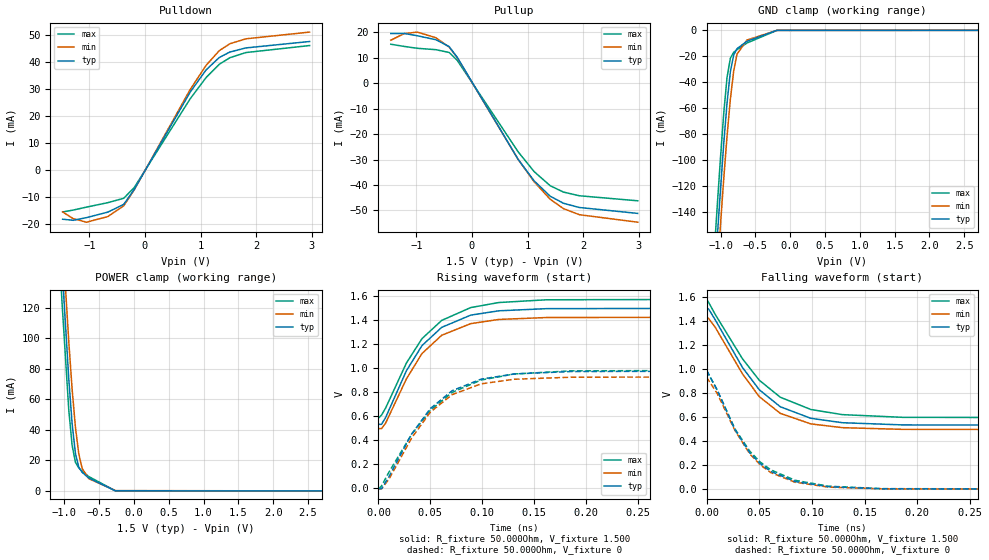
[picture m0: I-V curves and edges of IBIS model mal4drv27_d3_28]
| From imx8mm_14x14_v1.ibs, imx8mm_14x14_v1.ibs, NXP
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[Model] mal4drv27_d3_28
Model_type   I/O
Polarity   Non-Inverting
Enable   Active-High
C_comp   1.533pF   1.523pF   1.539pF
C_comp_pullup   670.608fF   654.490fF   675.558fF
C_comp_pulldown 804.263fF   796.382fF   819.192fF
Vinh = 885.000mV
Vinl = 615.000mV
Vmeas = 750.000mV
Vref = 750.000mV
Rref = 50Ohms
Cref = 0pF
[Model Spec]
Vinh   885.000mV   848.000mV   923.000mV
Vinl   615.000mV   578.000mV   653.000mV
Vmeas   750.000mV   713.000mV   788.000mV
Vref   750.000mV   713.000mV   788.000mV
D_overshoot_ampl_h 0.4 NA   NA
D_overshoot_ampl_l 0.4 NA   NA
D_overshoot_area_l 100.000m NA   NA
D_overshoot_area_h 100.000m NA   NA
|[Receiver Thresholds]
|Vth = 750.000mV
|Vth_min = 713.000mV
|Vth_max = 788.000mV
|Vinh_ac = 135.000mV
|Vinh_dc = 100.000mV
|Vinl_ac = -135.000mV
|Vinl_dc = -100.000mV
|Tslew_ac = 5.000ns
|Threshold_sensitivity = 0.5
|Reference_supply Pullup_ref
[Temperature Range]   25.000   125.000   -40.000
[Voltage Range]   1.500V   1.425V   1.575V
[GND Clamp Reference]   0.00V   0.00V   0.00V
|[C Comp Corner]
|| variable   typ   min   max
|C_comp 1.539pF   1.523pF   1.533pF
|C_comp_pullup 675.558fF   654.490fF   670.608fF
|C_comp_pulldown 804.263fF   819.192fF   796.382fF
[Pulldown Reference]   0.00V   0.00V   0.00V
[POWER Clamp Reference]   1.500V   1.425V   1.575V
[Pullup Reference]   1.500V   1.425V   1.575V
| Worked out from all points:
|   slope of the pulldown table from 0 to 0.225 V, typ, clamps not added: 27 ohm
|   slope of the pullup table from 0 to 0.225 V, typ, clamps not added: 26.4 ohm
|   GND clamp passes 1 mA (typ) near -0.34 V on its own axis
|   POWER clamp passes 1 mA (typ) near -0.38 V on its own axis
|   rising waveform, R_fixture 50.000Ohm, V_fixture 1.500: 20-80 % time 41.5ps typ, 40.5ps min, 44.6ps max; typ from 0.53 V to 1.5 V
|   rising waveform, R_fixture 50.000Ohm, V_fixture 0: 20-80 % time 49.5ps typ, 47ps min, 55.1ps max; typ from -0.006 V to 0.975 V
|   falling waveform, R_fixture 50.000Ohm, V_fixture 1.500: 20-80 % time 48.7ps typ, 45.6ps min, 52.4ps max; typ from 1.51 V to 0.531 V
|   falling waveform, R_fixture 50.000Ohm, V_fixture 0: 20-80 % time 41.1ps typ, 40.2ps min, 43.1ps max; typ from 0.987 V to 0 V
[GND Clamp]
-1.48V    -544.8mA   -568.8mA   -521.8mA
-1.098V   -202mA     -228.3mA   -177.7mA
-1.05V    -162.1mA   -188.8mA   -137.5mA
-1.002V   -123.7mA   -150.8mA   -99.19mA
-954.6mV  -87.74mA   -114.8mA   -64.27mA
-906.8mV  -56.04mA   -81.7mA    -36.4mA
-859.1mV  -31.98mA   -53.11mA   -21.49mA
-811.4mV  -19.02mA   -31.4mA    -16.97mA
-763.6mV  -14.17mA   -18.33mA   -14.9mA
-620.5mV  -8.403mA   -7.484mA   -9.776mA
-190.9mV  -18.19uA   -37.84uA   -39.11uA
2.959V    60.05nA    717.2nA    25.66nA
[Power Clamp]
-1.459V   528mA      548.1mA    506.8mA
-1.125V   225.9mA    248.6mA    203.4mA
-1.077V   185.1mA    208.4mA    162.3mA
-1.03V    145.5mA    169.5mA    122.6mA
-934.1mV  73.22mA    97.65mA    52.94mA
-886.4mV  44.08mA    66.72mA    29.89mA
-838.6mV  24.44mA    41.59mA    18.79mA
-790.9mV  15.63mA    24.32mA    15.05mA
-743.2mV  12.25mA    14.83mA    13mA
-647.7mV  8.45mA     8.03mA     9.427mA
-265.9mV  72.13uA    219.4uA    104uA
2.98V     -171.5nA   -1.946uA   -77.31nA
[Pulldown]
-1.48V    -18.3mA    -15.6mA    -15.6mA
-1.289V   -18.7mA    -18.1mA    -14.9mA
-1.05V    -17.7mA    -19.4mA    -13.8mA
-668.2mV  -15.66mA   -17.31mA   -12.15mA
-381.8mV  -12.79mA   -13.32mA   -10.52mA
-190.9mV  -7.166mA   -7.317mA   -6.472mA
811.4mV   28.86mA    29.82mA    26.39mA
1.098V    37.13mA    38.82mA    34.29mA
1.336V    41.77mA    44.32mA    39.24mA
1.527V    43.8mA     46.87mA    41.69mA
1.814V    45.32mA    48.7mA     43.6mA
2.959V    47.7mA     51.2mA     46.2mA
[Pullup]
-1.459V   19.6mA     16.94mA    15.36mA
-1.22V    19.6mA     19.53mA    14.51mA
-981.8mV  18.7mA     20.14mA    13.76mA
-647.7mV  17.13mA    17.91mA    13.22mA
-409.1mV  14.41mA    14.22mA    12.11mA
-265.9mV  10.25mA    10.11mA    9.057mA
831.8mV   -29.99mA   -30.03mA   -27.02mA
1.118V    -38.41mA   -38.76mA   -34.76mA
1.405V    -44.41mA   -45.6mA    -40.29mA
1.643V    -47.2mA    -49.3mA    -42.8mA
1.93V     -48.88mA   -51.71mA   -44.26mA
2.98V     -51.2mA    -54.66mA   -46.24mA
[Ramp]
R_load=50.000Ohm
dV/dt_r   583.230mV/46.000ps  556.979mV/44.500ps  589.380mV/51.000ps
dV/dt_f   583.230mV/46.000ps  556.979mV/44.000ps  589.380mV/49.000ps
[Rising waveform]
R_fixture=50.000Ohm
V_fixture=1.500
V_fixture_min=1.425
V_fixture_max=1.575
0s        530.4mV    494.7mV    582.1mV
3ps       530.4mV    494.7mV    607.7mV
7ps       588.4mV    542mV      667.8mV
27ps      977.4mV    909.9mV    1.042V
42ps      1.187V     1.121V     1.245V
61ps      1.339V     1.273V     1.397V
89ps      1.441V     1.37V      1.504V
116ps     1.477V     1.405V     1.546V
162ps     1.495V     1.421V     1.569V
472ps     1.5V       1.425V     1.575V
[Rising waveform]
R_fixture=50.000Ohm
V_fixture=0
0s        -6.374mV   -7.44mV    -10.22mV
3ps       -6.374mV   -7.44mV    17.2mV
10ps      92.15mV    71.39mV    129.8mV
32ps      449.3mV    415.8mV    447.3mV
50ps      661.4mV    631.8mV    647.2mV
71ps      810.4mV    777.8mV    796.3mV
99ps      907.2mV    867.9mV    899.7mV
131ps     950.5mV    906.4mV    950.3mV
186ps     970.9mV    923.4mV    976.5mV
472ps     975.3mV    926.8mV    982.7mV
[Falling waveform]
R_fixture=50.000Ohm
V_fixture=1.500
V_fixture_min=1.425
V_fixture_max=1.575
0s        1.509V     1.428V     1.581V
2ps       1.497V     1.419V     1.552V
8ps       1.411V     1.349V     1.456V
34ps      1.013V     960.1mV    1.085V
50ps      827.1mV    769.5mV    906.1mV
70ps      685.3mV    630.4mV    764.5mV
99ps      589.3mV    542.9mV    662.4mV
129ps     552.7mV    511.4mV    619.9mV
186ps     534.4mV    497.4mV    597.5mV
470ps     531.3mV    495.3mV    593.3mV
[Falling waveform]
R_fixture=50.000Ohm
V_fixture=0
0s        986.6mV    930.6mV    988.4mV
10ps      825.6mV    796.4mV    824.7mV
27ps      493.4mV    486.5mV    500mV
41ps      302.2mV    293.5mV    315.4mV
51ps      211.4mV    201.6mV    224.9mV
61ps      147.7mV    137.9mV    160.7mV
84ps      63.62mV    57.49mV    73.68mV
116ps     20.23mV    16.84mV    24.51mV
167ps     3.111mV    2.429mV    4.208mV
469ps     16.12uV    19.39uV    17.05uV
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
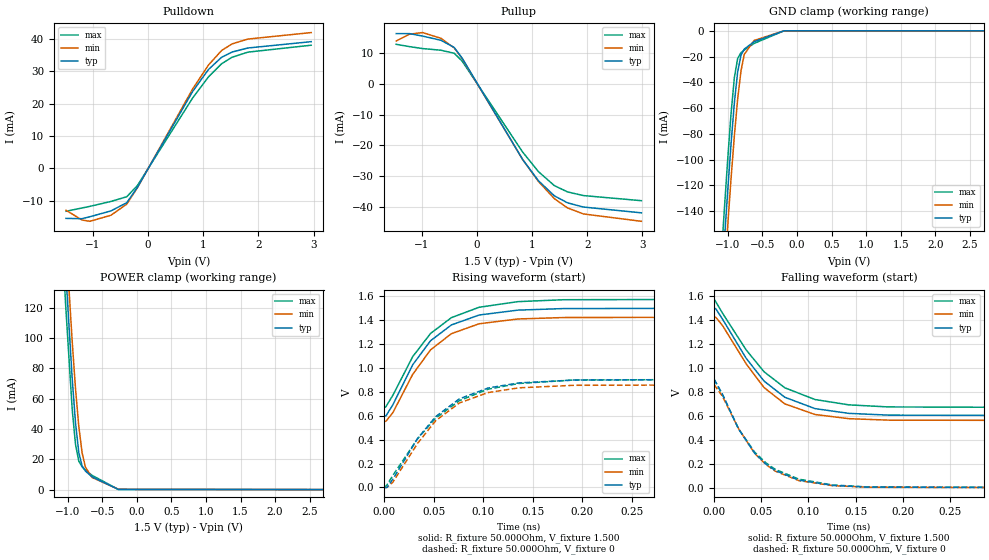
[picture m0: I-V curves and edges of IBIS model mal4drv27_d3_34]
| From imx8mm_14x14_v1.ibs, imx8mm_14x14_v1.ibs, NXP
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[Model] mal4drv27_d3_34
Model_type   I/O
Polarity   Non-Inverting
Enable   Active-High
C_comp   1.533pF   1.523pF   1.539pF
C_comp_pullup   670.608fF   654.490fF   675.558fF
C_comp_pulldown 804.263fF   796.382fF   819.192fF
Vinh = 885.000mV
Vinl = 615.000mV
Vmeas = 750.000mV
Vref = 750.000mV
Rref = 50Ohms
Cref = 0pF
[Model Spec]
Vinh   885.000mV   848.000mV   923.000mV
Vinl   615.000mV   578.000mV   653.000mV
Vmeas   750.000mV   713.000mV   788.000mV
Vref   750.000mV   713.000mV   788.000mV
D_overshoot_ampl_h 0.4 NA   NA
D_overshoot_ampl_l 0.4 NA   NA
D_overshoot_area_l 100.000m NA   NA
D_overshoot_area_h 100.000m NA   NA
|[Receiver Thresholds]
|Vth = 750.000mV
|Vth_min = 713.000mV
|Vth_max = 788.000mV
|Vinh_ac = 135.000mV
|Vinh_dc = 100.000mV
|Vinl_ac = -135.000mV
|Vinl_dc = -100.000mV
|Tslew_ac = 5.000ns
|Threshold_sensitivity = 0.5
|Reference_supply Pullup_ref
[Temperature Range]   25.000   125.000   -40.000
[Voltage Range]   1.500V   1.425V   1.575V
[GND Clamp Reference]   0.00V   0.00V   0.00V
|[C Comp Corner]
|| variable   typ   min   max
|C_comp 1.539pF   1.523pF   1.533pF
|C_comp_pullup 675.558fF   654.490fF   670.608fF
|C_comp_pulldown 804.263fF   819.192fF   796.382fF
[Pulldown Reference]   0.00V   0.00V   0.00V
[POWER Clamp Reference]   1.500V   1.425V   1.575V
[Pullup Reference]   1.500V   1.425V   1.575V
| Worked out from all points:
|   slope of the pulldown table from 0 to 0.225 V, typ, clamps not added: 32.8 ohm
|   slope of the pullup table from 0 to 0.225 V, typ, clamps not added: 32.1 ohm
|   GND clamp passes 1 mA (typ) near -0.34 V on its own axis
|   POWER clamp passes 1 mA (typ) near -0.38 V on its own axis
|   rising waveform, R_fixture 50.000Ohm, V_fixture 1.500: 20-80 % time 46.3ps typ, 45.6ps min, 49.1ps max; typ from 0.598 V to 1.5 V
|   rising waveform, R_fixture 50.000Ohm, V_fixture 0: 20-80 % time 55.5ps typ, 52.8ps min, 60.9ps max; typ from 0 V to 0.905 V
|   falling waveform, R_fixture 50.000Ohm, V_fixture 1.500: 20-80 % time 54.3ps typ, 51.1ps min, 57.7ps max; typ from 1.5 V to 0.602 V
|   falling waveform, R_fixture 50.000Ohm, V_fixture 0: 20-80 % time 45.7ps typ, 44.8ps min, 47.8ps max; typ from 0.908 V to 0 V
[GND Clamp]
-1.48V    -544.8mA   -568.8mA   -521.8mA
-1.098V   -202mA     -228.3mA   -177.7mA
-1.05V    -162.1mA   -188.8mA   -137.5mA
-1.002V   -123.7mA   -150.8mA   -99.19mA
-954.6mV  -87.74mA   -114.8mA   -64.27mA
-906.8mV  -56.04mA   -81.7mA    -36.4mA
-859.1mV  -31.98mA   -53.11mA   -21.49mA
-811.4mV  -19.02mA   -31.4mA    -16.97mA
-763.6mV  -14.17mA   -18.33mA   -14.9mA
-620.5mV  -8.403mA   -7.484mA   -9.776mA
-190.9mV  -18.19uA   -37.84uA   -39.11uA
2.959V    60.05nA    717.2nA    25.66nA
[Power Clamp]
-1.459V   528mA      548.1mA    506.8mA
-1.125V   225.9mA    248.6mA    203.4mA
-1.077V   185.1mA    208.4mA    162.3mA
-1.03V    145.5mA    169.5mA    122.6mA
-934.1mV  73.22mA    97.65mA    52.94mA
-886.4mV  44.08mA    66.72mA    29.89mA
-838.6mV  24.44mA    41.59mA    18.79mA
-790.9mV  15.63mA    24.32mA    15.05mA
-743.2mV  12.25mA    14.83mA    13mA
-647.7mV  8.45mA     8.03mA     9.427mA
-265.9mV  72.13uA    219.4uA    104uA
2.98V     -171.5nA   -1.946uA   -77.31nA
[Pulldown]
-1.48V    -15.4mA    -12.9mA    -13.2mA
-1.193V   -15.5mA    -15.9mA    -12.2mA
-1.05V    -14.9mA    -16.3mA    -11.7mA
-668.2mV  -13.1mA    -14.44mA   -10.18mA
-381.8mV  -10.57mA   -11.01mA   -8.726mA
-190.9mV  -5.895mA   -6.016mA   -5.33mA
811.4mV   23.73mA    24.5mA     21.72mA
1.098V    30.51mA    31.88mA    28.23mA
1.336V    34.29mA    36.37mA    32.29mA
1.527V    35.91mA    38.42mA    34.3mA
1.814V    37.15mA    39.9mA     35.87mA
2.959V    39.1mA     41.9mA     38mA
[Pullup]
-1.459V   16.4mA     13.99mA    12.91mA
-1.22V    16.4mA     16.21mA    12.16mA
-981.8mV  15.6mA     16.74mA    11.53mA
-647.7mV  14.22mA    14.86mA    10.98mA
-409.1mV  11.89mA    11.73mA    10mA
-265.9mV  8.431mA    8.312mA    7.457mA
831.8mV   -24.66mA   -24.66mA   -22.23mA
1.118V    -31.57mA   -31.81mA   -28.6mA
1.405V    -36.47mA   -37.39mA   -33.14mA
1.643V    -38.74mA   -40.4mA    -35.18mA
1.93V     -40.11mA   -42.36mA   -36.38mA
2.98V     -42mA      -44.76mA   -38.04mA
[Ramp]
R_load=50.000Ohm
dV/dt_r   540.840mV/52.000ps  516.868mV/50.500ps  543.990mV/55.500ps
dV/dt_f   540.840mV/50.500ps  516.899mV/49.000ps  543.990mV/54.000ps
[Rising waveform]
R_fixture=50.000Ohm
V_fixture=1.500
V_fixture_min=1.425
V_fixture_max=1.575
0s        598.3mV    553.6mV    665.3mV
2ps       598.3mV    553.6mV    675.7mV
9ps       692mV      625.8mV    771.2mV
29ps      1.026V     945.9mV    1.094V
47ps      1.227V     1.151V     1.288V
68ps      1.359V     1.286V     1.42V
96ps      1.442V     1.369V     1.507V
135ps     1.483V     1.409V     1.554V
181ps     1.496V     1.421V     1.57V
471ps     1.5V       1.425V     1.575V
[Rising waveform]
R_fixture=50.000Ohm
V_fixture=0
0s        -432.4uV   -59.57uV   -3.267mV
3ps       -432.4uV   -59.57uV   19.98mV
9ps       69.75mV    44.27mV    101.4mV
34ps      410.8mV    369.8mV    408.6mV
52ps      591.3mV    556.5mV    578.3mV
76ps      740.6mV    706.4mV    725.9mV
105ps     831.9mV    793.6mV    821.7mV
136ps     874.3mV    833.2mV    869.6mV
192ps     898.4mV    854.5mV    898.8mV
472ps     904.7mV    859.5mV    907mV
[Falling waveform]
R_fixture=50.000Ohm
V_fixture=1.500
V_fixture_min=1.425
V_fixture_max=1.575
0s        1.504V     1.43V      1.577V
2ps       1.494V     1.423V     1.552V
9ps       1.409V     1.356V     1.459V
34ps      1.083V     1.037V     1.153V
53ps      892.3mV    838mV      970.2mV
75ps      757.1mV    701.9mV    836.3mV
107ps     662.2mV    613mV      738.1mV
143ps     622.4mV    578.1mV    693.5mV
185ps     607.7mV    565.9mV    676.2mV
470ps     601.9mV    561.6mV    668.8mV
[Falling waveform]
R_fixture=50.000Ohm
V_fixture=0
0s        908.5mV    863.1mV    906.9mV
9ps       780.6mV    763.5mV    776.1mV
26ps      491.2mV    494.1mV    493.6mV
43ps      290.1mV    287.9mV    299.1mV
55ps      198.7mV    194.2mV    209.2mV
65ps      144.5mV    139.3mV    154.2mV
90ps      64.4mV     60.54mV    72.51mV
126ps     20.19mV    18.16mV    23.97mV
163ps     6.293mV    5.311mV    7.625mV
469ps     14.93uV    17.67uV    16.07uV
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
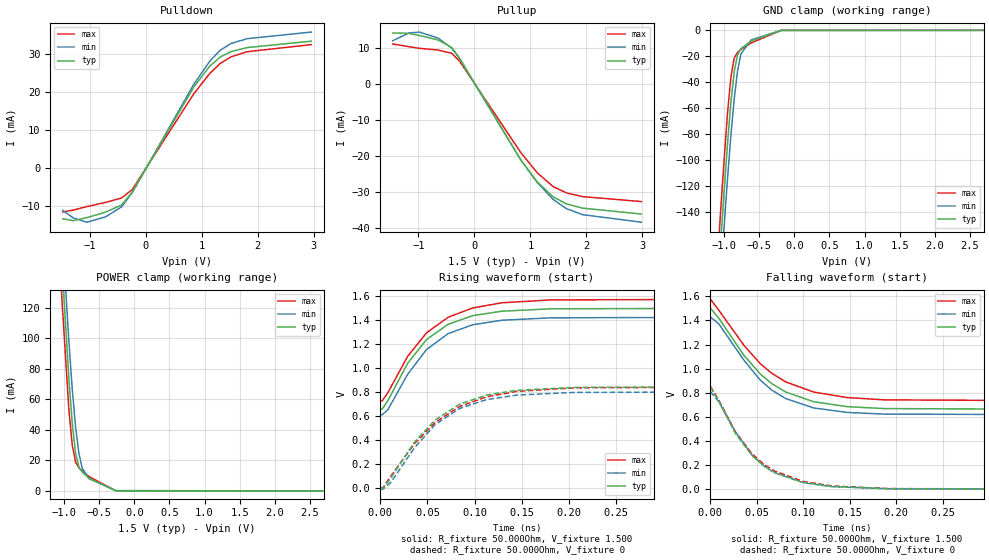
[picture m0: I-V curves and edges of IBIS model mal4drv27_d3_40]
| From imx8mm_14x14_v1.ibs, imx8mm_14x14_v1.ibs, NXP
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[Model] mal4drv27_d3_40
Model_type   I/O
Polarity   Non-Inverting
Enable   Active-High
C_comp   1.533pF   1.523pF   1.539pF
C_comp_pullup   670.608fF   654.490fF   675.558fF
C_comp_pulldown 804.263fF   796.382fF   819.192fF
Vinh = 885.000mV
Vinl = 615.000mV
Vmeas = 750.000mV
Vref = 750.000mV
Rref = 50Ohms
Cref = 0pF
[Model Spec]
Vinh   885.000mV   848.000mV   923.000mV
Vinl   615.000mV   578.000mV   653.000mV
Vmeas   750.000mV   713.000mV   788.000mV
Vref   750.000mV   713.000mV   788.000mV
D_overshoot_ampl_h 0.4 NA   NA
D_overshoot_ampl_l 0.4 NA   NA
D_overshoot_area_l 100.000m NA   NA
D_overshoot_area_h 100.000m NA   NA
|[Receiver Thresholds]
|Vth = 750.000mV
|Vth_min = 713.000mV
|Vth_max = 788.000mV
|Vinh_ac = 135.000mV
|Vinh_dc = 100.000mV
|Vinl_ac = -135.000mV
|Vinl_dc = -100.000mV
|Tslew_ac = 5.000ns
|Threshold_sensitivity = 0.5
|Reference_supply Pullup_ref
[Temperature Range]   25.000   125.000   -40.000
[Voltage Range]   1.500V   1.425V   1.575V
[GND Clamp Reference]   0.00V   0.00V   0.00V
|[C Comp Corner]
|| variable   typ   min   max
|C_comp 1.539pF   1.523pF   1.533pF
|C_comp_pullup 675.558fF   654.490fF   670.608fF
|C_comp_pulldown 804.263fF   819.192fF   796.382fF
[Pulldown Reference]   0.00V   0.00V   0.00V
[POWER Clamp Reference]   1.500V   1.425V   1.575V
[Pullup Reference]   1.500V   1.425V   1.575V
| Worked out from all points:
|   slope of the pulldown table from 0 to 0.225 V, typ, clamps not added: 38.3 ohm
|   slope of the pullup table from 0 to 0.225 V, typ, clamps not added: 37.5 ohm
|   GND clamp passes 1 mA (typ) near -0.34 V on its own axis
|   POWER clamp passes 1 mA (typ) near -0.38 V on its own axis
|   rising waveform, R_fixture 50.000Ohm, V_fixture 1.500: 20-80 % time 50.2ps typ, 49.3ps min, 52.9ps max; typ from 0.659 V to 1.5 V
|   rising waveform, R_fixture 50.000Ohm, V_fixture 0: 20-80 % time 60.3ps typ, 57.6ps min, 65.6ps max; typ from 0 V to 0.846 V
|   falling waveform, R_fixture 50.000Ohm, V_fixture 1.500: 20-80 % time 59.2ps typ, 55.5ps min, 62.4ps max; typ from 1.5 V to 0.66 V
|   falling waveform, R_fixture 50.000Ohm, V_fixture 0: 20-80 % time 49.5ps typ, 48.5ps min, 51.7ps max; typ from 0.847 V to 0 V
[GND Clamp]
-1.48V    -544.8mA   -568.8mA   -521.8mA
-1.098V   -202mA     -228.3mA   -177.7mA
-1.05V    -162.1mA   -188.8mA   -137.5mA
-1.002V   -123.7mA   -150.8mA   -99.19mA
-954.6mV  -87.74mA   -114.8mA   -64.27mA
-906.8mV  -56.04mA   -81.7mA    -36.4mA
-859.1mV  -31.98mA   -53.11mA   -21.49mA
-811.4mV  -19.02mA   -31.4mA    -16.97mA
-763.6mV  -14.17mA   -18.33mA   -14.9mA
-620.5mV  -8.403mA   -7.484mA   -9.776mA
-190.9mV  -18.19uA   -37.84uA   -39.11uA
2.959V    60.05nA    717.2nA    25.66nA
[Power Clamp]
-1.459V   528mA      548.1mA    506.8mA
-1.125V   225.9mA    248.6mA    203.4mA
-1.077V   185.1mA    208.4mA    162.3mA
-1.03V    145.5mA    169.5mA    122.6mA
-934.1mV  73.22mA    97.65mA    52.94mA
-886.4mV  44.08mA    66.72mA    29.89mA
-838.6mV  24.44mA    41.59mA    18.79mA
-790.9mV  15.63mA    24.32mA    15.05mA
-743.2mV  12.25mA    14.83mA    13mA
-647.7mV  8.45mA     8.03mA     9.427mA
-265.9mV  72.13uA    219.4uA    104uA
2.98V     -171.5nA   -1.946uA   -77.31nA
[Pulldown]
-1.48V    -13.3mA    -11.1mA    -11.5mA
-1.289V   -13.8mA    -13.1mA    -11mA
-1.05V    -13mA      -14.2mA    -10.1mA
-715.9mV  -11.56mA   -12.8mA    -8.98mA
-429.5mV  -9.667mA   -10.17mA   -7.842mA
-238.6mV  -6.277mA   -6.401mA   -5.606mA
859.1mV   21.39mA    22.11mA    19.61mA
1.145V    26.92mA    28.21mA    24.99mA
1.336V    29.36mA    31.15mA    27.67mA
1.527V    30.76mA    32.91mA    29.39mA
1.814V    31.82mA    34.17mA    30.73mA
2.959V    33.5mA     35.9mA     32.6mA
[Pullup]
-1.459V   14.2mA     12.03mA    11.16mA
-1.173V   14.1mA     14.17mA    10.4mA
-981.8mV  13.5mA     14.44mA    9.949mA
-647.7mV  12.25mA    12.77mA    9.455mA
-409.1mV  10.2mA     10.05mA    8.58mA
-265.9mV  7.219mA    7.111mA    6.387mA
831.8mV   -21.11mA   -21.08mA   -19.04mA
1.118V    -27.03mA   -27.19mA   -24.5mA
1.405V    -31.23mA   -31.95mA   -28.39mA
1.643V    -33.18mA   -34.51mA   -30.14mA
1.93V     -34.36mA   -36.17mA   -31.17mA
2.98V     -36mA      -38.26mA   -32.54mA
[Ramp]
R_load=50.000Ohm
dV/dt_r   505.770mV/56.500ps  483.718mV/54.000ps  506.700mV/60.000ps
dV/dt_f   505.770mV/55.500ps  483.719mV/52.500ps  506.700mV/57.500ps
[Rising waveform]
R_fixture=50.000Ohm
V_fixture=1.500
V_fixture_min=1.425
V_fixture_max=1.575
0s        658.8mV    612.3mV    727.8mV
2ps       658.8mV    612.3mV    727.8mV
8ps       729.2mV    653.9mV    795.7mV
29ps      1.04V      948.6mV    1.098V
49ps      1.238V     1.155V     1.294V
72ps      1.365V     1.288V     1.424V
98ps      1.437V     1.361V     1.501V
129ps     1.474V     1.399V     1.544V
181ps     1.494V     1.419V     1.568V
471ps     1.5V       1.425V     1.575V
[Rising waveform]
R_fixture=50.000Ohm
V_fixture=0
0s        -153.4uV   -6.514mV   -2.403mV
3ps       -153.4uV   -6.514mV   7.118mV
11ps      84.07mV    48.43mV    100.2mV
36ps      381.9mV    334.9mV    369.5mV
58ps      567.9mV    529.4mV    547.4mV
84ps      700.1mV    664.1mV    680.9mV
113ps     777mV      739.2mV    762.5mV
145ps     815.9mV    776.4mV    807.4mV
207ps     840.2mV    798.5mV    836.8mV
472ps     846.2mV    803.7mV    844.6mV
[Falling waveform]
R_fixture=50.000Ohm
V_fixture=1.500
V_fixture_min=1.425
V_fixture_max=1.575
0s        1.503V     1.428V     1.577V
9ps       1.42V      1.373V     1.486V
36ps      1.112V     1.072V     1.195V
54ps      953.4mV    902.7mV    1.039V
66ps      876.1mV    822.6mV    962.1mV
81ps      806.3mV    751.8mV    890.2mV
111ps     725.4mV    674mV      805.9mV
147ps     684.7mV    636.5mV    760mV
187ps     668.4mV    622.8mV    740.9mV
470ps     660.3mV    616.3mV    730.7mV
[Falling waveform]
R_fixture=50.000Ohm
V_fixture=0
0s        846.9mV    810.5mV    853.9mV
9ps       732.2mV    726.8mV    741.1mV
27ps      462.3mV    475.2mV    476.1mV
45ps      277mV      281.5mV    292.5mV
58ps      190.1mV    190.8mV    204.4mV
69ps      138mV      136.6mV    150.9mV
100ps     55.26mV    53.45mV    63.65mV
131ps     22.12mV    20.65mV    26.33mV
191ps     3.849mV    3.316mV    4.76mV
469ps     15.91uV    19.07uV    17.08uV
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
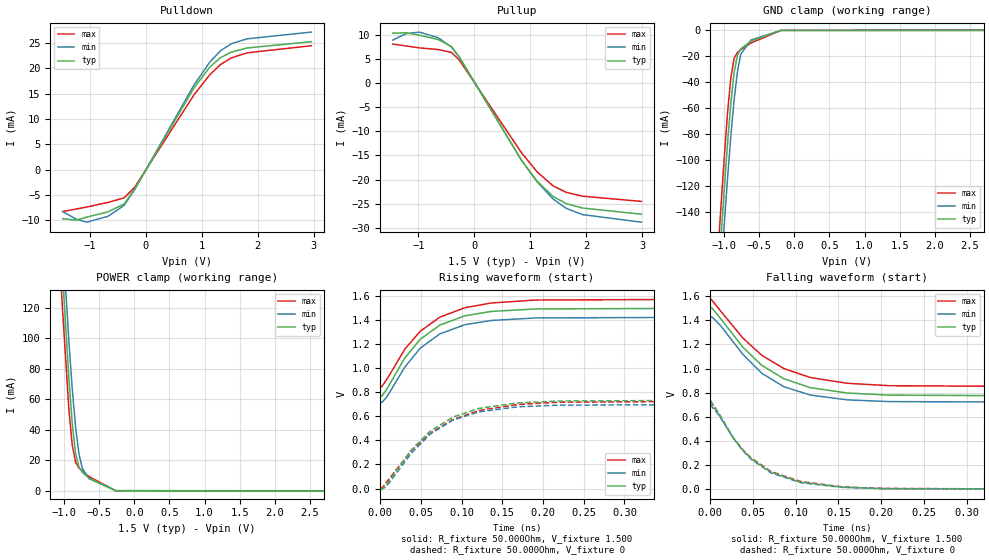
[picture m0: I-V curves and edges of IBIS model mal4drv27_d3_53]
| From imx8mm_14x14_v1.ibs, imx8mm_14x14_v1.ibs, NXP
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[Model] mal4drv27_d3_53
Model_type   I/O
Polarity   Non-Inverting
Enable   Active-High
C_comp   1.533pF   1.523pF   1.539pF
C_comp_pullup   670.608fF   654.490fF   675.558fF
C_comp_pulldown 804.263fF   796.382fF   819.192fF
Vinh = 885.000mV
Vinl = 615.000mV
Vmeas = 750.000mV
Vref = 750.000mV
Rref = 50Ohms
Cref = 0pF
[Model Spec]
Vinh   885.000mV   848.000mV   923.000mV
Vinl   615.000mV   578.000mV   653.000mV
Vmeas   750.000mV   713.000mV   788.000mV
Vref   750.000mV   713.000mV   788.000mV
D_overshoot_ampl_h 0.4 NA   NA
D_overshoot_ampl_l 0.4 NA   NA
D_overshoot_area_l 100.000m NA   NA
D_overshoot_area_h 100.000m NA   NA
|[Receiver Thresholds]
|Vth = 750.000mV
|Vth_min = 713.000mV
|Vth_max = 788.000mV
|Vinh_ac = 135.000mV
|Vinh_dc = 100.000mV
|Vinl_ac = -135.000mV
|Vinl_dc = -100.000mV
|Tslew_ac = 5.000ns
|Threshold_sensitivity = 0.5
|Reference_supply Pullup_ref
[Temperature Range]   25.000   125.000   -40.000
[Voltage Range]   1.500V   1.425V   1.575V
[GND Clamp Reference]   0.00V   0.00V   0.00V
|[C Comp Corner]
|| variable   typ   min   max
|C_comp 1.539pF   1.523pF   1.533pF
|C_comp_pullup 675.558fF   654.490fF   670.608fF
|C_comp_pulldown 804.263fF   819.192fF   796.382fF
[Pulldown Reference]   0.00V   0.00V   0.00V
[POWER Clamp Reference]   1.500V   1.425V   1.575V
[Pullup Reference]   1.500V   1.425V   1.575V
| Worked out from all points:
|   slope of the pulldown table from 0 to 0.225 V, typ, clamps not added: 51 ohm
|   slope of the pullup table from 0 to 0.225 V, typ, clamps not added: 49.9 ohm
|   GND clamp passes 1 mA (typ) near -0.34 V on its own axis
|   POWER clamp passes 1 mA (typ) near -0.38 V on its own axis
|   rising waveform, R_fixture 50.000Ohm, V_fixture 1.500: 20-80 % time 56.7ps typ, 55.9ps min, 59.6ps max; typ from 0.768 V to 1.5 V
|   rising waveform, R_fixture 50.000Ohm, V_fixture 0: 20-80 % time 68.1ps typ, 64.8ps min, 74ps max; typ from -0.003 V to 0.735 V
|   falling waveform, R_fixture 50.000Ohm, V_fixture 1.500: 20-80 % time 67.2ps typ, 62.7ps min, 70.6ps max; typ from 1.5 V to 0.771 V
|   falling waveform, R_fixture 50.000Ohm, V_fixture 0: 20-80 % time 56.1ps typ, 54.9ps min, 58.5ps max; typ from 0.737 V to 0 V
[GND Clamp]
-1.48V    -544.8mA   -568.8mA   -521.8mA
-1.098V   -202mA     -228.3mA   -177.7mA
-1.05V    -162.1mA   -188.8mA   -137.5mA
-1.002V   -123.7mA   -150.8mA   -99.19mA
-954.6mV  -87.74mA   -114.8mA   -64.27mA
-906.8mV  -56.04mA   -81.7mA    -36.4mA
-859.1mV  -31.98mA   -53.11mA   -21.49mA
-811.4mV  -19.02mA   -31.4mA    -16.97mA
-763.6mV  -14.17mA   -18.33mA   -14.9mA
-620.5mV  -8.403mA   -7.484mA   -9.776mA
-190.9mV  -18.19uA   -37.84uA   -39.11uA
2.959V    60.05nA    717.2nA    25.66nA
[Power Clamp]
-1.459V   528mA      548.1mA    506.8mA
-1.125V   225.9mA    248.6mA    203.4mA
-1.077V   185.1mA    208.4mA    162.3mA
-1.03V    145.5mA    169.5mA    122.6mA
-934.1mV  73.22mA    97.65mA    52.94mA
-886.4mV  44.08mA    66.72mA    29.89mA
-838.6mV  24.44mA    41.59mA    18.79mA
-790.9mV  15.63mA    24.32mA    15.05mA
-743.2mV  12.25mA    14.83mA    13mA
-647.7mV  8.45mA     8.03mA     9.427mA
-265.9mV  72.13uA    219.4uA    104uA
2.98V     -171.5nA   -1.946uA   -77.31nA
[Pulldown]
-1.48V    -9.7mA     -8.3mA     -8.3mA
-1.241V   -10mA      -9.8mA     -7.8mA
-1.05V    -9.4mA     -10.4mA    -7.4mA
-668.2mV  -8.35mA    -9.224mA   -6.48mA
-381.8mV  -6.776mA   -7.061mA   -5.581mA
-190.9mV  -3.789mA   -3.872mA   -3.424mA
859.1mV   16.07mA    16.64mA    14.71mA
1.145V    20.26mA    21.25mA    18.75mA
1.336V    22.14mA    23.5mA     20.77mA
1.527V    23.23mA    24.88mA    22.08mA
1.814V    24.06mA    25.87mA    23.1mA
2.959V    25.3mA     27.2mA     24.5mA
[Pullup]
-1.459V   10.4mA     8.971mA    8.157mA
-1.22V    10.5mA     10.31mA    7.757mA
-981.8mV  10mA       10.64mA    7.353mA
-647.7mV  9.1mA      9.478mA    7.018mA
-409.1mV  7.625mA    7.514mA    6.41mA
-265.9mV  5.416mA    5.336mA    4.788mA
831.8mV   -15.85mA   -15.84mA   -14.29mA
1.118V    -20.32mA   -20.45mA   -18.39mA
1.405V    -23.52mA   -24.05mA   -21.32mA
1.643V    -25.02mA   -26.01mA   -22.67mA
1.93V     -25.92mA   -27.28mA   -23.46mA
2.98V     -27.2mA    -28.86mA   -24.54mA
[Ramp]
R_load=50.000Ohm
dV/dt_r   439.110mV/63.500ps  421.318mV/61.500ps  436.140mV/67.500ps
dV/dt_f   439.140mV/62.500ps  421.318mV/60.000ps  436.170mV/65.500ps
[Rising waveform]
R_fixture=50.000Ohm
V_fixture=1.500
V_fixture_min=1.425
V_fixture_max=1.575
0s        768.2mV    715.8mV    841.3mV
2ps       768.2mV    715.8mV    848.5mV
8ps       825.2mV    760.3mV    906.7mV
30ps      1.084V     1.008V     1.157V
49ps      1.24V      1.166V     1.307V
73ps      1.358V     1.285V     1.424V
104ps     1.436V     1.362V     1.503V
136ps     1.472V     1.397V     1.542V
191ps     1.493V     1.418V     1.567V
471ps     1.5V       1.425V     1.575V
[Rising waveform]
R_fixture=50.000Ohm
V_fixture=0
0s        -3.219mV   -2.512mV   -5.418mV
3ps       -3.219mV   -2.512mV   10.6mV
8ps       35.87mV    21.7mV     56.3mV
38ps      319.2mV    292mV      312.9mV
61ps      474.7mV    450.8mV    458mV
89ps      592.9mV    568.1mV    573.4mV
121ps     665.6mV    636.9mV    648mV
168ps     711.1mV    678.7mV    698.1mV
218ps     727.4mV    693mV      717.4mV
472ps     734.9mV    699.1mV    726.9mV
[Falling waveform]
R_fixture=50.000Ohm
V_fixture=1.500
V_fixture_min=1.425
V_fixture_max=1.575
0s        1.502V     1.427V     1.576V
2ps       1.502V     1.427V     1.567V
12ps      1.415V     1.356V     1.478V
38ps      1.178V     1.119V     1.254V
60ps      1.028V     962.4mV    1.111V
86ps      915.5mV    849.3mV    1V
117ps     841.8mV    780.2mV    925.5mV
160ps     797.2mV    740.6mV    878mV
210ps     779.3mV    725.8mV    857.7mV
471ps     771.3mV    719.7mV    848.1mV
[Falling waveform]
R_fixture=50.000Ohm
V_fixture=0
0s        737mV      700.3mV    730mV
10ps      629.1mV    615.3mV    619.4mV
27ps      425.9mV    422.1mV    424.1mV
38ps      324.8mV    319.5mV    326.7mV
48ps      252.4mV    247mV      257.1mV
71ps      141mV      135mV      147mV
106ps     57.49mV    53.72mV    62.71mV
155ps     16.43mV    14.76mV    18.67mV
203ps     4.635mV    4.158mV    5.638mV
469ps     19.52uV    26.25uV    24.82uV
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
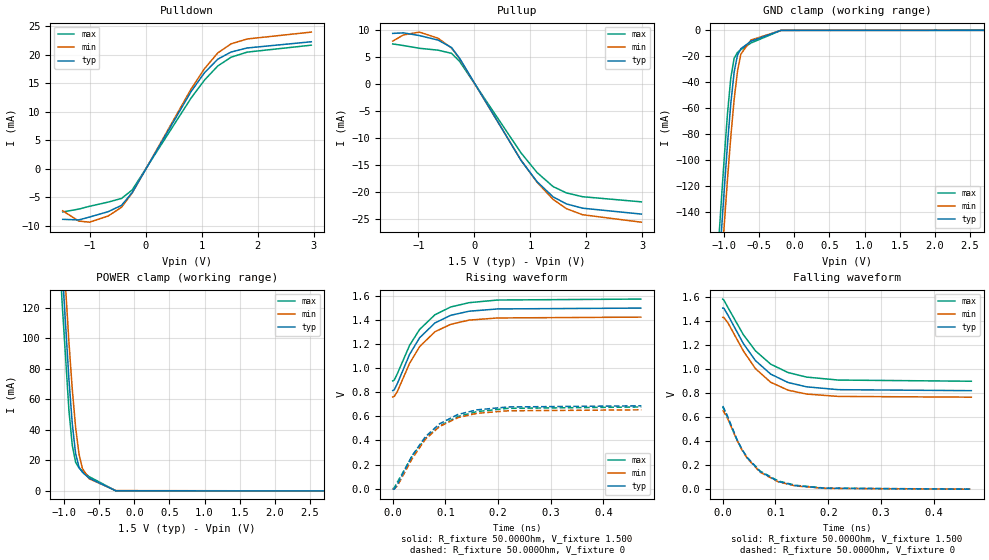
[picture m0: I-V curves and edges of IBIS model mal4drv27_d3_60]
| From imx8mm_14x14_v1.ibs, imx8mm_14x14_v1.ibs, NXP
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[Model] mal4drv27_d3_60
Model_type   I/O
Polarity   Non-Inverting
Enable   Active-High
C_comp   1.533pF   1.523pF   1.539pF
C_comp_pullup   670.608fF   654.490fF   675.558fF
C_comp_pulldown 804.263fF   796.382fF   819.192fF
Vinh = 885.000mV
Vinl = 615.000mV
Vmeas = 750.000mV
Vref = 750.000mV
Rref = 50Ohms
Cref = 0pF
[Model Spec]
Vinh   885.000mV   848.000mV   923.000mV
Vinl   615.000mV   578.000mV   653.000mV
Vmeas   750.000mV   713.000mV   788.000mV
Vref   750.000mV   713.000mV   788.000mV
D_overshoot_ampl_h 0.4 NA   NA
D_overshoot_ampl_l 0.4 NA   NA
D_overshoot_area_l 100.000m NA   NA
D_overshoot_area_h 100.000m NA   NA
|[Receiver Thresholds]
|Vth = 750.000mV
|Vth_min = 713.000mV
|Vth_max = 788.000mV
|Vinh_ac = 135.000mV
|Vinh_dc = 100.000mV
|Vinl_ac = -135.000mV
|Vinl_dc = -100.000mV
|Tslew_ac = 5.000ns
|Threshold_sensitivity = 0.5
|Reference_supply Pullup_ref
[Temperature Range]   25.000   125.000   -40.000
[Voltage Range]   1.500V   1.425V   1.575V
[GND Clamp Reference]   0.00V   0.00V   0.00V
|[C Comp Corner]
|| variable   typ   min   max
|C_comp 1.539pF   1.523pF   1.533pF
|C_comp_pullup 675.558fF   654.490fF   670.608fF
|C_comp_pulldown 804.263fF   819.192fF   796.382fF
[Pulldown Reference]   0.00V   0.00V   0.00V
[POWER Clamp Reference]   1.500V   1.425V   1.575V
[Pullup Reference]   1.500V   1.425V   1.575V
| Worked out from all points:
|   slope of the pulldown table from 0 to 0.225 V, typ, clamps not added: 57.5 ohm
|   slope of the pullup table from 0 to 0.225 V, typ, clamps not added: 56.2 ohm
|   GND clamp passes 1 mA (typ) near -0.34 V on its own axis
|   POWER clamp passes 1 mA (typ) near -0.38 V on its own axis
|   rising waveform, R_fixture 50.000Ohm, V_fixture 1.500: 20-80 % time 60.1ps typ, 59.4ps min, 62.6ps max; typ from 0.814 V to 1.5 V
|   rising waveform, R_fixture 50.000Ohm, V_fixture 0: 20-80 % time 72.4ps typ, 68.9ps min, 77.7ps max; typ from -0.005 V to 0.688 V
|   falling waveform, R_fixture 50.000Ohm, V_fixture 1.500: 20-80 % time 71.6ps typ, 66.9ps min, 74.1ps max; typ from 1.5 V to 0.818 V
|   falling waveform, R_fixture 50.000Ohm, V_fixture 0: 20-80 % time 59.5ps typ, 58.3ps min, 61.6ps max; typ from 0.692 V to 0 V
[GND Clamp]
-1.48V    -544.8mA   -568.8mA   -521.8mA
-1.098V   -202mA     -228.3mA   -177.7mA
-1.05V    -162.1mA   -188.8mA   -137.5mA
-1.002V   -123.7mA   -150.8mA   -99.19mA
-954.6mV  -87.74mA   -114.8mA   -64.27mA
-906.8mV  -56.04mA   -81.7mA    -36.4mA
-859.1mV  -31.98mA   -53.11mA   -21.49mA
-811.4mV  -19.02mA   -31.4mA    -16.97mA
-763.6mV  -14.17mA   -18.33mA   -14.9mA
-620.5mV  -8.403mA   -7.484mA   -9.776mA
-190.9mV  -18.19uA   -37.84uA   -39.11uA
2.959V    60.05nA    717.2nA    25.66nA
[Power Clamp]
-1.459V   528mA      548.1mA    506.8mA
-1.125V   225.9mA    248.6mA    203.4mA
-1.077V   185.1mA    208.4mA    162.3mA
-1.03V    145.5mA    169.5mA    122.6mA
-934.1mV  73.22mA    97.65mA    52.94mA
-886.4mV  44.08mA    66.72mA    29.89mA
-838.6mV  24.44mA    41.59mA    18.79mA
-790.9mV  15.63mA    24.32mA    15.05mA
-743.2mV  12.25mA    14.83mA    13mA
-647.7mV  8.45mA     8.03mA     9.427mA
-265.9mV  72.13uA    219.4uA    104uA
2.98V     -171.5nA   -1.946uA   -77.31nA
[Pulldown]
-1.48V    -8.9mA     -7.4mA     -7.6mA
-1.193V   -9mA       -9.2mA     -7.1mA
-1.002V   -8.5mA     -9.4mA     -6.61mA
-668.2mV  -7.55mA    -8.314mA   -5.87mA
-429.5mV  -6.44mA    -6.777mA   -5.225mA
-238.6mV  -4.181mA   -4.264mA   -3.734mA
811.4mV   13.54mA    13.98mA    12.4mA
1.05V     16.84mA    17.55mA    15.55mA
1.289V    19.24mA    20.34mA    18.05mA
1.527V    20.5mA     21.94mA    19.59mA
1.814V    21.21mA    22.79mA    20.48mA
2.959V    22.3mA     24mA       21.7mA
[Pullup]
-1.459V   9.4mA      7.971mA    7.457mA
-1.268V   9.5mA      9.114mA    7.157mA
-981.8mV  9mA        9.643mA    6.649mA
-647.7mV  8.16mA     8.5mA      6.298mA
-409.1mV  6.791mA    6.695mA    5.716mA
-265.9mV  4.808mA    4.736mA    4.255mA
831.8mV   -14.07mA   -14.04mA   -12.68mA
1.118V    -18.01mA   -18.11mA   -16.32mA
1.405V    -20.82mA   -21.29mA   -18.92mA
1.643V    -22.12mA   -23mA      -20.09mA
1.93V     -22.91mA   -24.12mA   -20.79mA
2.98V     -24mA      -25.5mA    -21.74mA
[Ramp]
R_load=50.000Ohm
dV/dt_r   411.000mV/67.000ps  394.648mV/65.000ps  407.130mV/71.000ps
dV/dt_f   411.000mV/67.000ps  394.648mV/63.500ps  407.130mV/69.500ps
[Rising waveform]
R_fixture=50.000Ohm
V_fixture=1.500
V_fixture_min=1.425
V_fixture_max=1.575
0s        814.5mV    760.9mV    894.9mV
3ps       821.3mV    766.3mV    901.8mV
9ps       874.6mV    808.3mV    957.1mV
32ps      1.115V     1.041V     1.19V
51ps      1.253V     1.179V     1.322V
80ps      1.376V     1.303V     1.444V
110ps     1.44V      1.365V     1.509V
145ps     1.474V     1.4V       1.545V
199ps     1.493V     1.418V     1.567V
471ps     1.5V       1.425V     1.575V
[Rising waveform]
R_fixture=50.000Ohm
V_fixture=0
0s        -4.531mV   -2.395mV   -790.9uV
3ps       -4.531mV   -2.395mV   6.267mV
9ps       36.76mV    23.17mV    54.88mV
37ps      274.7mV    249.3mV    271.1mV
62ps      431.1mV    409.2mV    416.5mV
89ps      539mV      516.3mV    520.9mV
124ps     616.4mV    590.1mV    599.2mV
160ps     654.5mV    625.6mV    640mV
219ps     678.7mV    646.8mV    667mV
472ps     688.1mV    654.6mV    678.4mV
[Falling waveform]
R_fixture=50.000Ohm
V_fixture=1.500
V_fixture_min=1.425
V_fixture_max=1.575
0s        1.504V     1.427V     1.579V
2ps       1.504V     1.427V     1.572V
10ps      1.445V     1.381V     1.508V
39ps      1.21V      1.149V     1.284V
62ps      1.068V     1.001V     1.149V
91ps      955.4mV    887.6mV    1.038V
124ps     885.5mV    822.1mV    968.4mV
159ps     850mV      789.9mV    930.8mV
219ps     826.4mV    770.4mV    906.3mV
471ps     818.1mV    764.1mV    896.4mV
[Falling waveform]
R_fixture=50.000Ohm
V_fixture=0
0s        691.5mV    655.6mV    683.4mV
8ps       618.3mV    599.9mV    606.8mV
27ps      412.6mV    407.2mV    408mV
37ps      327.1mV    321.4mV    326.1mV
47ps      258.1mV    252.6mV    260mV
71ps      145.9mV    140.2mV    150.1mV
105ps     64.28mV    60.78mV    68.51mV
138ps     29mV       26.76mV    32.37mV
194ps     7.483mV    6.689mV    8.535mV
469ps     22.1uV     25.3uV     26.51uV
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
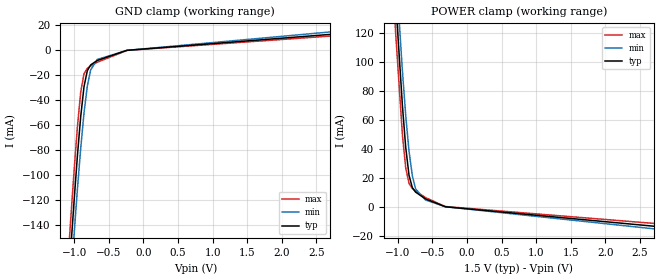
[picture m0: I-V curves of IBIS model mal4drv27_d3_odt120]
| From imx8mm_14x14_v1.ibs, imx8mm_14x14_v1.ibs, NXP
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[Model] mal4drv27_d3_odt120
Model_type   Input
Polarity   Non-Inverting
Enable   Active-High
C_comp   1.581pF   1.529pF   1.589pF
C_comp_power_clamp   705.233fF   662.420fF   705.801fF
C_comp_gnd_clamp 802.248fF   801.905fF   805.605fF
Vinh = 885.000mV
Vinl = 615.000mV
[Model Spec]
D_overshoot_ampl_h 0.4 NA   NA
D_overshoot_ampl_l 0.4 NA   NA
D_overshoot_area_l 100.000m NA   NA
D_overshoot_area_h 100.000m NA   NA
|[Receiver Thresholds]
|Vth = 750.000mV
|Vth_min = 713.000mV
|Vth_max = 788.000mV
|Vinh_ac = 135.000mV
|Vinh_dc = 100.000mV
|Vinl_ac = -135.000mV
|Vinl_dc = -100.000mV
|Tslew_ac = 5.000ns
|Threshold_sensitivity = 0.5
|Reference_supply Power_clamp_ref
[Temperature Range]   25.000   125.000   -40.000
[Voltage Range]   1.500V   1.425V   1.575V
[GND Clamp Reference]   0.00V   0.00V   0.00V
|[C Comp Corner]
|| variable   typ   min   max
|C_comp 1.581pF   1.529pF   1.589pF
|C_comp_pullup 705.801fF   662.420fF   705.233fF
|C_comp_pulldown 802.248fF   805.605fF   801.905fF
[POWER Clamp Reference]   1.500V   1.425V   1.575V
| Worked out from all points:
|   GND clamp passes 1 mA (typ) near -0.38 V on its own axis
|   POWER clamp passes 1 mA (typ) near -0.41 V on its own axis
[GND Clamp]
-1.48V    -538.2mA   -561mA     -515.9mA
-1.098V   -197.6mA   -223.5mA   -173.7mA
-1.05V    -158mA     -184.3mA   -133.7mA
-1.002V   -119.8mA   -146.7mA   -95.68mA
-954.6mV  -84.17mA   -110.9mA   -60.96mA
-906.8mV  -52.73mA   -78.17mA   -33.32mA
-859.1mV  -28.94mA   -49.88mA   -18.64mA
-811.4mV  -16.24mA   -28.48mA   -14.35mA
-763.6mV  -11.65mA   -15.7mA    -12.51mA
-668.2mV  -8.084mA   -7.258mA   -9.507mA
-238.6mV  33.73uA    26.23uA    -32.99uA
2.959V    13.89mA    16.01mA    12.44mA
[Power Clamp]
-1.459V   521.9mA    540.6mA    501.2mA
-1.125V   221.7mA    243.7mA    199.4mA
-1.077V   181.2mA    203.9mA    158.5mA
-1.03V    141.9mA    165.3mA    119mA
-934.1mV  70.07mA    93.99mA    49.83mA
-886.4mV  41.18mA    63.37mA    27.03mA
-838.6mV  21.8mA     38.52mA    16.17mA
-790.9mV  13.25mA    21.53mA    12.66mA
-743.2mV  10.13mA    12.33mA    10.85mA
-600mV    5.433mA    4.679mA    6.334mA
-313.6mV  -1.164uA   20.25uA    156.1uA
2.98V     -14.71mA   -16.68mA   -12.6mA
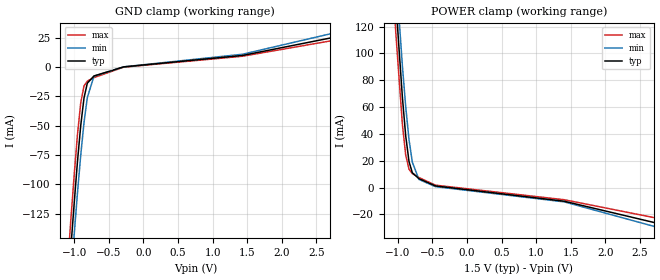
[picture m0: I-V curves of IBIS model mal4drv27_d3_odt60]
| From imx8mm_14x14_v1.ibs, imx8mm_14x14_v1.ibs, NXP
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[Model] mal4drv27_d3_odt60
Model_type   Input
Polarity   Non-Inverting
Enable   Active-High
C_comp   1.621pF   1.545pF   1.634pF
C_comp_power_clamp   734.334fF   679.882fF   737.030fF
C_comp_gnd_clamp 799.912fF   796.446fF   805.781fF
Vinh = 885.000mV
Vinl = 615.000mV
[Model Spec]
D_overshoot_ampl_h 0.4 NA   NA
D_overshoot_ampl_l 0.4 NA   NA
D_overshoot_area_l 100.000m NA   NA
D_overshoot_area_h 100.000m NA   NA
|[Receiver Thresholds]
|Vth = 750.000mV
|Vth_min = 713.000mV
|Vth_max = 788.000mV
|Vinh_ac = 135.000mV
|Vinh_dc = 100.000mV
|Vinl_ac = -135.000mV
|Vinl_dc = -100.000mV
|Tslew_ac = 5.000ns
|Threshold_sensitivity = 0.5
|Reference_supply Power_clamp_ref
[Temperature Range]   25.000   125.000   -40.000
[Voltage Range]   1.500V   1.425V   1.575V
[GND Clamp Reference]   0.00V   0.00V   0.00V
|[C Comp Corner]
|| variable   typ   min   max
|C_comp 1.621pF   1.545pF   1.634pF
|C_comp_pullup 737.030fF   679.882fF   734.334fF
|C_comp_pulldown 799.912fF   796.446fF   805.781fF
[POWER Clamp Reference]   1.500V   1.425V   1.575V
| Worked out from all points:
|   GND clamp passes 1 mA (typ) near -0.41 V on its own axis
|   POWER clamp passes 1 mA (typ) near -0.44 V on its own axis
[GND Clamp]
-1.48V    -532mA     -553.5mA   -510.5mA
-1.098V   -193.8mA   -219.2mA   -170.1mA
-1.05V    -154.3mA   -180.5mA   -130.3mA
-1.002V   -116.5mA   -143.1mA   -92.49mA
-954.6mV  -80.96mA   -107.6mA   -57.97mA
-906.8mV  -49.81mA   -75.15mA   -30.54mA
-859.1mV  -26.26mA   -47.14mA   -16.08mA
-811.4mV  -13.8mA    -26mA      -11.99mA
-715.9mV  -7.644mA   -7.886mA   -9.051mA
-286.4mV  94.85uA    138.5uA    -146.7uA
1.432V    9.834mA    10.85mA    9.154mA
2.959V    27.66mA    31.74mA    24.82mA
[Power Clamp]
-1.459V   516.2mA    533.3mA    495.8mA
-1.125V   217.9mA    239.1mA    195.6mA
-1.077V   177.6mA    199.6mA    154.9mA
-1.03V    138.6mA    161.3mA    115.7mA
-934.1mV  67.24mA    90.63mA    46.94mA
-886.4mV  38.59mA    60.31mA    24.36mA
-838.6mV  19.45mA    35.73mA    13.73mA
-790.9mV  11.13mA    19mA       10.45mA
-695.5mV  6.686mA    6.107mA    7.526mA
-456.8mV  1.257mA    732.6uA    1.832mA
1.405V    -10.14mA   -10.61mA   -9.017mA
2.98V     -29.34mA   -32.76mA   -25.18mA
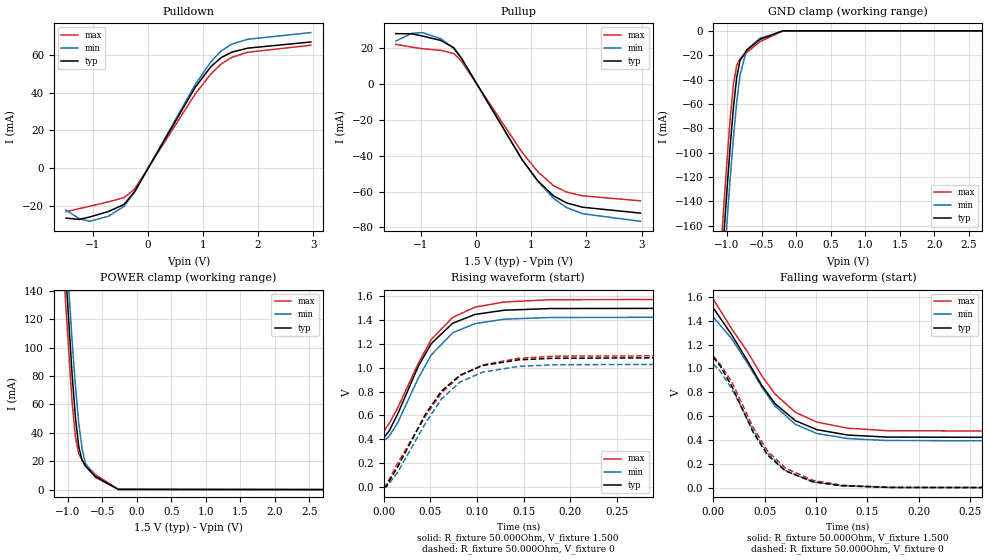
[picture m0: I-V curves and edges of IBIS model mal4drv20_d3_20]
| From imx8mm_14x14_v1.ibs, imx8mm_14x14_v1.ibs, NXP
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[Model] mal4drv20_d3_20
Model_type   I/O
Polarity   Non-Inverting
Enable   Active-High
C_comp   1.686pF   1.679pF   1.694pF
C_comp_pullup   730.495fF   715.918fF   736.638fF
C_comp_pulldown 900.497fF   888.941fF   918.894fF
Vinh = 885.000mV
Vinl = 615.000mV
Vmeas = 750.000mV
Vref = 750.000mV
Rref = 50Ohms
Cref = 0pF
[Model Spec]
Vinh   885.000mV   848.000mV   923.000mV
Vinl   615.000mV   578.000mV   653.000mV
Vmeas   750.000mV   713.000mV   788.000mV
Vref   750.000mV   713.000mV   788.000mV
D_overshoot_ampl_h 0.4 NA   NA
D_overshoot_ampl_l 0.4 NA   NA
D_overshoot_area_l 100.000m NA   NA
D_overshoot_area_h 100.000m NA   NA
|[Receiver Thresholds]
|Vth = 750.000mV
|Vth_min = 713.000mV
|Vth_max = 788.000mV
|Vinh_ac = 135.000mV
|Vinh_dc = 100.000mV
|Vinl_ac = -135.000mV
|Vinl_dc = -100.000mV
|Tslew_ac = 5.000ns
|Threshold_sensitivity = 0.5
|Reference_supply Pullup_ref
[Temperature Range]   25.000   125.000   -40.000
[Voltage Range]   1.500V   1.425V   1.575V
[GND Clamp Reference]   0.00V   0.00V   0.00V
|[C Comp Corner]
|| variable   typ   min   max
|C_comp 1.694pF   1.679pF   1.686pF
|C_comp_pullup 736.638fF   715.918fF   730.495fF
|C_comp_pulldown 900.497fF   918.894fF   888.941fF
[Pulldown Reference]   0.00V   0.00V   0.00V
[POWER Clamp Reference]   1.500V   1.425V   1.575V
[Pullup Reference]   1.500V   1.425V   1.575V
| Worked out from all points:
|   slope of the pulldown table from 0 to 0.225 V, typ, clamps not added: 19.2 ohm
|   slope of the pullup table from 0 to 0.225 V, typ, clamps not added: 18.8 ohm
|   GND clamp passes 1 mA (typ) near -0.33 V on its own axis
|   POWER clamp passes 1 mA (typ) near -0.36 V on its own axis
|   rising waveform, R_fixture 50.000Ohm, V_fixture 1.500: 20-80 % time 43.4ps typ, 43.8ps min, 46.4ps max; typ from 0.412 V to 1.5 V
|   rising waveform, R_fixture 50.000Ohm, V_fixture 0: 20-80 % time 51.8ps typ, 51.2ps min, 57.6ps max; typ from -0.001 V to 1.09 V
|   falling waveform, R_fixture 50.000Ohm, V_fixture 1.500: 20-80 % time 50.6ps typ, 49.8ps min, 54.8ps max; typ from 1.51 V to 0.419 V
|   falling waveform, R_fixture 50.000Ohm, V_fixture 0: 20-80 % time 42.5ps typ, 43.4ps min, 43.9ps max; typ from 1.1 V to 0 V
[GND Clamp]
-1.48V    -561.3mA   -586.2mA   -537.6mA
-1.098V   -211.4mA   -237.2mA   -187.8mA
-1.05V    -170.8mA   -196.9mA   -146.9mA
-1.002V   -131.7mA   -158.1mA   -107.9mA
-954.6mV  -95.09mA   -121.4mA   -72.32mA
-906.8mV  -62.71mA   -87.6mA    -43.76mA
-859.1mV  -37.98mA   -58.38mA   -28.18mA
-811.4mV  -24.36mA   -36.06mA   -22.99mA
-715.9mV  -15.92mA   -15.72mA   -17.85mA
-525mV    -7.111mA   -6.161mA   -8.957mA
-190.9mV  -23.1uA    -47.97uA   -50.29uA
2.959V    76.83nA    922.1nA    33.12nA
[Power Clamp]
-1.459V   545.2mA    565.9mA    523.8mA
-1.125V   236.4mA    258.6mA    214.5mA
-1.077V   194.7mA    217.5mA    172.5mA
-1.03V    154.4mA    177.7mA    132.1mA
-934.1mV  80.47mA    104.2mA    60.83mA
-886.4mV  50.58mA    72.56mA    37.01mA
-838.6mV  30.2mA     46.74mA    25.17mA
-790.9mV  20.67mA    28.82mA    20.7mA
-743.2mV  16.6mA     18.72mA    17.93mA
-600mV    9.237mA    8.612mA    10.65mA
-265.9mV  94.44uA    288.7uA    139uA
2.98V     -218.2nA   -2.479uA   -99.34nA
[Pulldown]
-1.48V    -26.5mA    -22.3mA    -23.1mA
-1.241V   -27.2mA    -26.8mA    -21.5mA
-1.05V    -25.9mA    -28.2mA    -20.2mA
-715.9mV  -23.06mA   -25.56mA   -17.93mA
-429.5mV  -19.3mA    -20.31mA   -15.66mA
-238.6mV  -12.53mA   -12.78mA   -11.19mA
859.1mV   42.71mA    44.16mA    39.16mA
1.145V    53.78mA    56.35mA    49.92mA
1.336V    58.69mA    62.24mA    55.29mA
1.527V    61.5mA     65.79mA    58.76mA
1.814V    63.63mA    68.34mA    61.46mA
2.959V    66.9mA     71.9mA     65.2mA
[Pullup]
-1.459V   28.2mA     24.01mA    22.27mA
-1.173V   28.1mA     28.33mA    20.67mA
-981.8mV  26.9mA     28.79mA    19.82mA
-647.7mV  24.46mA    25.48mA    18.88mA
-409.1mV  20.36mA    20.07mA    17.13mA
-265.9mV  14.42mA    14.2mA     12.75mA
831.8mV   -42.16mA   -42.09mA   -38.03mA
1.118V    -54mA      -54.3mA    -48.94mA
1.405V    -62.42mA   -63.83mA   -56.74mA
1.643V    -66.34mA   -68.98mA   -60.26mA
1.93V     -68.71mA   -72.33mA   -62.34mA
2.98V     -72mA      -76.56mA   -65.14mA
[Ramp]
R_load=50.000Ohm
dV/dt_r   650.550mV/48.500ps  620.069mV/48.500ps  663.000mV/52.500ps
dV/dt_f   650.550mV/48.000ps  620.069mV/47.000ps  663.000mV/50.000ps
[Rising waveform]
R_fixture=50.000Ohm
V_fixture=1.500
V_fixture_min=1.425
V_fixture_max=1.575
0s        412.3mV    383mV      465.4mV
6ps       470.4mV    426.5mV    531.8mV
15ps      609.6mV    537.3mV    661.1mV
37ps      1.009V     909.3mV    1.034V
51ps      1.202V     1.107V     1.236V
74ps      1.373V     1.293V     1.422V
98ps      1.447V     1.37V      1.508V
129ps     1.482V     1.407V     1.551V
178ps     1.496V     1.421V     1.57V
470ps     1.5V       1.425V     1.575V
[Rising waveform]
R_fixture=50.000Ohm
V_fixture=0
0s        -1.448mV   -6.379mV   -5.284mV
3ps       8.762mV    288.1uV    19.16mV
15ps      167.3mV    122.1mV    198.7mV
45ps      613.3mV    538.1mV    596.3mV
62ps      804.7mV    738.2mV    789.4mV
82ps      938.5mV    881mV      933.3mV
106ps     1.019V     963mV      1.023V
144ps     1.066V     1.011V     1.079V
183ps     1.08V      1.025V     1.097V
471ps     1.087V     1.032V     1.105V
[Falling waveform]
R_fixture=50.000Ohm
V_fixture=1.500
V_fixture_min=1.425
V_fixture_max=1.575
0s        1.508V     1.431V     1.581V
18ps      1.282V     1.249V     1.332V
33ps      1.069V     1.049V     1.145V
47ps      861.9mV    848.8mV    942.7mV
60ps      706.6mV    687mV      787mV
80ps      562.5mV    532mV      633mV
101ps     487.2mV    455.3mV    550.5mV
131ps     442.3mV    413mV      499.6mV
169ps     425.4mV    396.5mV    478.8mV
469ps     418.8mV    390.3mV    470.5mV
[Falling waveform]
R_fixture=50.000Ohm
V_fixture=0
0s        1.096V     1.038V     1.106V
7ps       1.018V     975.2mV    1.032V
18ps      852.3mV    831.2mV    888.7mV
39ps      463.2mV    482.1mV    503.6mV
53ps      274.5mV    288.2mV    307.7mV
70ps      143.1mV    146.9mV    166.4mV
97ps      50.67mV    50.65mV    62.97mV
125ps     17.94mV    17.68mV    22.57mV
172ps     3.286mV    3.328mV    4.357mV
469ps     11.59uV    15.19uV    12.88uV
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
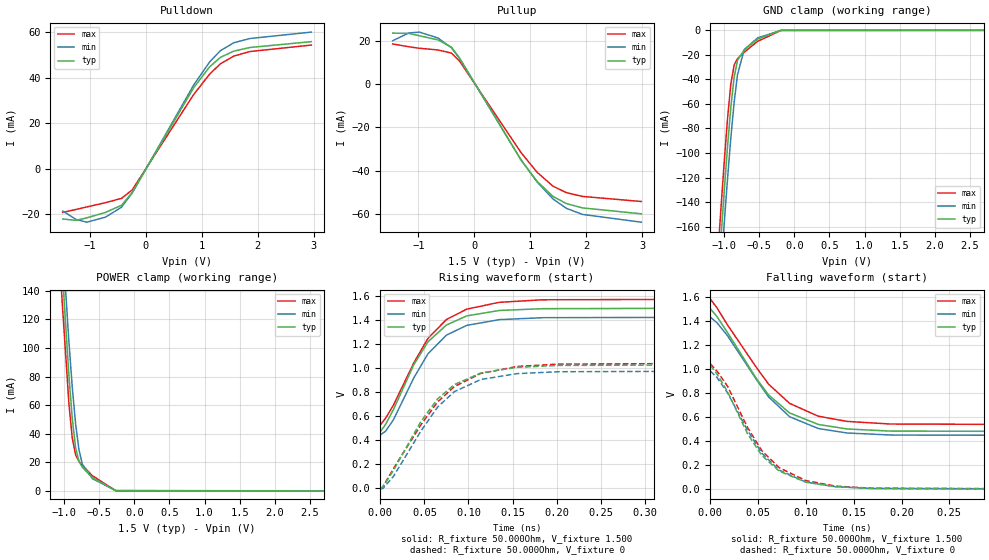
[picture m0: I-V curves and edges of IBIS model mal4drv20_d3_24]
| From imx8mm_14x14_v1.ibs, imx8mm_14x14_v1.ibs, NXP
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[Model] mal4drv20_d3_24
Model_type   I/O
Polarity   Non-Inverting
Enable   Active-High
C_comp   1.686pF   1.679pF   1.694pF
C_comp_pullup   730.495fF   715.918fF   736.638fF
C_comp_pulldown 900.497fF   888.941fF   918.894fF
Vinh = 885.000mV
Vinl = 615.000mV
Vmeas = 750.000mV
Vref = 750.000mV
Rref = 50Ohms
Cref = 0pF
[Model Spec]
Vinh   885.000mV   848.000mV   923.000mV
Vinl   615.000mV   578.000mV   653.000mV
Vmeas   750.000mV   713.000mV   788.000mV
Vref   750.000mV   713.000mV   788.000mV
D_overshoot_ampl_h 0.4 NA   NA
D_overshoot_ampl_l 0.4 NA   NA
D_overshoot_area_l 100.000m NA   NA
D_overshoot_area_h 100.000m NA   NA
|[Receiver Thresholds]
|Vth = 750.000mV
|Vth_min = 713.000mV
|Vth_max = 788.000mV
|Vinh_ac = 135.000mV
|Vinh_dc = 100.000mV
|Vinl_ac = -135.000mV
|Vinl_dc = -100.000mV
|Tslew_ac = 5.000ns
|Threshold_sensitivity = 0.5
|Reference_supply Pullup_ref
[Temperature Range]   25.000   125.000   -40.000
[Voltage Range]   1.500V   1.425V   1.575V
[GND Clamp Reference]   0.00V   0.00V   0.00V
|[C Comp Corner]
|| variable   typ   min   max
|C_comp 1.694pF   1.679pF   1.686pF
|C_comp_pullup 736.638fF   715.918fF   730.495fF
|C_comp_pulldown 900.497fF   918.894fF   888.941fF
[Pulldown Reference]   0.00V   0.00V   0.00V
[POWER Clamp Reference]   1.500V   1.425V   1.575V
[Pullup Reference]   1.500V   1.425V   1.575V
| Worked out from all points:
|   slope of the pulldown table from 0 to 0.225 V, typ, clamps not added: 23 ohm
|   slope of the pullup table from 0 to 0.225 V, typ, clamps not added: 22.5 ohm
|   GND clamp passes 1 mA (typ) near -0.33 V on its own axis
|   POWER clamp passes 1 mA (typ) near -0.36 V on its own axis
|   rising waveform, R_fixture 50.000Ohm, V_fixture 1.500: 20-80 % time 47.1ps typ, 47.2ps min, 49.9ps max; typ from 0.471 V to 1.5 V
|   rising waveform, R_fixture 50.000Ohm, V_fixture 0: 20-80 % time 57.4ps typ, 56.4ps min, 63.4ps max; typ from -0.003 V to 1.03 V
|   falling waveform, R_fixture 50.000Ohm, V_fixture 1.500: 20-80 % time 55.7ps typ, 54.6ps min, 60.2ps max; typ from 1.5 V to 0.477 V
|   falling waveform, R_fixture 50.000Ohm, V_fixture 0: 20-80 % time 45.8ps typ, 46.8ps min, 47.6ps max; typ from 1.03 V to 0 V
[GND Clamp]
-1.48V    -561.3mA   -586.2mA   -537.6mA
-1.098V   -211.4mA   -237.2mA   -187.8mA
-1.05V    -170.8mA   -196.9mA   -146.9mA
-1.002V   -131.7mA   -158.1mA   -107.9mA
-954.6mV  -95.09mA   -121.4mA   -72.32mA
-906.8mV  -62.71mA   -87.6mA    -43.76mA
-859.1mV  -37.98mA   -58.38mA   -28.18mA
-811.4mV  -24.36mA   -36.06mA   -22.99mA
-715.9mV  -15.92mA   -15.72mA   -17.85mA
-525mV    -7.111mA   -6.161mA   -8.957mA
-190.9mV  -23.1uA    -47.97uA   -50.29uA
2.959V    76.83nA    922.1nA    33.12nA
[Power Clamp]
-1.459V   545.2mA    565.9mA    523.8mA
-1.125V   236.4mA    258.6mA    214.5mA
-1.077V   194.7mA    217.5mA    172.5mA
-1.03V    154.4mA    177.7mA    132.1mA
-934.1mV  80.47mA    104.2mA    60.83mA
-886.4mV  50.58mA    72.56mA    37.01mA
-838.6mV  30.2mA     46.74mA    25.17mA
-790.9mV  20.67mA    28.82mA    20.7mA
-743.2mV  16.6mA     18.72mA    17.93mA
-600mV    9.237mA    8.612mA    10.65mA
-265.9mV  94.44uA    288.7uA    139uA
2.98V     -218.2nA   -2.479uA   -99.34nA
[Pulldown]
-1.48V    -22.1mA    -18.6mA    -19.2mA
-1.241V   -22.7mA    -22.3mA    -17.9mA
-1.05V    -21.6mA    -23.5mA    -16.8mA
-715.9mV  -19.2mA    -21.28mA   -14.93mA
-429.5mV  -16.07mA   -16.91mA   -13.04mA
-238.6mV  -10.44mA   -10.64mA   -9.32mA
859.1mV   35.57mA    36.77mA    32.61mA
1.145V    44.8mA     46.93mA    41.58mA
1.336V    48.89mA    51.85mA    46.06mA
1.575V    51.64mA    55.31mA    49.46mA
1.861V    53.22mA    57.17mA    51.45mA
2.959V    55.8mA     60mA       54.3mA
[Pullup]
-1.459V   23.5mA     20mA       18.51mA
-1.173V   23.4mA     23.57mA    17.21mA
-981.8mV  22.3mA     23.99mA    16.52mA
-647.7mV  20.36mA    21.22mA    15.72mA
-409.1mV  16.95mA    16.71mA    14.27mA
-265.9mV  12mA       11.82mA    10.62mA
831.8mV   -35.11mA   -35.06mA   -31.68mA
1.118V    -44.98mA   -45.23mA   -40.76mA
1.405V    -52mA      -53.18mA   -47.26mA
1.643V    -55.27mA   -57.47mA   -50.22mA
1.93V     -57.25mA   -60.27mA   -51.95mA
2.98V     -60mA      -63.86mA   -54.3mA
[Ramp]
R_load=50.000Ohm
dV/dt_r   615.510mV/53.000ps  587.068mV/53.000ps  624.720mV/57.500ps
dV/dt_f   615.510mV/51.500ps  587.069mV/51.500ps  624.720mV/55.000ps
[Rising waveform]
R_fixture=50.000Ohm
V_fixture=1.500
V_fixture_min=1.425
V_fixture_max=1.575
0s        471mV      444.5mV    528mV
6ps       532mV      475.2mV    583.1mV
15ps      656.7mV    572.1mV    693.7mV
38ps      1.029V     919.1mV    1.044V
54ps      1.219V     1.119V     1.248V
75ps      1.359V     1.275V     1.405V
98ps      1.435V     1.356V     1.491V
135ps     1.48V      1.404V     1.548V
184ps     1.495V     1.42V      1.569V
469ps     1.5V       1.425V     1.575V
[Rising waveform]
R_fixture=50.000Ohm
V_fixture=0
0s        -3.337mV   -1.644mV   -6.71mV
3ps       13.81mV    -1.644mV   13.32mV
15ps      151.3mV    100.3mV    165.3mV
46ps      556mV      476mV      528.2mV
65ps      744.6mV    676.5mV    719.1mV
84ps      863.2mV    804.6mV    847.3mV
114ps     960mV      906mV      956.5mV
155ps     1.007V     954.6mV    1.014V
202ps     1.023V     970.3mV    1.034V
470ps     1.029V     976.8mV    1.042V
[Falling waveform]
R_fixture=50.000Ohm
V_fixture=1.500
V_fixture_min=1.425
V_fixture_max=1.575
0s        1.501V     1.431V     1.581V
7ps       1.435V     1.384V     1.508V
18ps      1.303V     1.277V     1.366V
48ps      922.2mV    914.5mV    1.015V
61ps      783.3mV    766.7mV    873.1mV
83ps      633.2mV    602.4mV    713.2mV
113ps     538.2mV    504.3mV    606.8mV
143ps     500.7mV    467.2mV    563.6mV
188ps     483.1mV    450.5mV    541.9mV
469ps     477.3mV    445mV      534.2mV
[Falling waveform]
R_fixture=50.000Ohm
V_fixture=0
0s        1.03V      982.3mV    1.043V
7ps       958.2mV    928.6mV    981.9mV
18ps      810.6mV    802.3mV    857.3mV
39ps      460.7mV    489.4mV    512.3mV
54ps      279.4mV    298.9mV    319.2mV
72ps      150.9mV    158.5mV    178.6mV
100ps     57.52mV    59.24mV    70.97mV
131ps     20.33mV    20.25mV    25.86mV
169ps     5.705mV    5.721mV    7.608mV
469ps     12.55uV    16.54uV    13.53uV
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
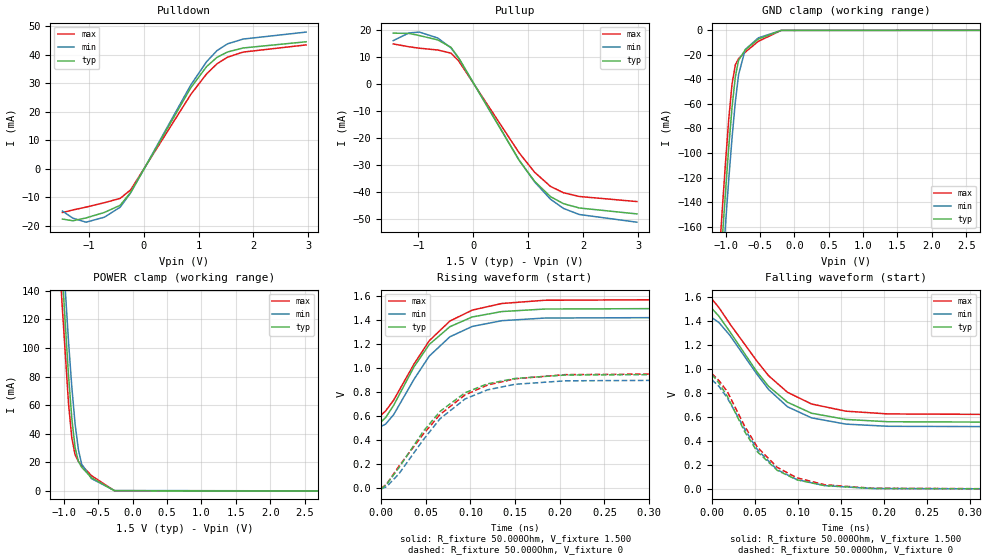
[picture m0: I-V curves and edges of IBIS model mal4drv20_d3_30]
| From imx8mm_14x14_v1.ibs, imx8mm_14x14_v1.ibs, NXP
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[Model] mal4drv20_d3_30
Model_type   I/O
Polarity   Non-Inverting
Enable   Active-High
C_comp   1.686pF   1.679pF   1.694pF
C_comp_pullup   730.495fF   715.918fF   736.638fF
C_comp_pulldown 900.497fF   888.941fF   918.894fF
Vinh = 885.000mV
Vinl = 615.000mV
Vmeas = 750.000mV
Vref = 750.000mV
Rref = 50Ohms
Cref = 0pF
[Model Spec]
Vinh   885.000mV   848.000mV   923.000mV
Vinl   615.000mV   578.000mV   653.000mV
Vmeas   750.000mV   713.000mV   788.000mV
Vref   750.000mV   713.000mV   788.000mV
D_overshoot_ampl_h 0.4 NA   NA
D_overshoot_ampl_l 0.4 NA   NA
D_overshoot_area_l 100.000m NA   NA
D_overshoot_area_h 100.000m NA   NA
|[Receiver Thresholds]
|Vth = 750.000mV
|Vth_min = 713.000mV
|Vth_max = 788.000mV
|Vinh_ac = 135.000mV
|Vinh_dc = 100.000mV
|Vinl_ac = -135.000mV
|Vinl_dc = -100.000mV
|Tslew_ac = 5.000ns
|Threshold_sensitivity = 0.5
|Reference_supply Pullup_ref
[Temperature Range]   25.000   125.000   -40.000
[Voltage Range]   1.500V   1.425V   1.575V
[GND Clamp Reference]   0.00V   0.00V   0.00V
|[C Comp Corner]
|| variable   typ   min   max
|C_comp 1.694pF   1.679pF   1.686pF
|C_comp_pullup 736.638fF   715.918fF   730.495fF
|C_comp_pulldown 900.497fF   918.894fF   888.941fF
[Pulldown Reference]   0.00V   0.00V   0.00V
[POWER Clamp Reference]   1.500V   1.425V   1.575V
[Pullup Reference]   1.500V   1.425V   1.575V
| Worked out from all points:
|   slope of the pulldown table from 0 to 0.225 V, typ, clamps not added: 28.8 ohm
|   slope of the pullup table from 0 to 0.225 V, typ, clamps not added: 28.1 ohm
|   GND clamp passes 1 mA (typ) near -0.33 V on its own axis
|   POWER clamp passes 1 mA (typ) near -0.36 V on its own axis
|   rising waveform, R_fixture 50.000Ohm, V_fixture 1.500: 20-80 % time 52.2ps typ, 52.6ps min, 55.1ps max; typ from 0.554 V to 1.5 V
|   rising waveform, R_fixture 50.000Ohm, V_fixture 0: 20-80 % time 65ps typ, 63.5ps min, 70.9ps max; typ from -0.007 V to 0.952 V
|   falling waveform, R_fixture 50.000Ohm, V_fixture 1.500: 20-80 % time 63ps typ, 60.8ps min, 67.6ps max; typ from 1.5 V to 0.554 V
|   falling waveform, R_fixture 50.000Ohm, V_fixture 0: 20-80 % time 50.7ps typ, 51.7ps min, 52.5ps max; typ from 0.954 V to 0 V
[GND Clamp]
-1.48V    -561.3mA   -586.2mA   -537.6mA
-1.098V   -211.4mA   -237.2mA   -187.8mA
-1.05V    -170.8mA   -196.9mA   -146.9mA
-1.002V   -131.7mA   -158.1mA   -107.9mA
-954.6mV  -95.09mA   -121.4mA   -72.32mA
-906.8mV  -62.71mA   -87.6mA    -43.76mA
-859.1mV  -37.98mA   -58.38mA   -28.18mA
-811.4mV  -24.36mA   -36.06mA   -22.99mA
-715.9mV  -15.92mA   -15.72mA   -17.85mA
-525mV    -7.111mA   -6.161mA   -8.957mA
-190.9mV  -23.1uA    -47.97uA   -50.29uA
2.959V    76.83nA    922.1nA    33.12nA
[Power Clamp]
-1.459V   545.2mA    565.9mA    523.8mA
-1.125V   236.4mA    258.6mA    214.5mA
-1.077V   194.7mA    217.5mA    172.5mA
-1.03V    154.4mA    177.7mA    132.1mA
-934.1mV  80.47mA    104.2mA    60.83mA
-886.4mV  50.58mA    72.56mA    37.01mA
-838.6mV  30.2mA     46.74mA    25.17mA
-790.9mV  20.67mA    28.82mA    20.7mA
-743.2mV  16.6mA     18.72mA    17.93mA
-600mV    9.237mA    8.612mA    10.65mA
-265.9mV  94.44uA    288.7uA    139uA
2.98V     -218.2nA   -2.479uA   -99.34nA
[Pulldown]
-1.48V    -17.7mA    -14.9mA    -15.4mA
-1.289V   -18.3mA    -17.4mA    -14.5mA
-1.05V    -17.3mA    -18.8mA    -13.5mA
-715.9mV  -15.37mA   -17.04mA   -11.95mA
-429.5mV  -12.87mA   -13.54mA   -10.44mA
-238.6mV  -8.358mA   -8.522mA   -7.464mA
859.1mV   28.48mA    29.45mA    26.12mA
1.145V    35.87mA    37.58mA    33.29mA
1.336V    39.13mA    41.51mA    36.87mA
1.527V    41.01mA    43.87mA    39.18mA
1.814V    42.42mA    45.56mA    40.98mA
2.959V    44.6mA     48mA       43.5mA
[Pullup]
-1.459V   18.8mA     16.04mA    14.81mA
-1.173V   18.7mA     18.87mA    13.76mA
-981.8mV  17.9mA     19.19mA    13.23mA
-647.7mV  16.3mA     16.99mA    12.57mA
-409.1mV  13.57mA    13.38mA    11.42mA
-265.9mV  9.612mA    9.465mA    8.505mA
831.8mV   -28.12mA   -28.07mA   -25.37mA
1.118V    -36.01mA   -36.22mA   -32.64mA
1.405V    -41.62mA   -42.57mA   -37.83mA
1.643V    -44.23mA   -45.99mA   -40.18mA
1.93V     -45.81mA   -48.22mA   -41.56mA
2.98V     -48mA      -51.06mA   -43.44mA
[Ramp]
R_load=50.000Ohm
dV/dt_r   569.550mV/60.000ps  543.748mV/58.500ps  574.950mV/64.000ps
dV/dt_f   569.550mV/58.000ps  543.749mV/57.000ps  574.950mV/60.500ps
[Rising waveform]
R_fixture=50.000Ohm
V_fixture=1.500
V_fixture_min=1.425
V_fixture_max=1.575
0s        553.8mV    516.1mV    609.3mV
5ps       587.8mV    534mV      643.5mV
14ps      690mV      612.3mV    733.2mV
37ps      1.013V     909.2mV    1.036V
54ps      1.198V     1.101V     1.229V
77ps      1.345V     1.261V     1.392V
102ps     1.426V     1.347V     1.483V
135ps     1.471V     1.395V     1.538V
183ps     1.492V     1.417V     1.565V
470ps     1.5V       1.425V     1.575V
[Rising waveform]
R_fixture=50.000Ohm
V_fixture=0
0s        -6.804mV   -3.804mV   -1.164mV
6ps       31.04mV    12.45mV    33.26mV
20ps      172.3mV    121mV      185.2mV
47ps      471.8mV    401.8mV    448.6mV
66ps      640.2mV    579.3mV    614.9mV
94ps      795.5mV    743.8mV    777.6mV
119ps     869.5mV    819.4mV    859.2mV
150ps     914.6mV    865.9mV    911.6mV
206ps     942.8mV    894.7mV    946.2mV
470ps     952.5mV    904.2mV    958.5mV
[Falling waveform]
R_fixture=50.000Ohm
V_fixture=1.500
V_fixture_min=1.425
V_fixture_max=1.575
0s        1.502V     1.426V     1.581V
8ps       1.44V      1.387V     1.512V
21ps      1.309V     1.279V     1.374V
52ps      979.5mV    960.7mV    1.069V
66ps      855.1mV    828.7mV    943.5mV
88ps      722.9mV    685.3mV    805.8mV
116ps     631.5mV    593.1mV    708.3mV
156ps     579.9mV    541mV      648.6mV
205ps     560.8mV    522.9mV    625.7mV
469ps     554mV      516.8mV    617.1mV
[Falling waveform]
R_fixture=50.000Ohm
V_fixture=0
0s        953.7mV    909.4mV    961.1mV
8ps       885.4mV    856.9mV    904.7mV
18ps      771.1mV    758.7mV    810.6mV
38ps      480.5mV    501.3mV    525.3mV
53ps      310.7mV    327.9mV    348.7mV
76ps      156.7mV    161.9mV    181.7mV
99ps      77.73mV    79.32mV    94.28mV
131ps     29.67mV    29.89mV    37.08mV
187ps     5.498mV    5.314mV    7.386mV
469ps     14.06uV    18.53uV    14.84uV
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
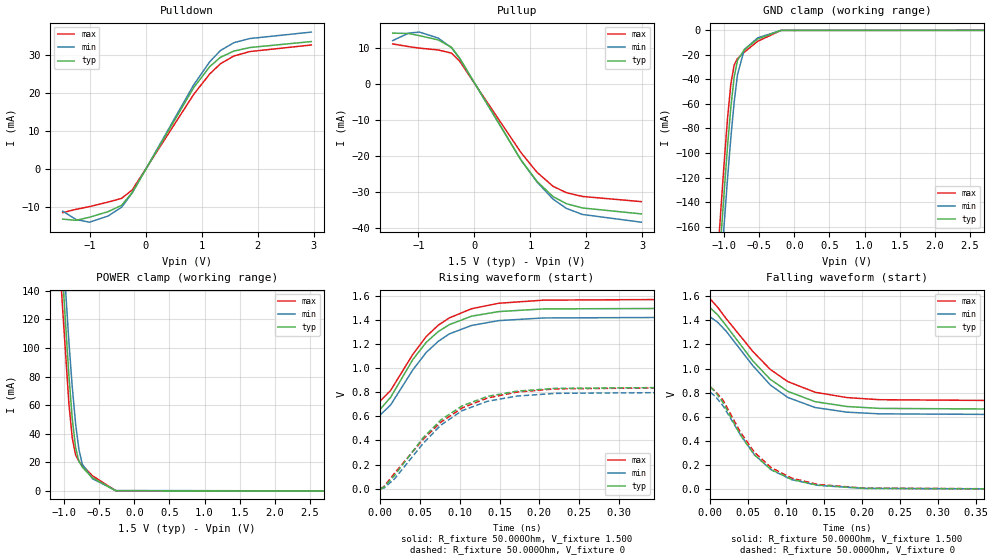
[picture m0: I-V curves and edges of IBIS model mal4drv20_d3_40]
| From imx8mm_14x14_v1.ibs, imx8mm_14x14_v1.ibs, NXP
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[Model] mal4drv20_d3_40
Model_type   I/O
Polarity   Non-Inverting
Enable   Active-High
C_comp   1.686pF   1.679pF   1.694pF
C_comp_pullup   730.495fF   715.918fF   736.638fF
C_comp_pulldown 900.497fF   888.941fF   918.894fF
Vinh = 885.000mV
Vinl = 615.000mV
Vmeas = 750.000mV
Vref = 750.000mV
Rref = 50Ohms
Cref = 0pF
[Model Spec]
Vinh   885.000mV   848.000mV   923.000mV
Vinl   615.000mV   578.000mV   653.000mV
Vmeas   750.000mV   713.000mV   788.000mV
Vref   750.000mV   713.000mV   788.000mV
D_overshoot_ampl_h 0.4 NA   NA
D_overshoot_ampl_l 0.4 NA   NA
D_overshoot_area_l 100.000m NA   NA
D_overshoot_area_h 100.000m NA   NA
|[Receiver Thresholds]
|Vth = 750.000mV
|Vth_min = 713.000mV
|Vth_max = 788.000mV
|Vinh_ac = 135.000mV
|Vinh_dc = 100.000mV
|Vinl_ac = -135.000mV
|Vinl_dc = -100.000mV
|Tslew_ac = 5.000ns
|Threshold_sensitivity = 0.5
|Reference_supply Pullup_ref
[Temperature Range]   25.000   125.000   -40.000
[Voltage Range]   1.500V   1.425V   1.575V
[GND Clamp Reference]   0.00V   0.00V   0.00V
|[C Comp Corner]
|| variable   typ   min   max
|C_comp 1.694pF   1.679pF   1.686pF
|C_comp_pullup 736.638fF   715.918fF   730.495fF
|C_comp_pulldown 900.497fF   918.894fF   888.941fF
[Pulldown Reference]   0.00V   0.00V   0.00V
[POWER Clamp Reference]   1.500V   1.425V   1.575V
[Pullup Reference]   1.500V   1.425V   1.575V
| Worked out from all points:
|   slope of the pulldown table from 0 to 0.225 V, typ, clamps not added: 38.3 ohm
|   slope of the pullup table from 0 to 0.225 V, typ, clamps not added: 37.5 ohm
|   GND clamp passes 1 mA (typ) near -0.33 V on its own axis
|   POWER clamp passes 1 mA (typ) near -0.36 V on its own axis
|   rising waveform, R_fixture 50.000Ohm, V_fixture 1.500: 20-80 % time 59.6ps typ, 60.1ps min, 62.2ps max; typ from 0.66 V to 1.5 V
|   rising waveform, R_fixture 50.000Ohm, V_fixture 0: 20-80 % time 75.1ps typ, 73.1ps min, 81.9ps max; typ from -0.003 V to 0.846 V
|   falling waveform, R_fixture 50.000Ohm, V_fixture 1.500: 20-80 % time 73.3ps typ, 70.4ps min, 77.9ps max; typ from 1.5 V to 0.661 V
|   falling waveform, R_fixture 50.000Ohm, V_fixture 0: 20-80 % time 58.1ps typ, 58.2ps min, 60ps max; typ from 0.848 V to 0 V
[GND Clamp]
-1.48V    -561.3mA   -586.2mA   -537.6mA
-1.098V   -211.4mA   -237.2mA   -187.8mA
-1.05V    -170.8mA   -196.9mA   -146.9mA
-1.002V   -131.7mA   -158.1mA   -107.9mA
-954.6mV  -95.09mA   -121.4mA   -72.32mA
-906.8mV  -62.71mA   -87.6mA    -43.76mA
-859.1mV  -37.98mA   -58.38mA   -28.18mA
-811.4mV  -24.36mA   -36.06mA   -22.99mA
-715.9mV  -15.92mA   -15.72mA   -17.85mA
-525mV    -7.111mA   -6.161mA   -8.957mA
-190.9mV  -23.1uA    -47.97uA   -50.29uA
2.959V    76.83nA    922.1nA    33.12nA
[Power Clamp]
-1.459V   545.2mA    565.9mA    523.8mA
-1.125V   236.4mA    258.6mA    214.5mA
-1.077V   194.7mA    217.5mA    172.5mA
-1.03V    154.4mA    177.7mA    132.1mA
-934.1mV  80.47mA    104.2mA    60.83mA
-886.4mV  50.58mA    72.56mA    37.01mA
-838.6mV  30.2mA     46.74mA    25.17mA
-790.9mV  20.67mA    28.82mA    20.7mA
-743.2mV  16.6mA     18.72mA    17.93mA
-600mV    9.237mA    8.612mA    10.65mA
-265.9mV  94.44uA    288.7uA    139uA
2.98V     -218.2nA   -2.479uA   -99.34nA
[Pulldown]
-1.48V    -13.3mA    -11.2mA    -11.6mA
-1.241V   -13.6mA    -13.4mA    -10.7mA
-1.002V   -12.8mA    -14.1mA    -10mA
-668.2mV  -11.31mA   -12.46mA   -8.8mA
-429.5mV  -9.656mA   -10.16mA   -7.829mA
-238.6mV  -6.269mA   -6.392mA   -5.598mA
859.1mV   21.36mA    22.09mA    19.59mA
1.145V    26.9mA     28.18mA    24.97mA
1.336V    29.35mA    31.13mA    27.65mA
1.575V    30.99mA    33.2mA     29.69mA
1.861V    31.93mA    34.3mA     30.87mA
2.959V    33.5mA     36mA       32.6mA
[Pullup]
-1.459V   14.1mA     12.03mA    11.11mA
-1.173V   14mA       14.11mA    10.36mA
-981.8mV  13.4mA     14.39mA    9.94mA
-647.7mV  12.23mA    12.74mA    9.439mA
-409.1mV  10.18mA    10.04mA    8.568mA
-265.9mV  7.21mA     7.102mA    6.38mA
831.8mV   -21.09mA   -21.06mA   -19.02mA
1.118V    -27.01mA   -27.16mA   -24.48mA
1.405V    -31.22mA   -31.93mA   -28.37mA
1.643V    -33.18mA   -34.49mA   -30.13mA
1.93V     -34.36mA   -36.16mA   -31.17mA
2.98V     -36mA      -38.3mA    -32.6mA
[Ramp]
R_load=50.000Ohm
dV/dt_r   505.500mV/68.500ps  483.478mV/67.500ps  506.460mV/73.000ps
dV/dt_f   505.500mV/66.500ps  483.478mV/66.000ps  506.460mV/70.000ps
[Rising waveform]
R_fixture=50.000Ohm
V_fixture=1.500
V_fixture_min=1.425
V_fixture_max=1.575
0s        660.3mV    612.7mV    728.4mV
13ps      758.4mV    694.7mV    815.6mV
41ps      1.073V     987.1mV    1.116V
58ps      1.217V     1.133V     1.265V
73ps      1.305V     1.224V     1.358V
87ps      1.363V     1.286V     1.419V
115ps     1.433V     1.356V     1.495V
149ps     1.471V     1.396V     1.54V
205ps     1.493V     1.418V     1.566V
470ps     1.5V       1.425V     1.575V
[Rising waveform]
R_fixture=50.000Ohm
V_fixture=0
0s        -3.258mV   -2.239mV   -4.684mV
5ps       12.85mV    6.551mV    20.28mV
18ps      110.1mV    81.31mV    128.2mV
54ps      423.5mV    376.2mV    409.9mV
76ps      569.5mV    526.7mV    551.1mV
103ps     687.7mV    648mV      670.4mV
135ps     766.5mV    725.9mV    753.3mV
172ps     810mV      769mV      802.2mV
220ps     832.9mV    791.3mV    828.9mV
471ps     845.7mV    803.2mV    844.2mV
[Falling waveform]
R_fixture=50.000Ohm
V_fixture=1.500
V_fixture_min=1.425
V_fixture_max=1.575
0s        1.503V     1.427V     1.576V
10ps      1.443V     1.382V     1.506V
21ps      1.355V     1.309V     1.413V
56ps      1.063V     1.024V     1.142V
79ps      910.5mV    863.9mV    992.6mV
102ps     810.9mV    760.5mV    891.8mV
138ps     725.3mV    676.9mV    803.4mV
180ps     685.2mV    638.3mV    759.2mV
223ps     669.6mV    624.4mV    741.6mV
469ps     660.8mV    616.7mV    731.2mV
[Falling waveform]
R_fixture=50.000Ohm
V_fixture=0
0s        847.7mV    803.6mV    848.5mV
7ps       803mV      767.2mV    808.6mV
17ps      715.3mV    689mV      735.9mV
39ps      455mV      458.1mV    479.6mV
58ps      284.3mV    286.4mV    306.3mV
80ps      163mV      161mV      179.6mV
107ps     80.57mV    79.74mV    92.05mV
141ps     33.54mV    32.19mV    39.46mV
202ps     6.828mV    6.383mV    8.599mV
469ps     17.26uV    22.86uV    21.9uV
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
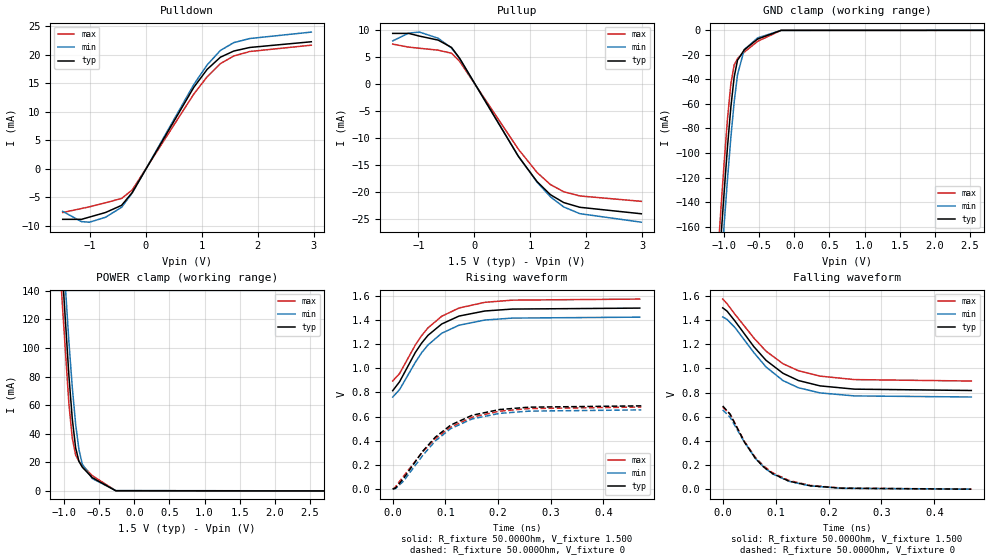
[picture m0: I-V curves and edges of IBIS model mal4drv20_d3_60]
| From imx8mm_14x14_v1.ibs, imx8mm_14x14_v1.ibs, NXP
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[Model] mal4drv20_d3_60
Model_type   I/O
Polarity   Non-Inverting
Enable   Active-High
C_comp   1.686pF   1.679pF   1.694pF
C_comp_pullup   730.495fF   715.918fF   736.638fF
C_comp_pulldown 900.497fF   888.941fF   918.894fF
Vinh = 885.000mV
Vinl = 615.000mV
Vmeas = 750.000mV
Vref = 750.000mV
Rref = 50Ohms
Cref = 0pF
[Model Spec]
Vinh   885.000mV   848.000mV   923.000mV
Vinl   615.000mV   578.000mV   653.000mV
Vmeas   750.000mV   713.000mV   788.000mV
Vref   750.000mV   713.000mV   788.000mV
D_overshoot_ampl_h 0.4 NA   NA
D_overshoot_ampl_l 0.4 NA   NA
D_overshoot_area_l 100.000m NA   NA
D_overshoot_area_h 100.000m NA   NA
|[Receiver Thresholds]
|Vth = 750.000mV
|Vth_min = 713.000mV
|Vth_max = 788.000mV
|Vinh_ac = 135.000mV
|Vinh_dc = 100.000mV
|Vinl_ac = -135.000mV
|Vinl_dc = -100.000mV
|Tslew_ac = 5.000ns
|Threshold_sensitivity = 0.5
|Reference_supply Pullup_ref
[Temperature Range]   25.000   125.000   -40.000
[Voltage Range]   1.500V   1.425V   1.575V
[GND Clamp Reference]   0.00V   0.00V   0.00V
|[C Comp Corner]
|| variable   typ   min   max
|C_comp 1.694pF   1.679pF   1.686pF
|C_comp_pullup 736.638fF   715.918fF   730.495fF
|C_comp_pulldown 900.497fF   918.894fF   888.941fF
[Pulldown Reference]   0.00V   0.00V   0.00V
[POWER Clamp Reference]   1.500V   1.425V   1.575V
[Pullup Reference]   1.500V   1.425V   1.575V
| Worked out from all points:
|   slope of the pulldown table from 0 to 0.225 V, typ, clamps not added: 57.4 ohm
|   slope of the pullup table from 0 to 0.225 V, typ, clamps not added: 56.1 ohm
|   GND clamp passes 1 mA (typ) near -0.33 V on its own axis
|   POWER clamp passes 1 mA (typ) near -0.36 V on its own axis
|   rising waveform, R_fixture 50.000Ohm, V_fixture 1.500: 20-80 % time 70.4ps typ, 70.8ps min, 72.8ps max; typ from 0.814 V to 1.5 V
|   rising waveform, R_fixture 50.000Ohm, V_fixture 0: 20-80 % time 90ps typ, 87.3ps min, 97.1ps max; typ from -0.002 V to 0.689 V
|   falling waveform, R_fixture 50.000Ohm, V_fixture 1.500: 20-80 % time 88.2ps typ, 84ps min, 92ps max; typ from 1.5 V to 0.818 V
|   falling waveform, R_fixture 50.000Ohm, V_fixture 0: 20-80 % time 68.7ps typ, 68.7ps min, 70.5ps max; typ from 0.689 V to 0 V
[GND Clamp]
-1.48V    -561.3mA   -586.2mA   -537.6mA
-1.098V   -211.4mA   -237.2mA   -187.8mA
-1.05V    -170.8mA   -196.9mA   -146.9mA
-1.002V   -131.7mA   -158.1mA   -107.9mA
-954.6mV  -95.09mA   -121.4mA   -72.32mA
-906.8mV  -62.71mA   -87.6mA    -43.76mA
-859.1mV  -37.98mA   -58.38mA   -28.18mA
-811.4mV  -24.36mA   -36.06mA   -22.99mA
-715.9mV  -15.92mA   -15.72mA   -17.85mA
-525mV    -7.111mA   -6.161mA   -8.957mA
-190.9mV  -23.1uA    -47.97uA   -50.29uA
2.959V    76.83nA    922.1nA    33.12nA
[Power Clamp]
-1.459V   545.2mA    565.9mA    523.8mA
-1.125V   236.4mA    258.6mA    214.5mA
-1.077V   194.7mA    217.5mA    172.5mA
-1.03V    154.4mA    177.7mA    132.1mA
-934.1mV  80.47mA    104.2mA    60.83mA
-886.4mV  50.58mA    72.56mA    37.01mA
-838.6mV  30.2mA     46.74mA    25.17mA
-790.9mV  20.67mA    28.82mA    20.7mA
-743.2mV  16.6mA     18.72mA    17.93mA
-600mV    9.237mA    8.612mA    10.65mA
-265.9mV  94.44uA    288.7uA    139uA
2.98V     -218.2nA   -2.479uA   -99.34nA
[Pulldown]
-1.48V    -8.9mA     -7.5mA     -7.7mA
-1.145V   -8.9mA     -9.3mA     -7mA
-1.002V   -8.5mA     -9.4mA     -6.7mA
-715.9mV  -7.7mA     -8.54mA    -5.99mA
-429.5mV  -6.446mA   -6.785mA   -5.229mA
-238.6mV  -4.189mA   -4.272mA   -3.74mA
859.1mV   14.27mA    14.76mA    13.09mA
1.098V    17.44mA    18.22mA    16.14mA
1.336V    19.59mA    20.78mA    18.46mA
1.575V    20.67mA    22.15mA    19.8mA
1.861V    21.3mA     22.87mA    20.59mA
2.959V    22.3mA     24mA       21.7mA
[Pullup]
-1.459V   9.4mA      8.014mA    7.414mA
-1.173V   9.4mA      9.457mA    6.857mA
-981.8mV  8.9mA      9.643mA    6.649mA
-647.7mV  8.16mA     8.508mA    6.297mA
-409.1mV  6.8mA      6.702mA    5.721mA
-265.9mV  4.819mA    4.745mA    4.262mA
784.1mV   -13.36mA   -13.33mA   -12.04mA
1.118V    -18.04mA   -18.14mA   -16.35mA
1.357V    -20.47mA   -20.86mA   -18.59mA
1.595V    -21.93mA   -22.74mA   -19.92mA
1.882V    -22.8mA    -23.98mA   -20.7mA
2.98V     -24mA      -25.56mA   -21.7mA
[Ramp]
R_load=50.000Ohm
dV/dt_r   411.420mV/81.000ps  395.067mV/79.500ps  407.520mV/86.000ps
dV/dt_f   411.420mV/79.500ps  395.068mV/77.000ps  407.520mV/82.500ps
[Rising waveform]
R_fixture=50.000Ohm
V_fixture=1.500
V_fixture_min=1.425
V_fixture_max=1.575
0s        814.3mV    761.5mV    895.3mV
13ps      888.6mV    823.4mV    956.8mV
43ps      1.132V     1.05V      1.194V
55ps      1.21V      1.13V      1.272V
67ps      1.274V     1.194V     1.336V
93ps      1.368V     1.291V     1.432V
126ps     1.434V     1.358V     1.501V
175ps     1.476V     1.401V     1.548V
227ps     1.492V     1.417V     1.566V
469ps     1.5V       1.425V     1.575V
[Rising waveform]
R_fixture=50.000Ohm
V_fixture=0
0s        -1.925mV   -1.463mV   -2.93mV
5ps       5.011mV    1.347mV    14.5mV
20ps      82.67mV    61.47mV    102.1mV
57ps      312.4mV    277.4mV    307.6mV
81ps      429.1mV    398mV      417.1mV
110ps     528.8mV    499.2mV    512.5mV
151ps     610.7mV    580.5mV    594.1mV
203ps     658.1mV    626.3mV    644.6mV
259ps     677.7mV    644.8mV    666.1mV
472ps     688.6mV    655.1mV    678.8mV
[Falling waveform]
R_fixture=50.000Ohm
V_fixture=1.500
V_fixture_min=1.425
V_fixture_max=1.575
0s        1.502V     1.427V     1.575V
8ps       1.476V     1.407V     1.538V
23ps      1.394V     1.34V      1.45V
59ps      1.18V      1.131V     1.252V
82ps      1.067V     1.012V     1.143V
114ps     959.9mV    899.6mV    1.039V
143ps     900.3mV    840.4mV    981.7mV
184ps     855.7mV    797.6mV    936.7mV
249ps     828.7mV    772.7mV    907.8mV
470ps     817.5mV    763.5mV    895.9mV
[Falling waveform]
R_fixture=50.000Ohm
V_fixture=0
0s        689.3mV    657.1mV    679.9mV
14ps      620.6mV    594.7mV    621.9mV
41ps      390.4mV    390mV      396.7mV
62ps      254mV      253.4mV    261.9mV
78ps      181.5mV    180.6mV    189.9mV
94ps      130.2mV    127.2mV    136.6mV
125ps     66.71mV    65.57mV    72.41mV
165ps     28.31mV    27.08mV    31.57mV
226ps     7.731mV    7.152mV    8.817mV
470ps     44.7uV     51.26uV    59.37uV
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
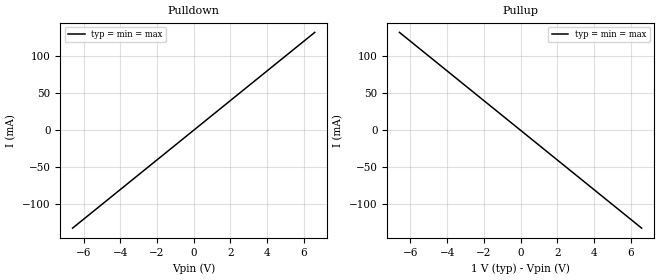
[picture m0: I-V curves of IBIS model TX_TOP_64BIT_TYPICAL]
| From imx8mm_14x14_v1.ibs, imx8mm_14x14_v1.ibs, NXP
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[Model] TX_TOP_64BIT_TYPICAL
Model_type Output
C_comp 0p 0p 0p
Cref = 0
Vref = 0.5
Rref = 50
Vmeas = 0.5
[Temperature_Range] 25 125 0
[Voltage Range] 1.0 1.0 1.0
[Algorithmic Model]
Executable Windows_cl16.00.40219.01_64 TX_TOP_64BIT_TYPICAL_x64.dll TX_TOP_64BIT_TYPICAL.ami
Executable Windows_cl16.00.40219.01_32 TX_TOP_64BIT_TYPICAL.dll TX_TOP_64BIT_TYPICAL.ami
[End Algorithmic Model]
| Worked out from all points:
|   slope of the pulldown table from 0 to 0.15 V, typ, clamps not added: 50 ohm
|   slope of the pullup table from 0 to 0.15 V, typ, clamps not added: 50 ohm
[Pulldown]
-6.6V     -132mA     -132mA     -132mA
0V        0A         0A         0A
6.6V      132mA      132mA      132mA
[Pullup]
-6.6V     132mA      132mA      132mA
0V        0A         0A         0A
6.6V      -132mA     -132mA     -132mA
[GND Clamp]
-6.6V     0A         0A         0A
0V        0A         0A         0A
6.6V      0A         0A         0A
[Power Clamp]
-6.6V     0A         0A         0A
0V        0A         0A         0A
6.6V      0A         0A         0A
[Ramp]
dV/dt_r 0.3/1.5p 0.3/1.5p 0.3/1.5p
dV/dt_f 0.3/1.5p 0.3/1.5p 0.3/1.5p
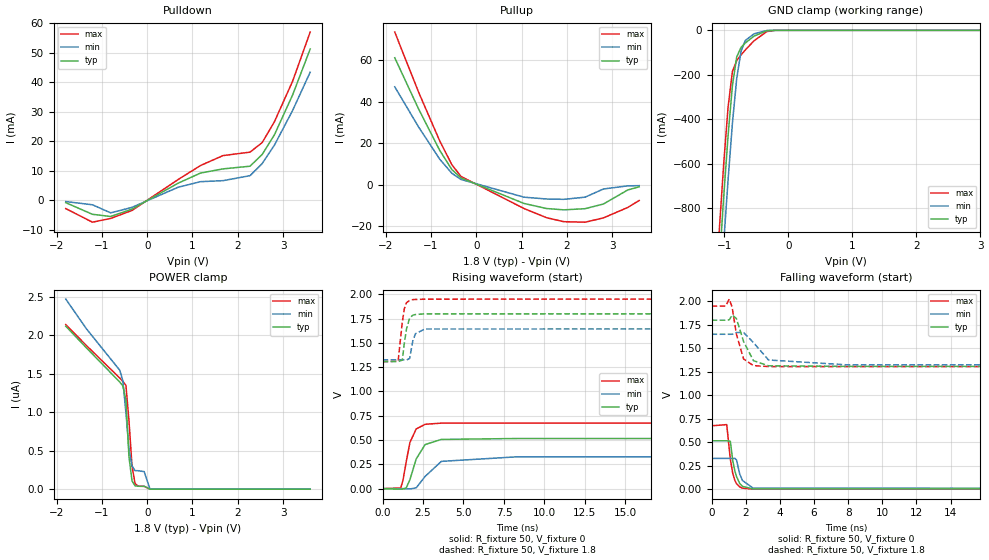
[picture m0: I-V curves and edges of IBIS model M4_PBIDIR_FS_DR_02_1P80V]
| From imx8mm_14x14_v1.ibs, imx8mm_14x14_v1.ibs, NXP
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[Model] M4_PBIDIR_FS_DR_02_1P80V
Model_type I/O
Vinl  =  0.54
Vinh  =  1.26
Vmeas =  0.9
| Capacitance   typ   min   max
C_comp   4.70306747824e-12   4.592798992e-12   4.8293865999e-12
| Variables   typ   min   max
[GND Clamp Reference]   0   0   0
[POWER Clamp Reference]   1.8   1.65   1.95
[Pulldown Reference]   0   0   0
[Pullup Reference]   1.8   1.65   1.95
[Temperature Range]   25   125   -40
[Voltage Range]   1.8   1.65   1.95
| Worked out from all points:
|   slope of the pulldown table from 0 to 0.27 V, typ, clamps not added: 114 ohm
|   slope of the pullup table from 0 to 0.27 V, typ, clamps not added: 108 ohm
|   GND clamp passes 1 mA (typ) near -0.31 V on its own axis
|   falling waveform, R_fixture 50, V_fixture 0: 20-80 % time 358ps typ, 391ps min, 325ps max; typ from 0.516 V to 0 V
|   falling waveform, R_fixture 50, V_fixture 1.8: 20-80 % time 602ps typ, 822ps min, 438ps max; typ from 1.8 V to 1.31 V
|   rising waveform, R_fixture 50, V_fixture 0: 20-80 % time 681ps typ, 1.01ns min, 495ps max; typ from 0 V to 0.516 V
|   rising waveform, R_fixture 50, V_fixture 1.8: 20-80 % time 267ps typ, 269ps min, 273ps max; typ from 1.31 V to 1.8 V
[GND Clamp]
| Voltage   I(typ)   I(min)   I(max)
-1.8V     -4.612A    -4.803A    -4.458A
-1.076V   -1.039A    -1.25A     -883.5mA
-1.009V   -742.9mA   -951.7mA   -595.3mA
-941.4mV  -471.2mA   -670.1mA   -343.8mA
-874.1mV  -248.1mA   -417.3mA   -184.9mA
-806.9mV  -119.4mA   -215.9mA   -135.7mA
-739.7mV  -76.88mA   -94.46mA   -110.7mA
-672.4mV  -56.93mA   -45.5mA    -88.16mA
-537.9mV  -26.26mA   -15.72mA   -47.3mA
-336.2mV  -1.51mA    -830.1uA   -5.564mA
-201.7mV  -19.77uA   -26.41uA   -67.32uA
3.6V      0A         0A         0A
[POWER Clamp]
| Voltage   I(typ)   I(min)   I(max)
-1.8V     2.118uA    2.47uA     2.138uA
-1.345V   1.837uA    2.085uA    1.867uA
-605.2mV  1.391uA    1.544uA    1.443uA
-537.9mV  1.341uA    1.406uA    1.4uA
-470.7mV  1.162uA    995nA      1.35uA
-403.4mV  420.6nA    524.2nA    889.2nA
-336.2mV  108.1nA    302.3nA    302.3nA
-269mV    43.69nA    240.7nA    73.26nA
-201.7mV  37.94nA    239.7nA    38.35nA
-67.24mV  37.94nA    228nA      35.87nA
62.07mV   0A         0A         0A
3.6V      0A         0A         0A
[Pulldown]
| Voltage   I(typ)   I(min)   I(max)
-1.8V     -788.6uA   -417.3uA   -2.803mA
-1.21V    -4.739mA   -1.506mA   -7.414mA
-806.9mV  -5.474mA   -4.252mA   -6.137mA
-336.2mV  -2.968mA   -2.376mA   -3.427mA
682.8mV   5.815mA    4.433mA    7.057mA
1.179V    9.262mA    6.329mA    11.82mA
1.676V    10.67mA    6.675mA    15.18mA
2.271V    11.57mA    8.363mA    16.34mA
2.54V     15.56mA    12.48mA    19.59mA
2.809V    22.19mA    18.69mA    26.62mA
3.212V    35.73mA    30.48mA    40.4mA
3.6V      51.3mA     43.45mA    57.06mA
[Pullup]
| Voltage   I(typ)   I(min)   I(max)
-1.8V     61.03mA    47.08mA    73.37mA
-1.278V   36.63mA    27.94mA    44.73mA
-806.9mV  16.55mA    12.33mA    21.11mA
-537.9mV  7.322mA    5.527mA    9.629mA
-336.2mV  3.299mA    2.579mA    4.021mA
1.055V    -8.936mA   -5.931mA   -11.37mA
1.552V    -11.37mA   -6.797mA   -15.78mA
1.934V    -12.01mA   -6.964mA   -17.7mA
2.405V    -11.45mA   -5.924mA   -17.94mA
2.809V    -9.212mA   -1.998mA   -15.89mA
3.347V    -2.466mA   -486.9uA   -10.87mA
3.6V      -953.7uA   -386.7uA   -7.509mA
[Ramp]
dV/dt_r   0.309326/0.68132n  0.196491/1.01041n  0.404914/0.49542n
dV/dt_f   0.295503/0.60235n  0.195154/0.822279n  0.38654/0.438082n
R_load = 50
[Falling Waveform]
R_fixture = 50
V_fixture = 0
V_fixture_min = 0
V_fixture_max = 0
| Time   V(typ)   V(min)   V(max)
0s        515.5mV    327.5mV    674.9mV
888ps     515.6mV    327.5mV    687.8mV
1.099ns   510.1mV    327.5mV    319.8mV
1.239ns   305.2mV    327.5mV    171.5mV
1.368ns   191.3mV    327.9mV    91.82mV
1.461ns   135.6mV    310.8mV    58.55mV
1.647ns   61.02mV    163.1mV    23.68mV
1.81ns    29.9mV     92.52mV    10.71mV
2.44ns    1.951mV    9.963mV    499uV
333.3ns   180.9nV    287.8nV    236.7nV
[Falling Waveform]
R_fixture = 50
V_fixture = 1.8
V_fixture_min = 1.65
V_fixture_max = 1.95
| Time   V(typ)   V(min)   V(max)
0s        1.8V       1.65V      1.95V
818.5ps   1.8V       1.65V      1.95V
1.039ns   1.804V     1.65V      2.025V
1.209ns   1.855V     1.65V      1.935V
1.456ns   1.817V     1.669V     1.65V
1.876ns   1.573V     1.669V     1.387V
2.451ns   1.369V     1.562V     1.316V
3.337ns   1.314V     1.376V     1.306V
7.877ns   1.308V     1.325V     1.306V
333.3ns   1.307V     1.325V     1.306V
[Rising Waveform]
R_fixture = 50
V_fixture = 0
V_fixture_min = 0
V_fixture_max = 0
| Time   V(typ)   V(min)   V(max)
0s        174.7nV    491.6nV    228.1nV
1.122ns   -5.475mV   -10.02uV   6.897mV
1.262ns   -3.218mV   -140.1uV   84.82mV
1.461ns   6.855mV    -1.51mV    275.7mV
1.693ns   92.76mV    -2.994mV   475.7mV
2.078ns   305.4mV    7.902mV    614mV
2.63ns    453.4mV    125.8mV    661.7mV
3.633ns   506.4mV    280.4mV    674mV
8.305ns   515.5mV    327.3mV    674.8mV
333.3ns   515.5mV    327.5mV    674.9mV
[Rising Waveform]
R_fixture = 50
V_fixture = 1.8
V_fixture_min = 1.65
V_fixture_max = 1.95
| Time   V(typ)   V(min)   V(max)
0s        1.307V     1.325V     1.306V
962.5ps   1.307V     1.325V     1.311V
1.219ns   1.322V     1.325V     1.711V
1.344ns   1.494V     1.324V     1.85V
1.479ns   1.642V     1.322V     1.913V
1.675ns   1.755V     1.34V      1.937V
1.868ns   1.784V     1.518V     1.944V
2.031ns   1.791V     1.593V     1.946V
2.609ns   1.798V     1.642V     1.949V
333.3ns   1.8V       1.65V      1.95V
[Add Submodel]
| Submodel Name Mode
M4_PBIDIR_FS_DR_02_1P80V_T All
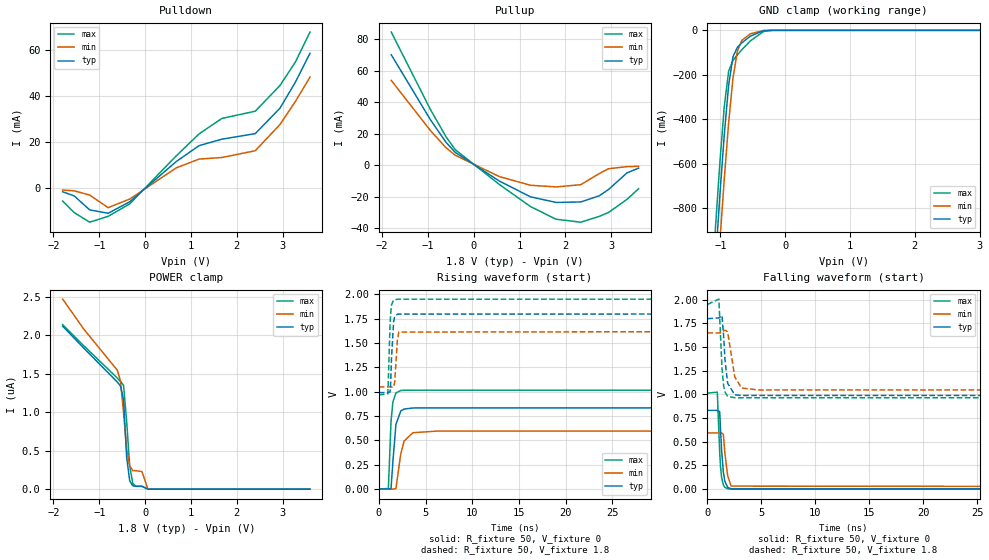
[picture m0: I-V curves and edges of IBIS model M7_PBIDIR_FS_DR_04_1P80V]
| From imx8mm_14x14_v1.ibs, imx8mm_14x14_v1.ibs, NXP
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[Model] M7_PBIDIR_FS_DR_04_1P80V
Model_type I/O
Vinl  =  0.54
Vinh  =  1.26
Vmeas =  0.9
| Capacitance   typ   min   max
C_comp   4.70306747824e-12   4.592798992e-12   4.8293865999e-12
| Variables   typ   min   max
[GND Clamp Reference]   0   0   0
[POWER Clamp Reference]   1.8   1.65   1.95
[Pulldown Reference]   0   0   0
[Pullup Reference]   1.8   1.65   1.95
[Temperature Range]   25   125   -40
[Voltage Range]   1.8   1.65   1.95
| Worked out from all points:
|   slope of the pulldown table from 0 to 0.27 V, typ, clamps not added: 57.2 ohm
|   slope of the pullup table from 0 to 0.27 V, typ, clamps not added: 54.1 ohm
|   GND clamp passes 1 mA (typ) near -0.31 V on its own axis
|   falling waveform, R_fixture 50, V_fixture 0: 20-80 % time 288ps typ, 356ps min, 246ps max; typ from 0.832 V to 0 V
|   falling waveform, R_fixture 50, V_fixture 1.8: 20-80 % time 330ps typ, 516ps min, 250ps max; typ from 1.8 V to 0.989 V
|   rising waveform, R_fixture 50, V_fixture 0: 20-80 % time 396ps typ, 621ps min, 281ps max; typ from 0 V to 0.832 V
|   rising waveform, R_fixture 50, V_fixture 1.8: 20-80 % time 221ps typ, 244ps min, 202ps max; typ from 0.989 V to 1.8 V
[GND Clamp]
| Voltage   I(typ)   I(min)   I(max)
-1.8V     -4.612A    -4.803A    -4.458A
-1.076V   -1.039A    -1.25A     -883.5mA
-1.009V   -742.9mA   -951.7mA   -595.3mA
-941.4mV  -471.2mA   -670.1mA   -343.8mA
-874.1mV  -248.1mA   -417.3mA   -184.9mA
-806.9mV  -119.4mA   -215.9mA   -135.7mA
-739.7mV  -76.88mA   -94.46mA   -110.7mA
-672.4mV  -56.93mA   -45.5mA    -88.16mA
-537.9mV  -26.26mA   -15.72mA   -47.3mA
-336.2mV  -1.51mA    -830.1uA   -5.564mA
-201.7mV  -19.77uA   -26.41uA   -67.32uA
3.6V      0A         0A         0A
[POWER Clamp]
| Voltage   I(typ)   I(min)   I(max)
-1.8V     2.118uA    2.47uA     2.138uA
-1.345V   1.837uA    2.085uA    1.867uA
-605.2mV  1.391uA    1.544uA    1.443uA
-537.9mV  1.341uA    1.406uA    1.4uA
-470.7mV  1.162uA    995nA      1.35uA
-403.4mV  420.6nA    524.2nA    889.2nA
-336.2mV  108.1nA    302.3nA    302.3nA
-269mV    43.69nA    240.7nA    73.26nA
-201.7mV  37.94nA    239.7nA    38.35nA
-67.24mV  37.94nA    228nA      35.87nA
62.07mV   0A         0A         0A
3.6V      0A         0A         0A
[Pulldown]
| Voltage   I(typ)   I(min)   I(max)
-1.8V     -1.575mA   -833.7uA   -5.6mA
-1.547V   -3.386mA   -1.171mA   -10.66mA
-1.21V    -9.476mA   -3.011mA   -14.83mA
-806.9mV  -10.95mA   -8.504mA   -12.27mA
-336.2mV  -5.936mA   -4.752mA   -6.854mA
682.8mV   11.63mA    8.866mA    14.11mA
1.179V    18.52mA    12.66mA    23.65mA
1.676V    21.34mA    13.35mA    30.36mA
2.405V    23.74mA    16.3mA     33.52mA
2.943V    34.79mA    27.67mA    44.66mA
3.279V    46.07mA    37.7mA     54.86mA
3.6V      58.77mA    48.37mA    67.98mA
[Pullup]
| Voltage   I(typ)   I(min)   I(max)
-1.8V     70.12mA    53.82mA    84.52mA
-941.4mV  28.68mA    21.82mA    35.12mA
-605.2mV  14.52mA    11.06mA    18.06mA
-403.4mV  8.068mA    6.262mA    9.807mA
558.6mV   -10.1mA    -7.291mA   -12.27mA
1.241V    -20.17mA   -12.81mA   -26.36mA
1.8V      -23.72mA   -13.86mA   -34.41mA
2.338V    -23.4mA    -12.43mA   -36.27mA
2.741V    -19.49mA   -5.38mA    -32.58mA
2.943V    -15.51mA   -2.29mA    -30.11mA
3.347V    -4.931mA   -973.6uA   -21.73mA
3.6V      -1.906mA   -772.5uA   -15.01mA
[Ramp]
dV/dt_r   0.499337/0.396215n  0.356235/0.621124n  0.608609/0.280689n
dV/dt_f   0.486425/0.330134n  0.362083/0.515686n  0.590892/0.250162n
R_load = 50
[Falling Waveform]
R_fixture = 50
V_fixture = 0
V_fixture_min = 0
V_fixture_max = 0
| Time   V(typ)   V(min)   V(max)
0s        832.2mV    593.7mV    1.014V
910.7ps   832.3mV    593.7mV    1.024V
1.129ns   818.4mV    593.7mV    398.6mV
1.206ns   633mV      593.7mV    237.2mV
1.306ns   418.5mV    593.6mV    125.7mV
1.472ns   178.5mV    577.2mV    44.8mV
1.6ns     86.23mV    395.5mV    20.02mV
1.866ns   20.38mV    143.9mV    3.757mV
2.192ns   3.504mV    32.04mV    419.2uV
333.3ns   143.8nV    254.7nV    168.3nV
[Falling Waveform]
R_fixture = 50
V_fixture = 1.8
V_fixture_min = 1.65
V_fixture_max = 1.95
| Time   V(typ)   V(min)   V(max)
0s        1.8V       1.65V      1.95V
1.054ns   1.808V     1.65V      2.007V
1.344ns   1.833V     1.65V      1.277V
1.499ns   1.614V     1.672V     1.09V
1.622ns   1.366V     1.679V     1.026V
1.867ns   1.119V     1.662V     980.2mV
2.529ns   995.8mV    1.185V     965.6mV
3.154ns   989.8mV    1.068V     965.3mV
4.78ns    989.3mV    1.047V     965.2mV
333.3ns   989.3mV    1.047V     965.2mV
[Rising Waveform]
R_fixture = 50
V_fixture = 0
V_fixture_min = 0
V_fixture_max = 0
| Time   V(typ)   V(min)   V(max)
0s        122.9nV    367nV      152.9nV
1.018ns   -536.8uV   -10.77uV   3.479mV
1.3ns     696.3uV    -263.7uV   690.5mV
1.499ns   279mV      -2.692mV   892.9mV
1.825ns   661.5mV    4.081mV    985.9mV
2.343ns   799.7mV    358.7mV    1.011V
2.701ns   820.3mV    491.8mV    1.013V
3.644ns   831.2mV    577.2mV    1.014V
6.18ns    832.2mV    593.5mV    1.014V
333.3ns   832.2mV    593.7mV    1.014V
[Rising Waveform]
R_fixture = 50
V_fixture = 1.8
V_fixture_min = 1.65
V_fixture_max = 1.95
| Time   V(typ)   V(min)   V(max)
0s        989.3mV    1.047V     965.2mV
968.8ps   989mV      1.047V     977.5mV
1.193ns   995.2mV    1.047V     1.682V
1.255ns   1.06V      1.046V     1.779V
1.349ns   1.335V     1.046V     1.89V
1.578ns   1.717V     1.046V     1.941V
1.697ns   1.772V     1.1V       1.944V
1.971ns   1.793V     1.516V     1.948V
2.132ns   1.796V     1.611V     1.949V
333.3ns   1.8V       1.65V      1.95V
[Add Submodel]
| Submodel Name Mode
M7_PBIDIR_FS_DR_04_1P80V_T All
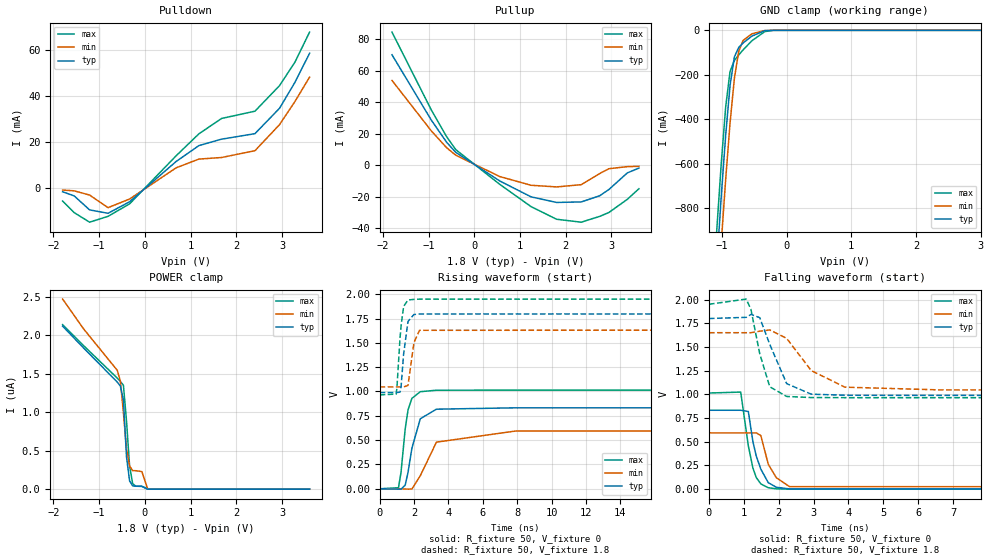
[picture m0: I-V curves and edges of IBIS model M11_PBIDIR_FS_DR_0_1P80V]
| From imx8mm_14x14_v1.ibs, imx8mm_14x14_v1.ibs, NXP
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[Model] M11_PBIDIR_FS_DR_0_1P80V
Model_type I/O
Vinl  =  0.54
Vinh  =  1.26
Vmeas =  0.9
| Capacitance   typ   min   max
C_comp   4.70306747824e-12   4.592798992e-12   4.8293865999e-12
| Variables   typ   min   max
[GND Clamp Reference]   0   0   0
[POWER Clamp Reference]   1.8   1.65   1.95
[Pulldown Reference]   0   0   0
[Pullup Reference]   1.8   1.65   1.95
[Temperature Range]   25   125   -40
[Voltage Range]   1.8   1.65   1.95
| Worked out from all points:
|   slope of the pulldown table from 0 to 0.27 V, typ, clamps not added: 57.2 ohm
|   slope of the pullup table from 0 to 0.27 V, typ, clamps not added: 54.1 ohm
|   GND clamp passes 1 mA (typ) near -0.31 V on its own axis
|   falling waveform, R_fixture 50, V_fixture 0: 20-80 % time 339ps typ, 383ps min, 290ps max; typ from 0.832 V to 0 V
|   falling waveform, R_fixture 50, V_fixture 1.8: 20-80 % time 498ps typ, 834ps min, 355ps max; typ from 1.8 V to 0.989 V
|   rising waveform, R_fixture 50, V_fixture 0: 20-80 % time 565ps typ, 946ps min, 388ps max; typ from 0 V to 0.832 V
|   rising waveform, R_fixture 50, V_fixture 1.8: 20-80 % time 282ps typ, 290ps min, 257ps max; typ from 0.989 V to 1.8 V
[GND Clamp]
| Voltage   I(typ)   I(min)   I(max)
-1.8V     -4.612A    -4.803A    -4.458A
-1.076V   -1.039A    -1.25A     -883.5mA
-1.009V   -742.9mA   -951.7mA   -595.3mA
-941.4mV  -471.2mA   -670.1mA   -343.8mA
-874.1mV  -248.1mA   -417.3mA   -184.9mA
-806.9mV  -119.4mA   -215.9mA   -135.7mA
-739.7mV  -76.88mA   -94.46mA   -110.7mA
-672.4mV  -56.93mA   -45.5mA    -88.16mA
-537.9mV  -26.26mA   -15.72mA   -47.3mA
-336.2mV  -1.51mA    -830.1uA   -5.564mA
-201.7mV  -19.77uA   -26.41uA   -67.32uA
3.6V      0A         0A         0A
[POWER Clamp]
| Voltage   I(typ)   I(min)   I(max)
-1.8V     2.118uA    2.47uA     2.138uA
-1.345V   1.837uA    2.085uA    1.867uA
-605.2mV  1.391uA    1.544uA    1.443uA
-537.9mV  1.341uA    1.406uA    1.4uA
-470.7mV  1.162uA    995nA      1.35uA
-403.4mV  420.6nA    524.2nA    889.2nA
-336.2mV  108.1nA    302.3nA    302.3nA
-269mV    43.69nA    240.7nA    73.26nA
-201.7mV  37.94nA    239.7nA    38.35nA
-67.24mV  37.94nA    228nA      35.87nA
62.07mV   0A         0A         0A
3.6V      0A         0A         0A
[Pulldown]
| Voltage   I(typ)   I(min)   I(max)
-1.8V     -1.575mA   -833.7uA   -5.6mA
-1.547V   -3.386mA   -1.171mA   -10.66mA
-1.21V    -9.476mA   -3.011mA   -14.83mA
-806.9mV  -10.95mA   -8.504mA   -12.27mA
-336.2mV  -5.936mA   -4.752mA   -6.854mA
682.8mV   11.63mA    8.866mA    14.11mA
1.179V    18.52mA    12.66mA    23.65mA
1.676V    21.34mA    13.35mA    30.36mA
2.405V    23.74mA    16.3mA     33.52mA
2.943V    34.79mA    27.67mA    44.66mA
3.279V    46.07mA    37.7mA     54.86mA
3.6V      58.77mA    48.37mA    67.98mA
[Pullup]
| Voltage   I(typ)   I(min)   I(max)
-1.8V     70.12mA    53.82mA    84.52mA
-941.4mV  28.68mA    21.82mA    35.12mA
-605.2mV  14.52mA    11.06mA    18.06mA
-403.4mV  8.068mA    6.262mA    9.807mA
558.6mV   -10.1mA    -7.291mA   -12.27mA
1.241V    -20.17mA   -12.81mA   -26.36mA
1.8V      -23.72mA   -13.86mA   -34.41mA
2.338V    -23.4mA    -12.43mA   -36.27mA
2.741V    -19.49mA   -5.38mA    -32.58mA
2.943V    -15.51mA   -2.29mA    -30.11mA
3.347V    -4.931mA   -973.6uA   -21.73mA
3.6V      -1.906mA   -772.5uA   -15.01mA
[Ramp]
dV/dt_r   0.499336/0.564659n  0.356235/0.945506n  0.608609/0.388415n
dV/dt_f   0.486425/0.498287n  0.362083/0.834239n  0.590892/0.354791n
R_load = 50
[Falling Waveform]
R_fixture = 50
V_fixture = 0
V_fixture_min = 0
V_fixture_max = 0
| Time   V(typ)   V(min)   V(max)
0s        832.2mV    593.7mV    1.014V
910.3ps   832.3mV    593.7mV    1.024V
1.129ns   819.1mV    593.7mV    457mV
1.26ns    500.3mV    593.7mV    222mV
1.357ns   348mV      593.8mV    122.2mV
1.487ns   210.9mV    565.1mV    55.33mV
1.701ns   68.21mV    261.9mV    14.85mV
1.931ns   20.24mV    120.8mV    3.715mV
2.309ns   2.865mV    26.58mV    410.8uV
333.3ns   143.8nV    254.8nV    168.3nV
[Falling Waveform]
R_fixture = 50
V_fixture = 1.8
V_fixture_min = 1.65
V_fixture_max = 1.95
| Time   V(typ)   V(min)   V(max)
0s        1.8V       1.65V      1.95V
1.068ns   1.812V     1.65V      2.005V
1.205ns   1.843V     1.65V      1.894V
1.456ns   1.809V     1.666V     1.428V
1.743ns   1.527V     1.679V     1.08V
2.228ns   1.113V     1.59V      977.7mV
2.932ns   1.002V     1.251V     966.2mV
3.894ns   990.6mV    1.076V     965.2mV
6.604ns   989.3mV    1.047V     965.2mV
333.3ns   989.3mV    1.047V     965.2mV
[Rising Waveform]
R_fixture = 50
V_fixture = 0
V_fixture_min = 0
V_fixture_max = 0
| Time   V(typ)   V(min)   V(max)
0s        122.9nV    367nV      152.9nV
1.097ns   -3.252mV   -8.598uV   10.94mV
1.244ns   -3.999mV   -96.31uV   169.3mV
1.487ns   36.98mV    -2.223mV   615.6mV
1.654ns   171.7mV    -3.846mV   812.8mV
1.878ns   418.4mV    -2.082mV   929.5mV
2.365ns   719.7mV    134.2mV    997.9mV
3.303ns   818.1mV    479.2mV    1.013V
7.897ns   832.2mV    593.5mV    1.014V
333.3ns   832.2mV    593.7mV    1.014V
[Rising Waveform]
R_fixture = 50
V_fixture = 1.8
V_fixture_min = 1.65
V_fixture_max = 1.95
| Time   V(typ)   V(min)   V(max)
0s        989.3mV    1.047V     965.2mV
959.2ps   989.1mV    1.047V     973.1mV
1.003ns   988.8mV    1.047V     1.029V
1.189ns   994.2mV    1.047V     1.555V
1.248ns   1.05V      1.047V     1.673V
1.394ns   1.383V     1.046V     1.874V
1.65ns    1.72V      1.063V     1.94V
1.994ns   1.791V     1.501V     1.947V
2.318ns   1.797V     1.629V     1.949V
333.3ns   1.8V       1.65V      1.95V
[Add Submodel]
| Submodel Name Mode
M11_PBIDIR_FS_DR_0_1P80V_T All
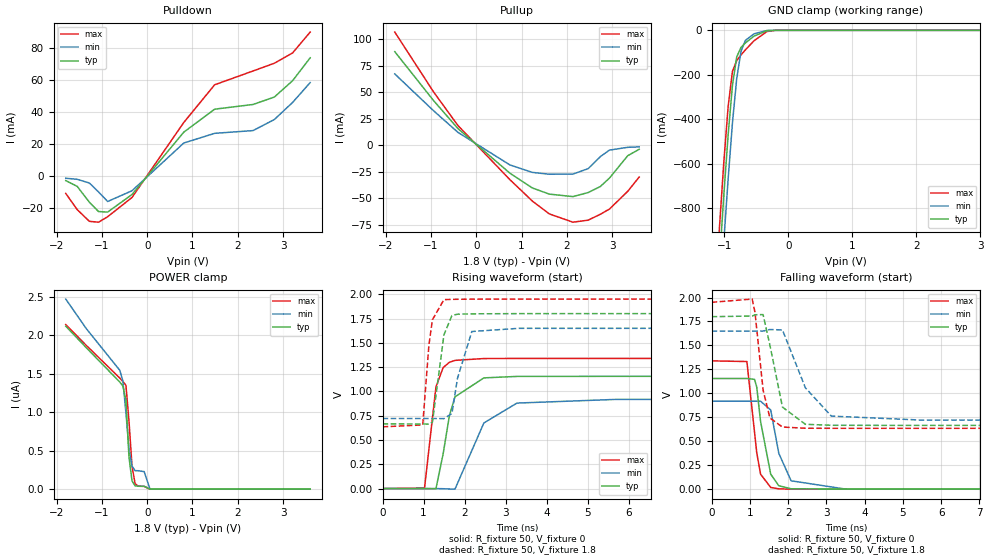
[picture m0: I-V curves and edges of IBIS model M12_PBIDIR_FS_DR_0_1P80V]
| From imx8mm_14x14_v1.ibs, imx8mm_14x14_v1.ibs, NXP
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[Model] M12_PBIDIR_FS_DR_0_1P80V
Model_type I/O
Vinl  =  0.54
Vinh  =  1.26
Vmeas =  0.9
| Capacitance   typ   min   max
C_comp   4.70306747824e-12   4.592798992e-12   4.8293865999e-12
| Variables   typ   min   max
[GND Clamp Reference]   0   0   0
[POWER Clamp Reference]   1.8   1.65   1.95
[Pulldown Reference]   0   0   0
[Pullup Reference]   1.8   1.65   1.95
[Temperature Range]   25   125   -40
[Voltage Range]   1.8   1.65   1.95
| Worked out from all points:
|   slope of the pulldown table from 0 to 0.27 V, typ, clamps not added: 28.6 ohm
|   slope of the pullup table from 0 to 0.27 V, typ, clamps not added: 27.1 ohm
|   GND clamp passes 1 mA (typ) near -0.31 V on its own axis
|   falling waveform, R_fixture 50, V_fixture 0: 20-80 % time 273ps typ, 348ps min, 217ps max; typ from 1.16 V to 0 V
|   falling waveform, R_fixture 50, V_fixture 1.8: 20-80 % time 322ps typ, 550ps min, 229ps max; typ from 1.8 V to 0.665 V
|   rising waveform, R_fixture 50, V_fixture 0: 20-80 % time 314ps typ, 558ps min, 209ps max; typ from 0 V to 1.16 V
|   rising waveform, R_fixture 50, V_fixture 1.8: 20-80 % time 196ps typ, 251ps min, 154ps max; typ from 0.665 V to 1.8 V
[GND Clamp]
| Voltage   I(typ)   I(min)   I(max)
-1.8V     -4.612A    -4.803A    -4.458A
-1.076V   -1.039A    -1.25A     -883.5mA
-1.009V   -742.9mA   -951.7mA   -595.3mA
-941.4mV  -471.2mA   -670.1mA   -343.8mA
-874.1mV  -248.1mA   -417.3mA   -184.9mA
-806.9mV  -119.4mA   -215.9mA   -135.7mA
-739.7mV  -76.88mA   -94.46mA   -110.7mA
-672.4mV  -56.93mA   -45.5mA    -88.16mA
-537.9mV  -26.26mA   -15.72mA   -47.3mA
-336.2mV  -1.51mA    -830.1uA   -5.564mA
-201.7mV  -19.77uA   -26.41uA   -67.32uA
3.6V      0A         0A         0A
[POWER Clamp]
| Voltage   I(typ)   I(min)   I(max)
-1.8V     2.118uA    2.47uA     2.138uA
-1.345V   1.837uA    2.085uA    1.867uA
-605.2mV  1.391uA    1.544uA    1.443uA
-537.9mV  1.341uA    1.406uA    1.4uA
-470.7mV  1.162uA    995nA      1.35uA
-403.4mV  420.6nA    524.2nA    889.2nA
-336.2mV  108.1nA    302.3nA    302.3nA
-269mV    43.69nA    240.7nA    73.26nA
-201.7mV  37.94nA    239.7nA    38.35nA
-67.24mV  37.94nA    228nA      35.87nA
62.07mV   0A         0A         0A
3.6V      0A         0A         0A
[Pulldown]
| Voltage   I(typ)   I(min)   I(max)
-1.8V     -3.15mA    -1.667mA   -11.19mA
-1.547V   -6.77mA    -2.342mA   -21.31mA
-1.278V   -16.69mA   -4.661mA   -28.65mA
-1.076V   -22.53mA   -10.23mA   -29.19mA
-874.1mV  -22.85mA   -16.23mA   -25.77mA
-336.2mV  -11.87mA   -9.504mA   -13.71mA
806.9mV   27.15mA    20.36mA    33.2mA
1.49V     41.56mA    26.44mA    56.83mA
2.338V    44.49mA    28.15mA    65.47mA
2.809V    49.16mA    35.09mA    70.32mA
3.212V    59.38mA    45.77mA    76.77mA
3.6V      73.7mA     58.2mA     89.81mA
[Pullup]
| Voltage   I(typ)   I(min)   I(max)
-1.8V     88.31mA    67.29mA    106.8mA
-941.4mV  42.1mA     32.51mA    50.24mA
-403.4mV  15.68mA    12.13mA    18.58mA
744.8mV   -26.42mA   -18.6mA    -32.54mA
1.241V    -40.33mA   -25.63mA   -52.73mA
1.614V    -46.11mA   -27.35mA   -64.79mA
2.136V    -48.48mA   -27.22mA   -72.62mA
2.472V    -44.63mA   -22.09mA   -70.71mA
2.741V    -38.97mA   -10.76mA   -65.16mA
2.943V    -31.02mA   -4.579mA   -60.22mA
3.347V    -9.859mA   -1.947mA   -43.46mA
3.6V      -3.81mA    -1.544mA   -30.02mA
[Ramp]
dV/dt_r   0.693264/0.31348n  0.550649/0.557594n  0.803541/0.208875n
dV/dt_f   0.680858/0.321929n  0.557334/0.550474n  0.788905/0.229358n
R_load = 50
[Falling Waveform]
R_fixture = 50
V_fixture = 0
V_fixture_min = 0
V_fixture_max = 0
| Time   V(typ)   V(min)   V(max)
0s        1.155V     917.7mV    1.339V
923.4ps   1.155V     917.7mV    1.332V
1.122ns   1.146V     917.7mV    598.2mV
1.181ns   1.066V     917.7mV    379.4mV
1.281ns   706.5mV    917.7mV    156.6mV
1.546ns   156.6mV    826.5mV    17.68mV
1.758ns   35.18mV    373.2mV    3.379mV
2.079ns   4.229mV    87.35mV    310uV
3.514ns   89.63uV    185.8uV    17.48uV
333.3ns   104.4nV    218.5nV    100.8nV
[Falling Waveform]
R_fixture = 50
V_fixture = 1.8
V_fixture_min = 1.65
V_fixture_max = 1.95
| Time   V(typ)   V(min)   V(max)
0s        1.8V       1.65V      1.95V
1.062ns   1.807V     1.65V      1.984V
1.135ns   1.82V      1.65V      1.845V
1.347ns   1.822V     1.65V      1.034V
1.525ns   1.503V     1.666V     743.1mV
1.853ns   856.7mV    1.662V     648.3mV
2.452ns   676.9mV    1.058V     636mV
3.131ns   666.8mV    762.6mV    635.3mV
5.439ns   665.3mV    721.7mV    635.2mV
333.3ns   665.2mV    721.1mV    635.2mV
[Rising Waveform]
R_fixture = 50
V_fixture = 0
V_fixture_min = 0
V_fixture_max = 0
| Time   V(typ)   V(min)   V(max)
0s        68.86nV    226.7nV    78.92nV
1.023ns   -425.3uV   -5.373uV   6.148mV
1.301ns   -1.154mV   -201.4uV   1.046V
1.476ns   356.7mV    -1.514mV   1.245V
1.628ns   749.3mV    -4.306mV   1.299V
1.764ns   943.4mV    -6.141mV   1.319V
2.468ns   1.139V     675mV      1.338V
3.275ns   1.154V     879.7mV    1.339V
5.665ns   1.155V     917.2mV    1.339V
333.3ns   1.155V     917.7mV    1.339V
[Rising Waveform]
R_fixture = 50
V_fixture = 1.8
V_fixture_min = 1.65
V_fixture_max = 1.95
| Time   V(typ)   V(min)   V(max)
0s        665.2mV    721.1mV    635.2mV
978.7ps   665mV      721.1mV    655mV
1.129ns   662.5mV    721.1mV    1.475V
1.215ns   682.7mV    721.1mV    1.737V
1.496ns   1.583V     719.4mV    1.944V
1.691ns   1.781V     773.2mV    1.947V
1.825ns   1.794V     1.134V     1.948V
2.175ns   1.798V     1.616V     1.949V
3.322ns   1.8V       1.649V     1.95V
333.3ns   1.8V       1.65V      1.95V
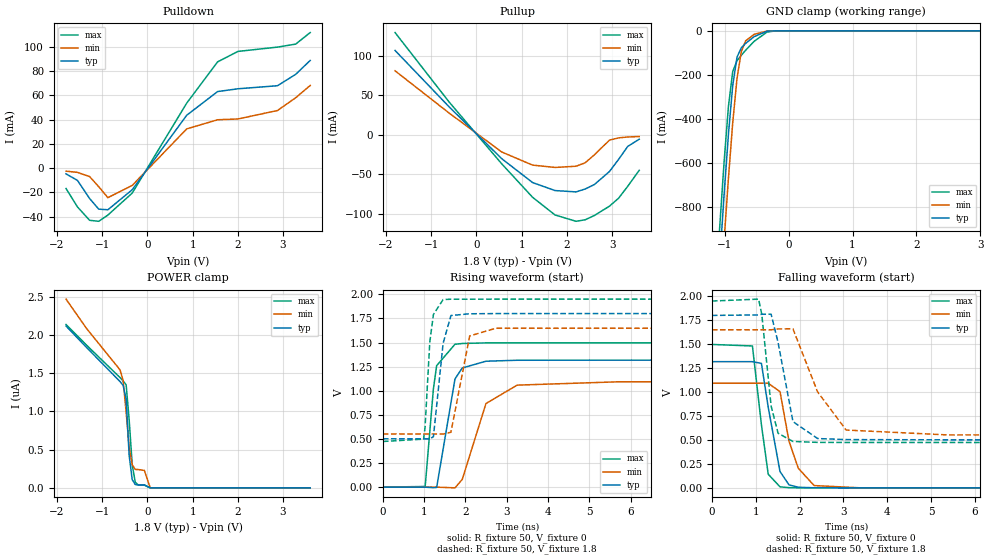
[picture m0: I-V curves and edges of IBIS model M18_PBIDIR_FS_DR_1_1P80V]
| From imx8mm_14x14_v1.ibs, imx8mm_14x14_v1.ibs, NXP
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[Model] M18_PBIDIR_FS_DR_1_1P80V
Model_type I/O
Vinl  =  0.54
Vinh  =  1.26
Vmeas =  0.9
| Capacitance   typ   min   max
C_comp   4.70306747824e-12   4.592798992e-12   4.8293865999e-12
| Variables   typ   min   max
[GND Clamp Reference]   0   0   0
[POWER Clamp Reference]   1.8   1.65   1.95
[Pulldown Reference]   0   0   0
[Pullup Reference]   1.8   1.65   1.95
[Temperature Range]   25   125   -40
[Voltage Range]   1.8   1.65   1.95
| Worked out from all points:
|   slope of the pulldown table from 0 to 0.27 V, typ, clamps not added: 19.1 ohm
|   slope of the pullup table from 0 to 0.27 V, typ, clamps not added: 18 ohm
|   GND clamp passes 1 mA (typ) near -0.31 V on its own axis
|   falling waveform, R_fixture 50, V_fixture 0: 20-80 % time 266ps typ, 343ps min, 206ps max; typ from 1.32 V to 0 V
|   falling waveform, R_fixture 50, V_fixture 1.8: 20-80 % time 298ps typ, 520ps min, 208ps max; typ from 1.8 V to 0.501 V
|   rising waveform, R_fixture 50, V_fixture 0: 20-80 % time 266ps typ, 488ps min, 173ps max; typ from 0 V to 1.32 V
|   rising waveform, R_fixture 50, V_fixture 1.8: 20-80 % time 177ps typ, 242ps min, 130ps max; typ from 0.501 V to 1.8 V
[GND Clamp]
| Voltage   I(typ)   I(min)   I(max)
-1.8V     -4.612A    -4.803A    -4.458A
-1.076V   -1.039A    -1.25A     -883.5mA
-1.009V   -742.9mA   -951.7mA   -595.3mA
-941.4mV  -471.2mA   -670.1mA   -343.8mA
-874.1mV  -248.1mA   -417.3mA   -184.9mA
-806.9mV  -119.4mA   -215.9mA   -135.7mA
-739.7mV  -76.88mA   -94.46mA   -110.7mA
-672.4mV  -56.93mA   -45.5mA    -88.16mA
-537.9mV  -26.26mA   -15.72mA   -47.3mA
-336.2mV  -1.51mA    -830.1uA   -5.564mA
-201.7mV  -19.77uA   -26.41uA   -67.32uA
3.6V      0A         0A         0A
[POWER Clamp]
| Voltage   I(typ)   I(min)   I(max)
-1.8V     2.118uA    2.47uA     2.138uA
-1.345V   1.837uA    2.085uA    1.867uA
-605.2mV  1.391uA    1.544uA    1.443uA
-537.9mV  1.341uA    1.406uA    1.4uA
-470.7mV  1.162uA    995nA      1.35uA
-403.4mV  420.6nA    524.2nA    889.2nA
-336.2mV  108.1nA    302.3nA    302.3nA
-269mV    43.69nA    240.7nA    73.26nA
-201.7mV  37.94nA    239.7nA    38.35nA
-67.24mV  37.94nA    228nA      35.87nA
62.07mV   0A         0A         0A
3.6V      0A         0A         0A
[Pulldown]
| Voltage   I(typ)   I(min)   I(max)
-1.8V     -4.723mA   -2.5mA     -16.79mA
-1.547V   -10.15mA   -3.513mA   -31.96mA
-1.278V   -25.04mA   -6.991mA   -42.98mA
-1.076V   -33.79mA   -15.34mA   -43.79mA
-874.1mV  -34.28mA   -24.35mA   -38.65mA
-336.2mV  -17.81mA   -14.26mA   -20.56mA
869mV     43.52mA    32.29mA    53.49mA
1.552V    63.03mA    39.81mA    87.46mA
2.002V    65.31mA    40.45mA    96.08mA
2.876V    67.83mA    47.41mA    99.62mA
3.279V    77.2mA     57.92mA    102.1mA
3.6V      88.63mA    68.04mA    111.6mA
[Pullup]
| Voltage   I(typ)   I(min)   I(max)
-1.8V     106.5mA    80.76mA    129.1mA
-605.2mV  35.27mA    27.4mA     41.39mA
558.6mV   -30.29mA   -21.87mA   -36.8mA
1.241V    -60.5mA    -38.44mA   -79.09mA
1.738V    -70.63mA   -41.42mA   -101.5mA
2.203V    -72.34mA   -39.89mA   -109.5mA
2.405V    -68.67mA   -35.54mA   -107.6mA
2.607V    -63.07mA   -25.54mA   -102.2mA
2.943V    -46.52mA   -6.869mA   -90.32mA
3.145V    -31.14mA   -4.009mA   -80.26mA
3.347V    -14.79mA   -2.92mA    -65.18mA
3.6V      -5.714mA   -2.316mA   -45.03mA
[Ramp]
dV/dt_r   0.790354/0.26562n  0.655412/0.487633n  0.898027/0.173148n
dV/dt_f   0.779145/0.298308n  0.659063/0.520234n  0.885904/0.207498n
R_load = 50
[Falling Waveform]
R_fixture = 50
V_fixture = 0
V_fixture_min = 0
V_fixture_max = 0
| Time   V(typ)   V(min)   V(max)
0s        1.317V     1.092V     1.497V
925.6ps   1.317V     1.092V     1.481V
1.131ns   1.299V     1.092V     658mV
1.286ns   840.8mV    1.092V     142mV
1.555ns   170.6mV    1.004V     10.86mV
1.76ns    30.91mV    486.7mV    1.93mV
1.972ns   6.403mV    204.6mV    420.7uV
2.333ns   758.2uV    23.96mV    176.1uV
3.39ns    173.7uV    310.3uV    175.5uV
333.3ns   84.11nV    198.6nV    67.41nV
[Falling Waveform]
R_fixture = 50
V_fixture = 1.8
V_fixture_min = 1.65
V_fixture_max = 1.95
| Time   V(typ)   V(min)   V(max)
0s        1.8V       1.65V      1.95V
1.066ns   1.805V     1.65V      1.97V
1.139ns   1.812V     1.65V      1.811V
1.352ns   1.813V     1.65V      853.6mV
1.511ns   1.517V     1.659V     570.2mV
1.85ns    691.4mV    1.66V      484.4mV
2.413ns   514.8mV    1.001V     474.7mV
3.064ns   503.8mV    603.5mV    473.7mV
5.379ns   501.4mV    552.6mV    473.5mV
333.3ns   501.4mV    551.6mV    473.5mV
[Rising Waveform]
R_fixture = 50
V_fixture = 0
V_fixture_min = 0
V_fixture_max = 0
| Time   V(typ)   V(min)   V(max)
0s        41nV       149.8nV    42.36nV
1.025ns   -323.8uV   -4.374uV   6.901mV
1.224ns   -5.701mV   -64.66uV   1.018V
1.303ns   -3.195mV   -160.2uV   1.26V
1.747ns   1.122V     -7.483mV   1.482V
1.923ns   1.236V     79.95mV    1.49V
2.497ns   1.306V     867mV      1.496V
3.252ns   1.316V     1.058V     1.497V
5.664ns   1.317V     1.092V     1.497V
333.3ns   1.317V     1.092V     1.497V
[Rising Waveform]
R_fixture = 50
V_fixture = 1.8
V_fixture_min = 1.65
V_fixture_max = 1.95
| Time   V(typ)   V(min)   V(max)
0s        501.4mV    551.6mV    473.5mV
986.7ps   501.2mV    551.6mV    498mV
1.022ns   501.1mV    551.6mV    617.3mV
1.137ns   499.6mV    551.6mV    1.506V
1.225ns   523.9mV    551.5mV    1.791V
1.46ns    1.493V     550.5mV    1.946V
1.649ns   1.78V      569.5mV    1.949V
2.103ns   1.798V     1.568V     1.949V
2.737ns   1.8V       1.648V     1.95V
333.3ns   1.8V       1.65V      1.95V
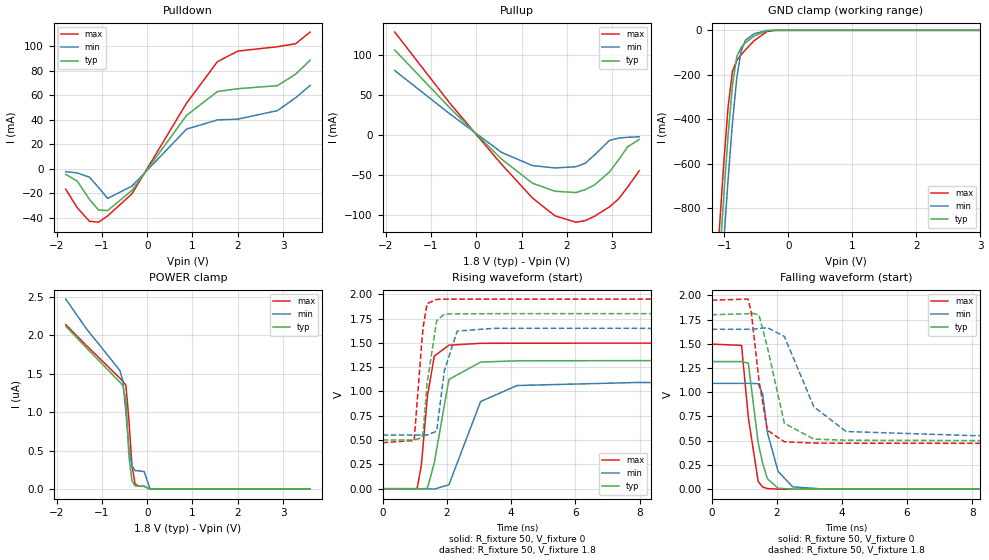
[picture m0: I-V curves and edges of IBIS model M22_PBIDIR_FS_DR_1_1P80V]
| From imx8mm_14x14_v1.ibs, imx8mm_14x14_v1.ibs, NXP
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[Model] M22_PBIDIR_FS_DR_1_1P80V
Model_type I/O
Vinl  =  0.54
Vinh  =  1.26
Vmeas =  0.9
| Capacitance   typ   min   max
C_comp   4.70306747824e-12   4.592798992e-12   4.8293865999e-12
| Variables   typ   min   max
[GND Clamp Reference]   0   0   0
[POWER Clamp Reference]   1.8   1.65   1.95
[Pulldown Reference]   0   0   0
[Pullup Reference]   1.8   1.65   1.95
[Temperature Range]   25   125   -40
[Voltage Range]   1.8   1.65   1.95
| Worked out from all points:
|   slope of the pulldown table from 0 to 0.27 V, typ, clamps not added: 19.1 ohm
|   slope of the pullup table from 0 to 0.27 V, typ, clamps not added: 18 ohm
|   GND clamp passes 1 mA (typ) near -0.31 V on its own axis
|   falling waveform, R_fixture 50, V_fixture 0: 20-80 % time 335ps typ, 375ps min, 278ps max; typ from 1.32 V to 0 V
|   falling waveform, R_fixture 50, V_fixture 1.8: 20-80 % time 471ps typ, 856ps min, 318ps max; typ from 1.8 V to 0.501 V
|   rising waveform, R_fixture 50, V_fixture 0: 20-80 % time 383ps typ, 699ps min, 257ps max; typ from 0 V to 1.32 V
|   rising waveform, R_fixture 50, V_fixture 1.8: 20-80 % time 277ps typ, 330ps min, 212ps max; typ from 0.501 V to 1.8 V
[GND Clamp]
| Voltage   I(typ)   I(min)   I(max)
-1.8V     -4.612A    -4.803A    -4.458A
-1.076V   -1.039A    -1.25A     -883.5mA
-1.009V   -742.9mA   -951.7mA   -595.3mA
-941.4mV  -471.2mA   -670.1mA   -343.8mA
-874.1mV  -248.1mA   -417.3mA   -184.9mA
-806.9mV  -119.4mA   -215.9mA   -135.7mA
-739.7mV  -76.88mA   -94.46mA   -110.7mA
-672.4mV  -56.93mA   -45.5mA    -88.16mA
-537.9mV  -26.26mA   -15.72mA   -47.3mA
-336.2mV  -1.51mA    -830.1uA   -5.564mA
-201.7mV  -19.77uA   -26.41uA   -67.32uA
3.6V      0A         0A         0A
[POWER Clamp]
| Voltage   I(typ)   I(min)   I(max)
-1.8V     2.118uA    2.47uA     2.138uA
-1.345V   1.837uA    2.085uA    1.867uA
-605.2mV  1.391uA    1.544uA    1.443uA
-537.9mV  1.341uA    1.406uA    1.4uA
-470.7mV  1.162uA    995nA      1.35uA
-403.4mV  420.6nA    524.2nA    889.2nA
-336.2mV  108.1nA    302.3nA    302.3nA
-269mV    43.69nA    240.7nA    73.26nA
-201.7mV  37.94nA    239.7nA    38.35nA
-67.24mV  37.94nA    228nA      35.87nA
62.07mV   0A         0A         0A
3.6V      0A         0A         0A
[Pulldown]
| Voltage   I(typ)   I(min)   I(max)
-1.8V     -4.723mA   -2.5mA     -16.79mA
-1.547V   -10.15mA   -3.513mA   -31.96mA
-1.278V   -25.04mA   -6.991mA   -42.98mA
-1.076V   -33.79mA   -15.34mA   -43.79mA
-874.1mV  -34.28mA   -24.35mA   -38.65mA
-336.2mV  -17.81mA   -14.26mA   -20.56mA
869mV     43.52mA    32.29mA    53.49mA
1.552V    63.03mA    39.81mA    87.46mA
2.002V    65.31mA    40.45mA    96.08mA
2.876V    67.83mA    47.41mA    99.62mA
3.279V    77.2mA     57.92mA    102.1mA
3.6V      88.63mA    68.04mA    111.6mA
[Pullup]
| Voltage   I(typ)   I(min)   I(max)
-1.8V     106.5mA    80.76mA    129.1mA
-605.2mV  35.27mA    27.4mA     41.39mA
558.6mV   -30.29mA   -21.87mA   -36.8mA
1.241V    -60.5mA    -38.44mA   -79.09mA
1.738V    -70.63mA   -41.42mA   -101.5mA
2.203V    -72.34mA   -39.89mA   -109.5mA
2.405V    -68.67mA   -35.54mA   -107.6mA
2.607V    -63.07mA   -25.54mA   -102.2mA
2.943V    -46.52mA   -6.869mA   -90.32mA
3.145V    -31.14mA   -4.009mA   -80.26mA
3.347V    -14.79mA   -2.92mA    -65.18mA
3.6V      -5.714mA   -2.316mA   -45.03mA
[Ramp]
dV/dt_r   0.790354/0.382574n  0.655412/0.69878n  0.898027/0.256674n
dV/dt_f   0.779145/0.471471n  0.659063/0.856137n  0.885904/0.317699n
R_load = 50
[Falling Waveform]
R_fixture = 50
V_fixture = 0
V_fixture_min = 0
V_fixture_max = 0
| Time   V(typ)   V(min)   V(max)
0s        1.317V     1.092V     1.497V
921.3ps   1.317V     1.092V     1.484V
1.129ns   1.301V     1.092V     738.1mV
1.431ns   478.9mV    1.089V     80.24mV
1.568ns   267.9mV    981.8mV    22.27mV
1.716ns   107.1mV    582.3mV    5.946mV
2.043ns   9.312mV    183.4mV    685uV
2.491ns   784.2uV    23.84mV    295.1uV
3.467ns   273.5uV    513.8uV    45.51uV
333.3ns   84.17nV    198.8nV    67.42nV
[Falling Waveform]
R_fixture = 50
V_fixture = 1.8
V_fixture_min = 1.65
V_fixture_max = 1.95
| Time   V(typ)   V(min)   V(max)
0s        1.8V       1.65V      1.95V
1.119ns   1.81V      1.65V      1.962V
1.222ns   1.818V     1.65V      1.819V
1.455ns   1.799V     1.657V     1.124V
1.716ns   1.462V     1.666V     607.4mV
2.234ns   680.3mV    1.577V     489.2mV
3.141ns   516.6mV    850.3mV    475.7mV
4.128ns   505mV      595.2mV    473.9mV
7.989ns   501.5mV    552.9mV    473.5mV
333.3ns   501.4mV    551.6mV    473.5mV
[Rising Waveform]
R_fixture = 50
V_fixture = 0
V_fixture_min = 0
V_fixture_max = 0
| Time   V(typ)   V(min)   V(max)
0s        41nV       149.8nV    42.36nV
1.075ns   -1.171mV   -4.672uV   141.8uV
1.208ns   -4.788mV   -50.69uV   243.4mV
1.398ns   4.923mV    -297.8uV   955.7mV
1.611ns   268.2mV    -3.964mV   1.364V
2.065ns   1.124V     40.59mV    1.476V
3.051ns   1.302V     896.1mV    1.495V
4.183ns   1.315V     1.061V     1.496V
7.9ns     1.317V     1.092V     1.497V
333.3ns   1.317V     1.092V     1.497V
[Rising Waveform]
R_fixture = 50
V_fixture = 1.8
V_fixture_min = 1.65
V_fixture_max = 1.95
| Time   V(typ)   V(min)   V(max)
0s        501.4mV    551.6mV    473.5mV
983.5ps   501.2mV    551.5mV    495mV
1.224ns   523.5mV    551.5mV    1.52V
1.268ns   598.2mV    551.5mV    1.671V
1.385ns   1.082V     551.3mV    1.903V
1.685ns   1.727V     592.1mV    1.947V
1.923ns   1.795V     1.213V     1.949V
2.323ns   1.798V     1.621V     1.95V
3.47ns    1.8V       1.649V     1.95V
333.3ns   1.8V       1.65V      1.95V
[Add Submodel]
| Submodel Name Mode
M22_PBIDIR_FS_DR_1_1P80V_T All
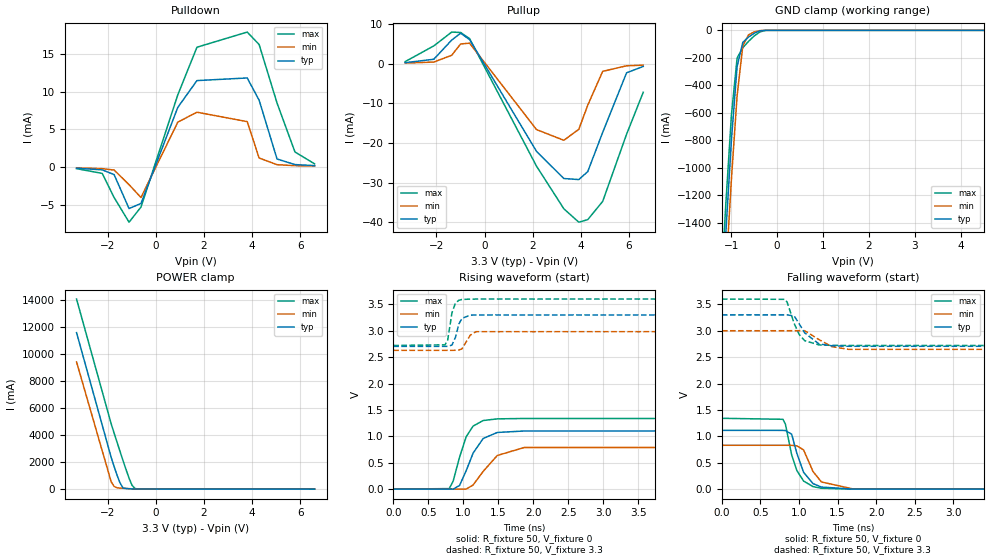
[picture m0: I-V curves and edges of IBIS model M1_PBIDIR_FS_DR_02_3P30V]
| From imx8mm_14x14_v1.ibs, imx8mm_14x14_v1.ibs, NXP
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[Model] M1_PBIDIR_FS_DR_02_3P30V
Model_type I/O
Vinl  =  0.54
Vinh  =  1.26
Vmeas =  0.9
| Capacitance   typ   min   max
C_comp   2.08161232969e-12   2.03493647009e-12   2.16777276051e-12
| Variables   typ   min   max
[GND Clamp Reference]   0   0   0
[POWER Clamp Reference]   3.3   3   3.6
[Pulldown Reference]   0   0   0
[Pullup Reference]   3.3   3   3.6
[Temperature Range]   25   125   -40
[Voltage Range]   3.3   3   3.6
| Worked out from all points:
|   slope of the pulldown table from 0 to 0.495 V, typ, clamps not added: 111 ohm
|   slope of the pullup table from 0 to 0.495 V, typ, clamps not added: 90.9 ohm
|   GND clamp passes 1 mA (typ) near -0.28 V on its own axis
|   POWER clamp passes 1 mA (typ) near -0.44 V on its own axis
|   falling waveform, R_fixture 50, V_fixture 0: 20-80 % time 163ps typ, 180ps min, 156ps max; typ from 1.11 V to 0 V
|   falling waveform, R_fixture 50, V_fixture 3.3: 20-80 % time 175ps typ, 242ps min, 143ps max; typ from 3.3 V to 2.7 V
|   rising waveform, R_fixture 50, V_fixture 0: 20-80 % time 230ps typ, 318ps min, 191ps max; typ from 0 V to 1.11 V
|   rising waveform, R_fixture 50, V_fixture 3.3: 20-80 % time 76.1ps typ, 93.5ps min, 65.6ps max; typ from 2.7 V to 3.3 V
[GND Clamp]
| Voltage   I(typ)   I(min)   I(max)
-3.3V     -15.63A    -15.86A    -15.46A
-1.241V   -2.232A    -2.527A    -2.015A
-1.117V   -1.487A    -1.785A    -1.276A
-993.1mV  -798.9mA   -1.083A    -616.8mA
-869mV    -263.4mA   -475.6mA   -200.8mA
-744.8mV  -87.36mA   -112.1mA   -126.1mA
-620.7mV  -49.17mA   -33.01mA   -80.34mA
-496.6mV  -20.8mA    -11.81mA   -40.7mA
-372.4mV  -3.877mA   -2.002mA   -11.64mA
-248.3mV  -117.5uA   -105.1uA   -542.9uA
6.6V      0A         0A         0A
[POWER Clamp]
| Voltage   I(typ)   I(min)   I(max)
-3.3V     11.6A      9.427A     14.09A
-1.862V   2.37A      558.5mA    4.855A
-1.738V   1.676A     202.6mA    4.157A
-1.614V   1.03A      99.77mA    3.468A
-1.49V    451mA      80.49mA    2.786A
-1.366V   91.11mA    66.06mA    2.111A
-1.241V   43.77mA    52.06mA    1.45A
-1.117V   30.97mA    38.55mA    817.5mA
-993.1mV  20.41mA    25.92mA    286.6mA
-869mV    13.37mA    15.08mA    47.85mA
-744.8mV  8.524mA    7.507mA    13.32mA
6.6V      0A         0A         0A
[Pulldown]
| Voltage   I(typ)   I(min)   I(max)
-3.3V     -168.2uA   -115.7uA   -233.4uA
-2.234V   -392.9uA   -232.7uA   -861.2uA
-1.738V   -1.023mA   -416.8uA   -4.059mA
-1.117V   -5.529mA   -2.354mA   -7.34mA
-620.7mV  -4.853mA   -4.065mA   -5.331mA
910.3mV   7.901mA    5.941mA    9.566mA
1.707V    11.46mA    7.262mA    15.89mA
3.797V    11.81mA    6.011mA    17.9mA
4.293V    8.862mA    1.179mA    16.25mA
5.038V    1.051mA    295.3uA    8.479mA
5.783V    309uA      164uA      1.983mA
6.6V      174uA      109.6uA    405.1uA
[Pullup]
| Voltage   I(typ)   I(min)   I(max)
-3.3V     289.4uA    183.1uA    562.7uA
-2.11V    1.149mA    447.4uA    4.519mA
-1.366V   5.986mA    2.154mA    8.003mA
-993.1mV  7.726mA    5.014mA    7.907mA
-620.7mV  6.113mA    5.204mA    6.351mA
2.162V    -22.08mA   -16.58mA   -25.8mA
3.3V      -28.92mA   -19.28mA   -36.56mA
3.921V    -29.18mA   -16.51mA   -39.93mA
4.293V    -27.18mA   -10.43mA   -39.28mA
4.914V    -17.28mA   -1.899mA   -34.69mA
5.907V    -2.264mA   -494.8uA   -17.76mA
6.6V      -659.9uA   -331.9uA   -7.186mA
[Ramp]
dV/dt_r   0.668087/0.230367n  0.49733/0.318236n  0.805158/0.190549n
dV/dt_f   0.357579/0.174657n  0.222408/0.241737n  0.527482/0.142722n
R_load = 50
[Falling Waveform]
R_fixture = 50
V_fixture = 0
V_fixture_min = 0
V_fixture_max = 0
| Time   V(typ)   V(min)   V(max)
0s        1.114V     831.1mV    1.342V
791.1ps   1.113V     831.1mV    1.323V
824.1ps   1.109V     831.1mV    1.226V
903.9ps   1.042V     830.3mV    650.1mV
972.1ps   676.1mV    819.9mV    350.4mV
1.059ns   318.5mV    743.1mV    153.5mV
1.181ns   104.9mV    334.2mV    48.26mV
1.29ns    39.32mV    136mV      17.2mV
1.697ns   963.9uV    4.684mV    -206.8uV
333.3ns   4.253uV    5.92uV     19.88uV
[Falling Waveform]
R_fixture = 50
V_fixture = 3.3
V_fixture_min = 3
V_fixture_max = 3.6
| Time   V(typ)   V(min)   V(max)
0s        3.3V       3V         3.6V
813.4ps   3.301V     3V         3.595V
845.7ps   3.301V     3V         3.541V
936.9ps   3.279V     3.001V     3.138V
1ns       3.136V     3.001V     2.933V
1.073ns   2.959V     3.001V     2.812V
1.258ns   2.751V     2.833V     2.732V
1.424ns   2.715V     2.7V       2.723V
1.642ns   2.706V     2.647V     2.721V
333.3ns   2.704V     2.629V     2.721V
[Rising Waveform]
R_fixture = 50
V_fixture = 0
V_fixture_min = 0
V_fixture_max = 0
| Time   V(typ)   V(min)   V(max)
0s        4.252uV    5.918uV    19.88uV
800.2ps   -202.7uV   -17.31uV   9.787mV
855.9ps   -817.7uV   -18.93uV   151mV
947.9ps   69.7mV     -390uV     605.9mV
1.043ns   351.8mV    1.137mV    994mV
1.142ns   682.6mV    79.04mV    1.195V
1.285ns   959.3mV    335.7mV    1.299V
1.487ns   1.073V     637mV      1.331V
1.872ns   1.101V     788.2mV    1.338V
333.3ns   1.113V     828.9mV    1.342V
[Rising Waveform]
R_fixture = 50
V_fixture = 3.3
V_fixture_min = 3
V_fixture_max = 3.6
| Time   V(typ)   V(min)   V(max)
0s        2.704V     2.629V     2.721V
739.4ps   2.704V     2.629V     2.733V
777.5ps   2.704V     2.629V     2.819V
839.2ps   2.728V     2.629V     3.34V
889.6ps   2.876V     2.63V      3.525V
937ps     3.125V     2.635V     3.577V
982.3ps   3.235V     2.658V     3.592V
1.101ns   3.295V     2.916V     3.599V
1.182ns   3.299V     2.982V     3.6V
333.3ns   3.3V       3V         3.6V
[Add Submodel]
| Submodel Name Mode
M1_PBIDIR_FS_DR_02_3P30V_T All
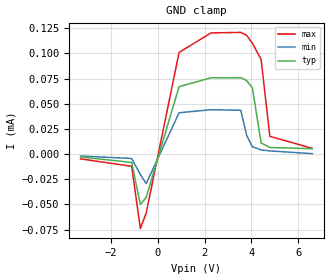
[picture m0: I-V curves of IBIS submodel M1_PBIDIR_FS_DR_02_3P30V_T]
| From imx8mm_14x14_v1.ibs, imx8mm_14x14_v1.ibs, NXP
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| Submodel
[Submodel]  M1_PBIDIR_FS_DR_02_3P30V_T
Submodel_type Dynamic_clamp
[GND Clamp]
| Voltage   I(typ)   I(min)   I(max)
-3.3V     -2.861uA   -1.907uA   -4.768uA
-1.117V   -8.345uA   -4.411uA   -12.16uA
-744.8mV  -50.12uA   -20.38uA   -74.13uA
-496.6mV  -43.09uA   -29.32uA   -58.54uA
910.3mV   66.98uA    41.02uA    101uA
2.276V    75.75uA    44.1uA     120.4uA
3.548V    75.89uA    43.48uA    120.9uA
3.797V    73.03uA    18.7uA     118uA
4.045V    65.72uA    7.207uA    110.1uA
4.417V    11.04uA    4.113uA    93.96uA
4.79V     6.527uA    3.129uA    17.64uA
6.6V      5.325uA    397.4nA    5.722uA
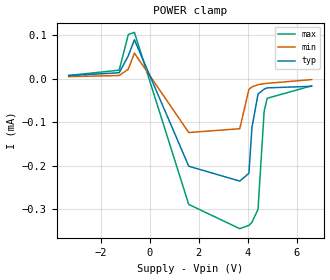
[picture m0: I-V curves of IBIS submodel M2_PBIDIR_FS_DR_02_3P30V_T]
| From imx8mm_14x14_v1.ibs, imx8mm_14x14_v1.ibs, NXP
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| Submodel
[Submodel]  M2_PBIDIR_FS_DR_02_3P30V_T
Submodel_type Dynamic_clamp
[POWER Clamp]
| Voltage   I(typ)   I(min)   I(max)
-3.3V     7.232uA    4.927uA    7.629uA
-1.241V   13.87uA    7.49uA     19.79uA
-869mV    53.01uA    22.09uA    102.2uA
-620.7mV  89.93uA    58.95uA    106.8uA
1.593V    -201.5uA   -123.9uA   -289.5uA
3.672V    -235.7uA   -115.1uA   -345.3uA
4.045V    -217.8uA   -24.47uA   -337.8uA
4.169V    -112.1uA   -18.82uA   -330.7uA
4.417V    -35.29uA   -13.57uA   -300.5uA
4.666V    -23.84uA   -11.25uA   -75.07uA
4.79V     -20.98uA   -10.57uA   -44.93uA
6.6V      -17.32uA   -1.907uA   -16.37uA
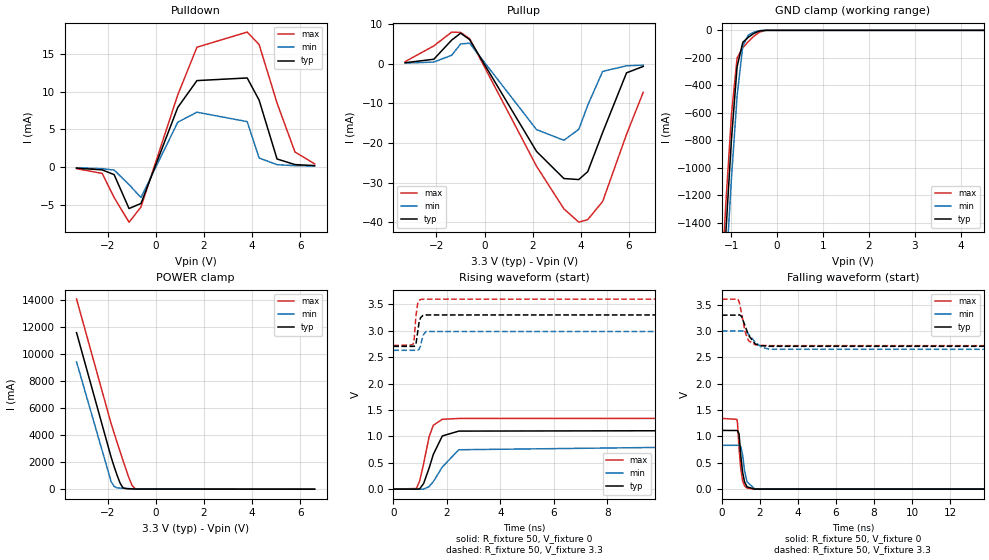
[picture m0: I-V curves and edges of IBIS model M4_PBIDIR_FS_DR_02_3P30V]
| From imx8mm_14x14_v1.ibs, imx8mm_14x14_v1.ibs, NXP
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[Model] M4_PBIDIR_FS_DR_02_3P30V
Model_type I/O
Vinl  =  0.54
Vinh  =  1.26
Vmeas =  0.9
| Capacitance   typ   min   max
C_comp   2.08161232969e-12   2.03493647009e-12   2.16777276051e-12
| Variables   typ   min   max
[GND Clamp Reference]   0   0   0
[POWER Clamp Reference]   3.3   3   3.6
[Pulldown Reference]   0   0   0
[Pullup Reference]   3.3   3   3.6
[Temperature Range]   25   125   -40
[Voltage Range]   3.3   3   3.6
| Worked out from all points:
|   slope of the pulldown table from 0 to 0.495 V, typ, clamps not added: 111 ohm
|   slope of the pullup table from 0 to 0.495 V, typ, clamps not added: 90.9 ohm
|   GND clamp passes 1 mA (typ) near -0.28 V on its own axis
|   POWER clamp passes 1 mA (typ) near -0.44 V on its own axis
|   falling waveform, R_fixture 50, V_fixture 0: 20-80 % time 196ps typ, 213ps min, 184ps max; typ from 1.11 V to 0 V
|   falling waveform, R_fixture 50, V_fixture 3.3: 20-80 % time 399ps typ, 597ps min, 307ps max; typ from 3.3 V to 2.7 V
|   rising waveform, R_fixture 50, V_fixture 0: 20-80 % time 444ps typ, 665ps min, 340ps max; typ from 0 V to 1.11 V
|   rising waveform, R_fixture 50, V_fixture 3.3: 20-80 % time 97.4ps typ, 110ps min, 86.8ps max; typ from 2.7 V to 3.3 V
[GND Clamp]
| Voltage   I(typ)   I(min)   I(max)
-3.3V     -15.63A    -15.86A    -15.46A
-1.241V   -2.232A    -2.527A    -2.015A
-1.117V   -1.487A    -1.785A    -1.276A
-993.1mV  -798.9mA   -1.083A    -616.8mA
-869mV    -263.4mA   -475.6mA   -200.8mA
-744.8mV  -87.36mA   -112.1mA   -126.1mA
-620.7mV  -49.17mA   -33.01mA   -80.34mA
-496.6mV  -20.8mA    -11.81mA   -40.7mA
-372.4mV  -3.877mA   -2.002mA   -11.64mA
-248.3mV  -117.5uA   -105.1uA   -542.9uA
6.6V      0A         0A         0A
[POWER Clamp]
| Voltage   I(typ)   I(min)   I(max)
-3.3V     11.6A      9.427A     14.09A
-1.862V   2.37A      558.5mA    4.855A
-1.738V   1.676A     202.6mA    4.157A
-1.614V   1.03A      99.77mA    3.468A
-1.49V    451mA      80.49mA    2.786A
-1.366V   91.11mA    66.06mA    2.111A
-1.241V   43.77mA    52.06mA    1.45A
-1.117V   30.97mA    38.55mA    817.5mA
-993.1mV  20.41mA    25.92mA    286.6mA
-869mV    13.37mA    15.08mA    47.85mA
-744.8mV  8.524mA    7.507mA    13.32mA
6.6V      0A         0A         0A
[Pulldown]
| Voltage   I(typ)   I(min)   I(max)
-3.3V     -168.2uA   -115.7uA   -233.4uA
-2.234V   -392.9uA   -232.7uA   -861.2uA
-1.738V   -1.023mA   -416.8uA   -4.059mA
-1.117V   -5.529mA   -2.354mA   -7.34mA
-620.7mV  -4.853mA   -4.065mA   -5.331mA
910.3mV   7.901mA    5.941mA    9.566mA
1.707V    11.46mA    7.262mA    15.89mA
3.797V    11.81mA    6.011mA    17.9mA
4.293V    8.862mA    1.179mA    16.25mA
5.038V    1.051mA    295.3uA    8.479mA
5.783V    309uA      164uA      1.983mA
6.6V      174uA      109.6uA    405.1uA
[Pullup]
| Voltage   I(typ)   I(min)   I(max)
-3.3V     289.4uA    183.1uA    562.7uA
-2.11V    1.149mA    447.4uA    4.519mA
-1.366V   5.986mA    2.154mA    8.003mA
-993.1mV  7.726mA    5.014mA    7.907mA
-620.7mV  6.113mA    5.204mA    6.351mA
2.162V    -22.08mA   -16.58mA   -25.8mA
3.3V      -28.92mA   -19.28mA   -36.56mA
3.921V    -29.18mA   -16.51mA   -39.93mA
4.293V    -27.18mA   -10.43mA   -39.28mA
4.914V    -17.28mA   -1.899mA   -34.69mA
5.907V    -2.264mA   -494.8uA   -17.76mA
6.6V      -659.9uA   -331.9uA   -7.186mA
[Ramp]
dV/dt_r   0.668086/0.444198n  0.497326/0.66459n  0.805158/0.340175n
dV/dt_f   0.357579/0.399179n  0.222408/0.597433n  0.527482/0.306558n
R_load = 50
[Falling Waveform]
R_fixture = 50
V_fixture = 0
V_fixture_min = 0
V_fixture_max = 0
| Time   V(typ)   V(min)   V(max)
0s        1.114V     831.1mV    1.342V
789.1ps   1.113V     831.1mV    1.324V
821.7ps   1.11V      831.1mV    1.246V
901.6ps   1.047V     830.5mV    768.8mV
990.8ps   640mV      813.1mV    388.9mV
1.09ns    318.4mV    650mV      159.2mV
1.191ns   137.3mV    346.4mV    62.98mV
1.325ns   42.95mV    137.7mV    18.33mV
1.721ns   1.535mV    6.552mV    588.1uV
333.3ns   4.253uV    5.921uV    19.88uV
[Falling Waveform]
R_fixture = 50
V_fixture = 3.3
V_fixture_min = 3
V_fixture_max = 3.6
| Time   V(typ)   V(min)   V(max)
0s        3.3V       3V         3.6V
847ps     3.301V     3V         3.605V
931.9ps   3.306V     3.001V     3.519V
1.039ns   3.271V     3.002V     3.32V
1.226ns   3.09V      2.995V     2.978V
1.398ns   2.919V     2.941V     2.817V
1.75ns    2.755V     2.787V     2.739V
2.075ns   2.721V     2.695V     2.726V
2.498ns   2.709V     2.653V     2.722V
333.3ns   2.704V     2.629V     2.721V
[Rising Waveform]
R_fixture = 50
V_fixture = 0
V_fixture_min = 0
V_fixture_max = 0
| Time   V(typ)   V(min)   V(max)
0s        4.252uV    5.918uV    19.88uV
865.3ps   -1.007mV   -7.07uV    11.24mV
984.4ps   4.532mV    -699.4uV   152.2mV
1.134ns   105.7mV    -1.04mV    481.2mV
1.337ns   395.1mV    47.52mV    989.5mV
1.496ns   657.4mV    141.2mV    1.209V
1.833ns   1.007V     419.7mV    1.323V
2.447ns   1.099V     745.7mV    1.338V
15.15ns   1.11V      820.8mV    1.341V
333.3ns   1.113V     828.9mV    1.342V
[Rising Waveform]
R_fixture = 50
V_fixture = 3.3
V_fixture_min = 3
V_fixture_max = 3.6
| Time   V(typ)   V(min)   V(max)
0s        2.704V     2.629V     2.721V
735.2ps   2.704V     2.629V     2.732V
781.6ps   2.705V     2.629V     2.842V
845.5ps   2.739V     2.629V     3.274V
914.3ps   2.987V     2.632V     3.519V
960.9ps   3.149V     2.645V     3.571V
1.02ns    3.247V     2.719V     3.592V
1.111ns   3.291V     2.913V     3.598V
1.223ns   3.299V     2.985V     3.599V
333.3ns   3.3V       3V         3.6V
[Add Submodel]
| Submodel Name Mode
M4_PBIDIR_FS_DR_02_3P30V_T All
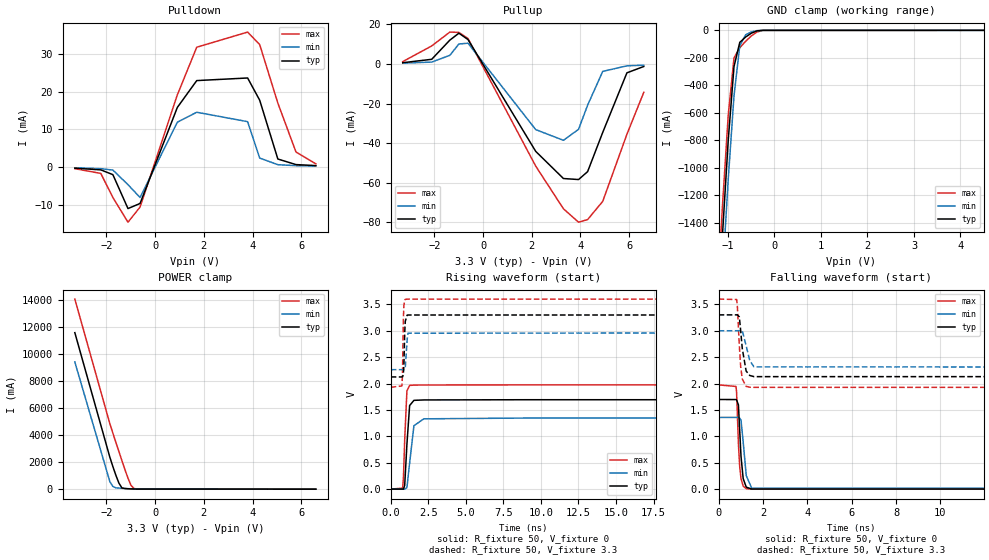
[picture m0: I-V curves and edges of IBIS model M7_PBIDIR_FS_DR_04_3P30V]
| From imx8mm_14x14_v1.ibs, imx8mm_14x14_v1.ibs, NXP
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[Model] M7_PBIDIR_FS_DR_04_3P30V
Model_type I/O
Vinl  =  0.54
Vinh  =  1.26
Vmeas =  0.9
| Capacitance   typ   min   max
C_comp   2.08161232969e-12   2.03493647009e-12   2.16777276051e-12
| Variables   typ   min   max
[GND Clamp Reference]   0   0   0
[POWER Clamp Reference]   3.3   3   3.6
[Pulldown Reference]   0   0   0
[Pullup Reference]   3.3   3   3.6
[Temperature Range]   25   125   -40
[Voltage Range]   3.3   3   3.6
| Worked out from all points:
|   slope of the pulldown table from 0 to 0.495 V, typ, clamps not added: 55.3 ohm
|   slope of the pullup table from 0 to 0.495 V, typ, clamps not added: 45.4 ohm
|   GND clamp passes 1 mA (typ) near -0.28 V on its own axis
|   POWER clamp passes 1 mA (typ) near -0.44 V on its own axis
|   falling waveform, R_fixture 50, V_fixture 0: 20-80 % time 141ps typ, 162ps min, 128ps max; typ from 1.7 V to 0 V
|   falling waveform, R_fixture 50, V_fixture 3.3: 20-80 % time 179ps typ, 252ps min, 137ps max; typ from 3.3 V to 2.12 V
|   rising waveform, R_fixture 50, V_fixture 0: 20-80 % time 184ps typ, 272ps min, 146ps max; typ from 0 V to 1.7 V
|   rising waveform, R_fixture 50, V_fixture 3.3: 20-80 % time 67.9ps typ, 86.8ps min, 55.8ps max; typ from 2.12 V to 3.3 V
[GND Clamp]
| Voltage   I(typ)   I(min)   I(max)
-3.3V     -15.63A    -15.86A    -15.46A
-1.241V   -2.232A    -2.527A    -2.015A
-1.117V   -1.487A    -1.785A    -1.276A
-993.1mV  -798.9mA   -1.083A    -616.8mA
-869mV    -263.4mA   -475.6mA   -200.8mA
-744.8mV  -87.36mA   -112.1mA   -126.1mA
-620.7mV  -49.17mA   -33.01mA   -80.34mA
-496.6mV  -20.8mA    -11.81mA   -40.7mA
-372.4mV  -3.877mA   -2.002mA   -11.64mA
-248.3mV  -117.5uA   -105.1uA   -542.9uA
6.6V      0A         0A         0A
[POWER Clamp]
| Voltage   I(typ)   I(min)   I(max)
-3.3V     11.6A      9.427A     14.09A
-1.862V   2.37A      558.5mA    4.855A
-1.738V   1.676A     202.6mA    4.157A
-1.614V   1.03A      99.77mA    3.468A
-1.49V    451mA      80.49mA    2.786A
-1.366V   91.11mA    66.06mA    2.111A
-1.241V   43.77mA    52.06mA    1.45A
-1.117V   30.97mA    38.55mA    817.5mA
-993.1mV  20.41mA    25.92mA    286.6mA
-869mV    13.37mA    15.08mA    47.85mA
-744.8mV  8.524mA    7.507mA    13.32mA
6.6V      0A         0A         0A
[Pulldown]
| Voltage   I(typ)   I(min)   I(max)
-3.3V     -336.6uA   -232.9uA   -466.4uA
-2.234V   -784.9uA   -464.4uA   -1.722mA
-1.738V   -2.046mA   -833.5uA   -8.118mA
-1.117V   -11.06mA   -4.708mA   -14.68mA
-620.7mV  -9.706mA   -8.13mA    -10.66mA
910.3mV   15.8mA     11.88mA    19.13mA
1.707V    22.93mA    14.52mA    31.79mA
3.797V    23.62mA    12.02mA    35.81mA
4.293V    17.72mA    2.358mA    32.49mA
5.038V    2.102mA    590.4uA    16.96mA
5.783V    618uA      327.6uA    3.967mA
6.6V      348.1uA    218.8uA    811.1uA
[Pullup]
| Voltage   I(typ)   I(min)   I(max)
-3.3V     583.1uA    366.4uA    1.137mA
-2.11V    2.303mA    895.4uA    9.049mA
-1.366V   11.98mA    4.309mA    16.03mA
-993.1mV  15.47mA    10.03mA    15.88mA
-620.7mV  12.26mA    10.41mA    12.81mA
2.162V    -44.15mA   -33.17mA   -51.6mA
3.3V      -57.84mA   -38.56mA   -73.11mA
3.921V    -58.36mA   -33.01mA   -79.87mA
4.293V    -54.37mA   -20.86mA   -78.55mA
4.914V    -34.57mA   -3.798mA   -69.37mA
5.907V    -4.528mA   -989.6uA   -35.53mA
6.6V      -1.319mA   -661.9uA   -14.37mA
[Ramp]
dV/dt_r   1.01838/0.184428n  0.813732/0.272057n  1.18486/0.146251n
dV/dt_f   0.70522/0.179105n  0.442179/0.251859n  1.0031/0.137248n
R_load = 50
[Falling Waveform]
R_fixture = 50
V_fixture = 0
V_fixture_min = 0
V_fixture_max = 0
| Time   V(typ)   V(min)   V(max)
0s        1.698V     1.359V     1.975V
784.1ps   1.697V     1.359V     1.945V
810.1ps   1.692V     1.359V     1.837V
892.9ps   1.595V     1.358V     860.7mV
948.6ps   1.127V     1.346V     435.5mV
1.01ns    620.3mV    1.306V     199.5mV
1.108ns   199.3mV    894.5mV    56.94mV
1.246ns   38.2mV     255.7mV    9.815mV
1.494ns   2.058mV    18.9mV     216.9uV
333.3ns   2.948uV    4.354uV    13.11uV
[Falling Waveform]
R_fixture = 50
V_fixture = 3.3
V_fixture_min = 3
V_fixture_max = 3.6
| Time   V(typ)   V(min)   V(max)
0s        3.3V       3V         3.6V
812.1ps   3.301V     3V         3.591V
845.5ps   3.302V     3V         3.469V
932.7ps   3.263V     3.001V     2.728V
995.2ps   3.003V     3.002V     2.321V
1.066ns   2.666V     3.004V     2.087V
1.24ns    2.238V     2.719V     1.946V
1.404ns   2.153V     2.437V     1.931V
1.594ns   2.131V     2.316V     1.928V
333.3ns   2.125V     2.263V     1.928V
[Rising Waveform]
R_fixture = 50
V_fixture = 0
V_fixture_min = 0
V_fixture_max = 0
| Time   V(typ)   V(min)   V(max)
0s        2.947uV    4.353uV    13.11uV
799.2ps   -496.6uV   9.322uV    17.81mV
851.9ps   -1.447mV   -17.68uV   241.9mV
933.1ps   75.75mV    -599.3uV   937.3mV
1.08ns    850mV      28.75mV    1.859V
1.26ns    1.583V     494.5mV    1.964V
1.546ns   1.681V     1.201V     1.97V
2.206ns   1.689V     1.331V     1.972V
9.029ns   1.693V     1.346V     1.974V
333.3ns   1.697V     1.356V     1.975V
[Rising Waveform]
R_fixture = 50
V_fixture = 3.3
V_fixture_min = 3
V_fixture_max = 3.6
| Time   V(typ)   V(min)   V(max)
0s        2.125V     2.263V     1.928V
746ps     2.124V     2.263V     1.954V
783.4ps   2.126V     2.263V     2.147V
841.6ps   2.173V     2.263V     3.19V
877.1ps   2.34V      2.263V     3.477V
934.7ps   2.967V     2.273V     3.583V
970.1ps   3.177V     2.3V       3.594V
1.095ns   3.296V     2.832V     3.599V
1.152ns   3.298V     2.954V     3.599V
333.3ns   3.3V       3V         3.6V
[Add Submodel]
| Submodel Name Mode
M7_PBIDIR_FS_DR_04_3P30V_T All
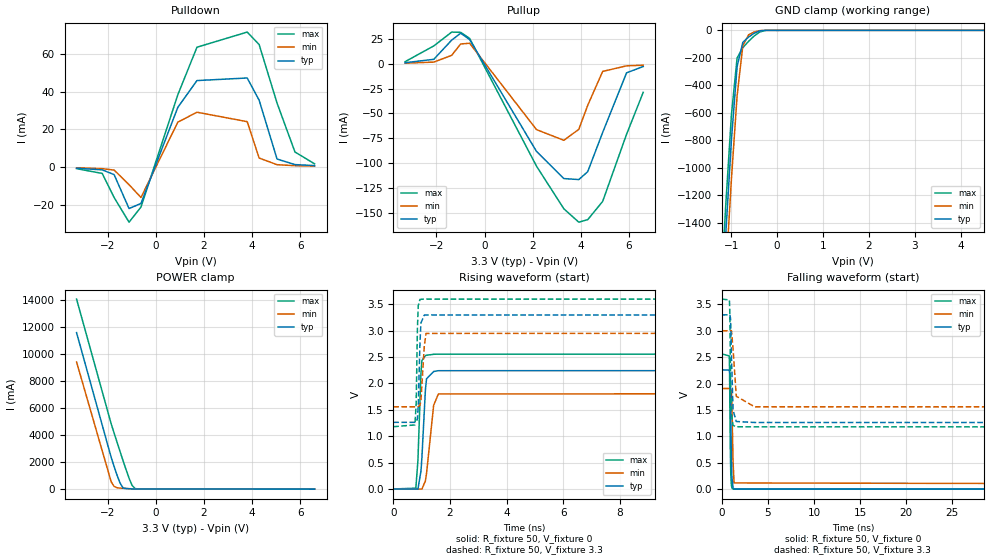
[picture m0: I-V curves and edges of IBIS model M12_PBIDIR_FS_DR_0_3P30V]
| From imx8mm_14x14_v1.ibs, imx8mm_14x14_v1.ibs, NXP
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[Model] M12_PBIDIR_FS_DR_0_3P30V
Model_type I/O
Vinl  =  0.54
Vinh  =  1.26
Vmeas =  0.9
| Capacitance   typ   min   max
C_comp   2.08161232969e-12   2.03493647009e-12   2.16777276051e-12
| Variables   typ   min   max
[GND Clamp Reference]   0   0   0
[POWER Clamp Reference]   3.3   3   3.6
[Pulldown Reference]   0   0   0
[Pullup Reference]   3.3   3   3.6
[Temperature Range]   25   125   -40
[Voltage Range]   3.3   3   3.6
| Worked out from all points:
|   slope of the pulldown table from 0 to 0.495 V, typ, clamps not added: 27.7 ohm
|   slope of the pullup table from 0 to 0.495 V, typ, clamps not added: 22.7 ohm
|   GND clamp passes 1 mA (typ) near -0.28 V on its own axis
|   POWER clamp passes 1 mA (typ) near -0.44 V on its own axis
|   falling waveform, R_fixture 50, V_fixture 0: 20-80 % time 110ps typ, 144ps min, 92.6ps max; typ from 2.26 V to 0 V
|   falling waveform, R_fixture 50, V_fixture 3.3: 20-80 % time 170ps typ, 298ps min, 104ps max; typ from 3.3 V to 1.26 V
|   rising waveform, R_fixture 50, V_fixture 0: 20-80 % time 134ps typ, 215ps min, 100ps max; typ from 0 V to 2.26 V
|   rising waveform, R_fixture 50, V_fixture 3.3: 20-80 % time 62.6ps typ, 88.8ps min, 44.5ps max; typ from 1.26 V to 3.3 V
[GND Clamp]
| Voltage   I(typ)   I(min)   I(max)
-3.3V     -15.63A    -15.86A    -15.46A
-1.241V   -2.232A    -2.527A    -2.015A
-1.117V   -1.487A    -1.785A    -1.276A
-993.1mV  -798.9mA   -1.083A    -616.8mA
-869mV    -263.4mA   -475.6mA   -200.8mA
-744.8mV  -87.36mA   -112.1mA   -126.1mA
-620.7mV  -49.17mA   -33.01mA   -80.34mA
-496.6mV  -20.8mA    -11.81mA   -40.7mA
-372.4mV  -3.877mA   -2.002mA   -11.64mA
-248.3mV  -117.5uA   -105.1uA   -542.9uA
6.6V      0A         0A         0A
[POWER Clamp]
| Voltage   I(typ)   I(min)   I(max)
-3.3V     11.6A      9.427A     14.09A
-1.862V   2.37A      558.5mA    4.855A
-1.738V   1.676A     202.6mA    4.157A
-1.614V   1.03A      99.77mA    3.468A
-1.49V    451mA      80.49mA    2.786A
-1.366V   91.11mA    66.06mA    2.111A
-1.241V   43.77mA    52.06mA    1.45A
-1.117V   30.97mA    38.55mA    817.5mA
-993.1mV  20.41mA    25.92mA    286.6mA
-869mV    13.37mA    15.08mA    47.85mA
-744.8mV  8.524mA    7.507mA    13.32mA
6.6V      0A         0A         0A
[Pulldown]
| Voltage   I(typ)   I(min)   I(max)
-3.3V     -672.7uA   -465.5uA   -932.9uA
-2.234V   -1.57mA    -928.9uA   -3.446mA
-1.738V   -4.091mA   -1.667mA   -16.24mA
-1.117V   -22.12mA   -9.416mA   -29.36mA
-620.7mV  -19.41mA   -16.26mA   -21.32mA
910.3mV   31.6mA     23.76mA    38.26mA
1.707V    45.86mA    29.05mA    63.57mA
3.797V    47.23mA    24.04mA    71.61mA
4.293V    35.45mA    4.716mA    64.99mA
5.038V    4.203mA    1.181mA    33.92mA
5.783V    1.236mA    655.2uA    7.934mA
6.6V      695.6uA    437.2uA    1.622mA
[Pullup]
| Voltage   I(typ)   I(min)   I(max)
-3.3V     1.17mA     733.5uA    2.285mA
-2.11V    4.606mA    1.79mA     18.1mA
-1.366V   23.96mA    8.612mA    32.07mA
-993.1mV  30.95mA    20.06mA    31.83mA
-620.7mV  24.56mA    20.83mA    25.73mA
2.162V    -88.3mA    -66.33mA   -103.2mA
3.3V      -115.7mA   -77.12mA   -146.2mA
3.921V    -116.7mA   -66.02mA   -159.7mA
4.293V    -108.7mA   -41.71mA   -157.1mA
4.914V    -69.11mA   -7.597mA   -138.7mA
5.907V    -9.041mA   -1.98mA    -71.01mA
6.6V      -2.636mA   -1.322mA   -28.72mA
[Ramp]
dV/dt_r   1.3551/0.133813n  1.14241/0.214621n  1.53591/0.100137n
dV/dt_f   1.22226/0.169662n  0.864984/0.297642n  1.45186/0.103781n
R_load = 50
[Falling Waveform]
R_fixture = 50
V_fixture = 0
V_fixture_min = 0
V_fixture_max = 0
| Time   V(typ)   V(min)   V(max)
0s        2.259V     1.906V     2.56V
796.4ps   2.257V     1.906V     2.524V
824.8ps   2.251V     1.906V     2.326V
904.7ps   2.149V     1.904V     833.2mV
964.6ps   1.3V       1.89V      271.3mV
1.032ns   552.4mV    1.838V     72.48mV
1.085ns   225.8mV    1.588V     26.12mV
1.21ns    25.51mV    525.2mV    2.653mV
1.318ns   4.372mV    117.7mV    454.9uV
333.3ns   1.608uV    2.624uV    6.54uV
[Falling Waveform]
R_fixture = 50
V_fixture = 3.3
V_fixture_min = 3
V_fixture_max = 3.6
| Time   V(typ)   V(min)   V(max)
0s        3.3V       3V         3.6V
815.2ps   3.302V     3V         3.582V
858.9ps   3.303V     3V         3.324V
938.9ps   3.23V      3.002V     2.119V
979.4ps   2.991V     3.002V     1.651V
1.037ns   2.498V     3.005V     1.429V
1.21ns    1.497V     2.659V     1.208V
1.561ns   1.281V     1.76V      1.182V
3.551ns   1.263V     1.559V     1.18V
333.3ns   1.263V     1.558V     1.18V
[Rising Waveform]
R_fixture = 50
V_fixture = 0
V_fixture_min = 0
V_fixture_max = 0
| Time   V(typ)   V(min)   V(max)
0s        1.608uV    2.624uV    6.54uV
796ps     -777.9uV   452.7nV    14.78mV
869.4ps   -3.891mV   -163.9uV   534.5mV
976.3ps   334.6mV    -2.5mV     2.188V
1.01ns    593.4mV    -3.596mV   2.433V
1.133ns   1.873V     152.3mV    2.528V
1.173ns   2.088V     290.2mV    2.535V
1.425ns   2.227V     1.587V     2.553V
1.592ns   2.242V     1.801V     2.556V
333.3ns   2.259V     1.904V     2.56V
[Rising Waveform]
R_fixture = 50
V_fixture = 3.3
V_fixture_min = 3
V_fixture_max = 3.6
| Time   V(typ)   V(min)   V(max)
0s        1.263V     1.558V     1.18V
764.2ps   1.263V     1.558V     1.214V
808.2ps   1.271V     1.558V     1.619V
850.8ps   1.331V     1.558V     3.022V
881.1ps   1.567V     1.559V     3.474V
940.3ps   2.746V     1.589V     3.592V
975ps     3.144V     1.666V     3.596V
1.095ns   3.296V     2.712V     3.598V
1.155ns   3.298V     2.948V     3.599V
333.3ns   3.3V       3V         3.6V
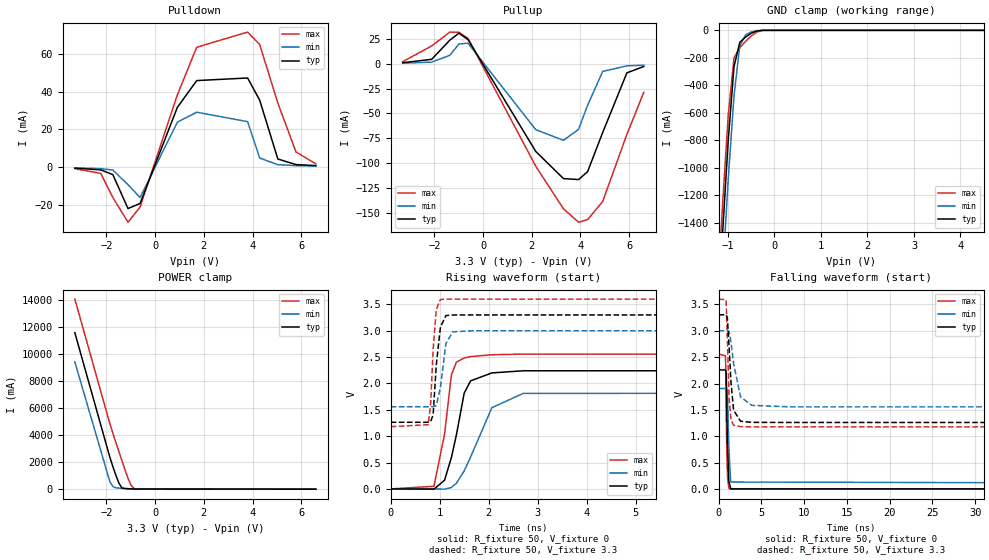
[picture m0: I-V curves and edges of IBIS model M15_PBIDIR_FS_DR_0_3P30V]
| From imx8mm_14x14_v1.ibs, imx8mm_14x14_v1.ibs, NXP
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[Model] M15_PBIDIR_FS_DR_0_3P30V
Model_type I/O
Vinl  =  0.54
Vinh  =  1.26
Vmeas =  0.9
| Capacitance   typ   min   max
C_comp   2.08161232969e-12   2.03493647009e-12   2.16777276051e-12
| Variables   typ   min   max
[GND Clamp Reference]   0   0   0
[POWER Clamp Reference]   3.3   3   3.6
[Pulldown Reference]   0   0   0
[Pullup Reference]   3.3   3   3.6
[Temperature Range]   25   125   -40
[Voltage Range]   3.3   3   3.6
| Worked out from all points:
|   slope of the pulldown table from 0 to 0.495 V, typ, clamps not added: 27.7 ohm
|   slope of the pullup table from 0 to 0.495 V, typ, clamps not added: 22.7 ohm
|   GND clamp passes 1 mA (typ) near -0.28 V on its own axis
|   POWER clamp passes 1 mA (typ) near -0.44 V on its own axis
|   falling waveform, R_fixture 50, V_fixture 0: 20-80 % time 172ps typ, 208ps min, 144ps max; typ from 2.26 V to 0 V
|   falling waveform, R_fixture 50, V_fixture 3.3: 20-80 % time 446ps typ, 834ps min, 264ps max; typ from 3.3 V to 1.26 V
|   rising waveform, R_fixture 50, V_fixture 0: 20-80 % time 298ps typ, 529ps min, 211ps max; typ from 0 V to 2.26 V
|   rising waveform, R_fixture 50, V_fixture 3.3: 20-80 % time 95.5ps typ, 109ps min, 80.6ps max; typ from 1.26 V to 3.3 V
[GND Clamp]
| Voltage   I(typ)   I(min)   I(max)
-3.3V     -15.63A    -15.86A    -15.46A
-1.241V   -2.232A    -2.527A    -2.015A
-1.117V   -1.487A    -1.785A    -1.276A
-993.1mV  -798.9mA   -1.083A    -616.8mA
-869mV    -263.4mA   -475.6mA   -200.8mA
-744.8mV  -87.36mA   -112.1mA   -126.1mA
-620.7mV  -49.17mA   -33.01mA   -80.34mA
-496.6mV  -20.8mA    -11.81mA   -40.7mA
-372.4mV  -3.877mA   -2.002mA   -11.64mA
-248.3mV  -117.5uA   -105.1uA   -542.9uA
6.6V      0A         0A         0A
[POWER Clamp]
| Voltage   I(typ)   I(min)   I(max)
-3.3V     11.6A      9.427A     14.09A
-1.862V   2.37A      558.5mA    4.855A
-1.738V   1.676A     202.6mA    4.157A
-1.614V   1.03A      99.77mA    3.468A
-1.49V    451mA      80.49mA    2.786A
-1.366V   91.11mA    66.06mA    2.111A
-1.241V   43.77mA    52.06mA    1.45A
-1.117V   30.97mA    38.55mA    817.5mA
-993.1mV  20.41mA    25.92mA    286.6mA
-869mV    13.37mA    15.08mA    47.85mA
-744.8mV  8.524mA    7.507mA    13.32mA
6.6V      0A         0A         0A
[Pulldown]
| Voltage   I(typ)   I(min)   I(max)
-3.3V     -672.7uA   -465.5uA   -932.9uA
-2.234V   -1.57mA    -928.9uA   -3.446mA
-1.738V   -4.091mA   -1.667mA   -16.24mA
-1.117V   -22.12mA   -9.416mA   -29.36mA
-620.7mV  -19.41mA   -16.26mA   -21.32mA
910.3mV   31.6mA     23.76mA    38.26mA
1.707V    45.86mA    29.05mA    63.57mA
3.797V    47.23mA    24.04mA    71.61mA
4.293V    35.45mA    4.716mA    64.99mA
5.038V    4.203mA    1.181mA    33.92mA
5.783V    1.236mA    655.2uA    7.934mA
6.6V      695.6uA    437.2uA    1.622mA
[Pullup]
| Voltage   I(typ)   I(min)   I(max)
-3.3V     1.17mA     733.5uA    2.285mA
-2.11V    4.606mA    1.79mA     18.1mA
-1.366V   23.96mA    8.612mA    32.07mA
-993.1mV  30.95mA    20.06mA    31.83mA
-620.7mV  24.56mA    20.83mA    25.73mA
2.162V    -88.3mA    -66.33mA   -103.2mA
3.3V      -115.7mA   -77.12mA   -146.2mA
3.921V    -116.7mA   -66.02mA   -159.7mA
4.293V    -108.7mA   -41.71mA   -157.1mA
4.914V    -69.11mA   -7.597mA   -138.7mA
5.907V    -9.041mA   -1.98mA    -71.01mA
6.6V      -2.636mA   -1.322mA   -28.72mA
[Ramp]
dV/dt_r   1.3551/0.298003n  1.14241/0.528648n  1.53591/0.210731n
dV/dt_f   1.22226/0.445613n  0.864984/0.833622n  1.45186/0.263738n
R_load = 50
[Falling Waveform]
R_fixture = 50
V_fixture = 0
V_fixture_min = 0
V_fixture_max = 0
| Time   V(typ)   V(min)   V(max)
0s        2.259V     1.906V     2.56V
798.3ps   2.257V     1.906V     2.525V
827.1ps   2.25V      1.906V     2.36V
867.4ps   2.231V     1.906V     1.601V
907.2ps   2.145V     1.904V     1.21V
967.2ps   1.382V     1.889V     688.5mV
1.041ns   840.8mV    1.821V     234.5mV
1.192ns   158.3mV    806.8mV    16.65mV
1.413ns   5.957mV    135.2mV    740.5uV
333.3ns   1.608uV    2.624uV    6.54uV
[Falling Waveform]
R_fixture = 50
V_fixture = 3.3
V_fixture_min = 3
V_fixture_max = 3.6
| Time   V(typ)   V(min)   V(max)
0s        3.3V       3V         3.6V
864.7ps   3.304V     3V         3.587V
1.024ns   3.247V     3.004V     2.861V
1.23ns    2.688V     2.99V      1.708V
1.451ns   2.017V     2.78V      1.317V
1.755ns   1.493V     2.374V     1.211V
2.571ns   1.286V     1.746V     1.184V
3.875ns   1.265V     1.587V     1.18V
8.282ns   1.263V     1.559V     1.18V
333.3ns   1.263V     1.558V     1.18V
[Rising Waveform]
R_fixture = 50
V_fixture = 0
V_fixture_min = 0
V_fixture_max = 0
| Time   V(typ)   V(min)   V(max)
0s        1.608uV    2.624uV    6.54uV
881.8ps   -5.032mV   -262.7uV   48.48mV
1.098ns   162.8mV    -5.611mV   1.034V
1.238ns   593.4mV    26.55mV    2.16V
1.339ns   1.018V     106.5mV    2.404V
1.499ns   1.815V     340.5mV    2.482V
1.63ns    2.049V     604.7mV    2.509V
2.064ns   2.199V     1.54V      2.544V
2.704ns   2.24V      1.811V     2.556V
333.3ns   2.259V     1.904V     2.56V
[Rising Waveform]
R_fixture = 50
V_fixture = 3.3
V_fixture_min = 3
V_fixture_max = 3.6
| Time   V(typ)   V(min)   V(max)
0s        1.263V     1.558V     1.18V
765ps     1.263V     1.558V     1.217V
814.8ps   1.274V     1.558V     1.609V
866.2ps   1.409V     1.558V     2.648V
929.5ps   2.344V     1.578V     3.402V
1.014ns   3.067V     1.919V     3.592V
1.126ns   3.287V     2.756V     3.598V
1.265ns   3.298V     2.979V     3.599V
1.696ns   3.299V     2.999V     3.599V
333.3ns   3.3V       3V         3.6V
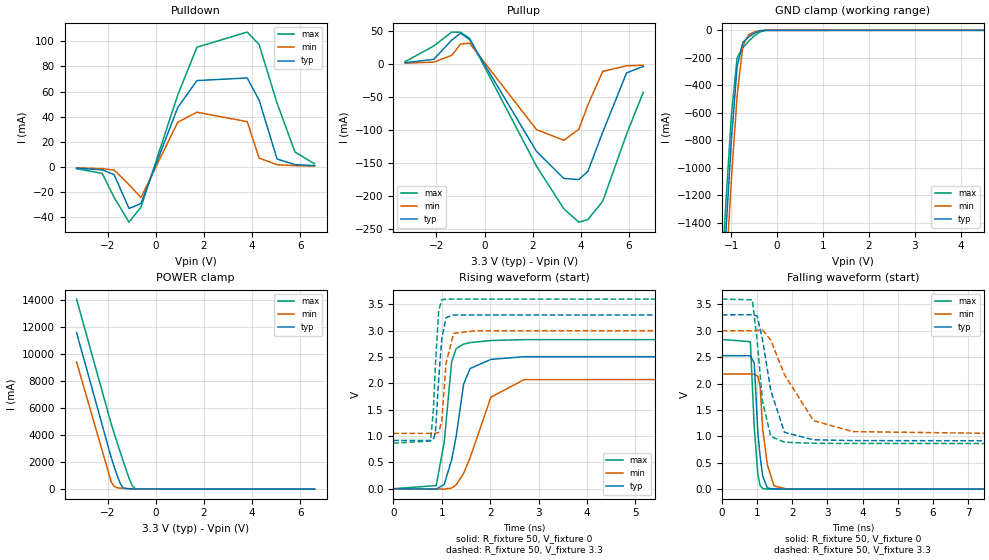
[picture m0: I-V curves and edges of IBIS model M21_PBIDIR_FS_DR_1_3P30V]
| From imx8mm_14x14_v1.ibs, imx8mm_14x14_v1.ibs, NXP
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[Model] M21_PBIDIR_FS_DR_1_3P30V
Model_type I/O
Vinl  =  0.54
Vinh  =  1.26
Vmeas =  0.9
| Capacitance   typ   min   max
C_comp   2.08161232969e-12   2.03493647009e-12   2.16777276051e-12
| Variables   typ   min   max
[GND Clamp Reference]   0   0   0
[POWER Clamp Reference]   3.3   3   3.6
[Pulldown Reference]   0   0   0
[Pullup Reference]   3.3   3   3.6
[Temperature Range]   25   125   -40
[Voltage Range]   3.3   3   3.6
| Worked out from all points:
|   slope of the pulldown table from 0 to 0.495 V, typ, clamps not added: 18.4 ohm
|   slope of the pullup table from 0 to 0.495 V, typ, clamps not added: 15.2 ohm
|   GND clamp passes 1 mA (typ) near -0.28 V on its own axis
|   POWER clamp passes 1 mA (typ) near -0.44 V on its own axis
|   falling waveform, R_fixture 50, V_fixture 0: 20-80 % time 155ps typ, 191ps min, 128ps max; typ from 2.53 V to 0 V
|   falling waveform, R_fixture 50, V_fixture 3.3: 20-80 % time 401ps typ, 823ps min, 253ps max; typ from 3.3 V to 0.916 V
|   rising waveform, R_fixture 50, V_fixture 0: 20-80 % time 266ps typ, 498ps min, 183ps max; typ from 0 V to 2.53 V
|   rising waveform, R_fixture 50, V_fixture 3.3: 20-80 % time 96.7ps typ, 105ps min, 86.4ps max; typ from 0.916 V to 3.3 V
[GND Clamp]
| Voltage   I(typ)   I(min)   I(max)
-3.3V     -15.63A    -15.86A    -15.46A
-1.241V   -2.232A    -2.527A    -2.015A
-1.117V   -1.487A    -1.785A    -1.276A
-993.1mV  -798.9mA   -1.083A    -616.8mA
-869mV    -263.4mA   -475.6mA   -200.8mA
-744.8mV  -87.36mA   -112.1mA   -126.1mA
-620.7mV  -49.17mA   -33.01mA   -80.34mA
-496.6mV  -20.8mA    -11.81mA   -40.7mA
-372.4mV  -3.877mA   -2.002mA   -11.64mA
-248.3mV  -117.5uA   -105.1uA   -542.9uA
6.6V      0A         0A         0A
[POWER Clamp]
| Voltage   I(typ)   I(min)   I(max)
-3.3V     11.6A      9.427A     14.09A
-1.862V   2.37A      558.5mA    4.855A
-1.738V   1.676A     202.6mA    4.157A
-1.614V   1.03A      99.77mA    3.468A
-1.49V    451mA      80.49mA    2.786A
-1.366V   91.11mA    66.06mA    2.111A
-1.241V   43.77mA    52.06mA    1.45A
-1.117V   30.97mA    38.55mA    817.5mA
-993.1mV  20.41mA    25.92mA    286.6mA
-869mV    13.37mA    15.08mA    47.85mA
-744.8mV  8.524mA    7.507mA    13.32mA
6.6V      0A         0A         0A
[Pulldown]
| Voltage   I(typ)   I(min)   I(max)
-3.3V     -1.009mA   -698.4uA   -1.399mA
-2.234V   -2.355mA   -1.393mA   -5.168mA
-1.738V   -6.137mA   -2.501mA   -24.35mA
-1.117V   -33.17mA   -14.12mA   -44.04mA
-620.7mV  -29.12mA   -24.39mA   -31.98mA
910.3mV   47.41mA    35.65mA    57.4mA
1.707V    68.78mA    43.57mA    95.36mA
3.797V    70.85mA    36.06mA    107.4mA
4.293V    53.17mA    7.074mA    97.48mA
5.038V    6.305mA    1.771mA    50.87mA
5.783V    1.853mA    982.8uA    11.9mA
6.6V      1.043mA    656.1uA    2.434mA
[Pullup]
| Voltage   I(typ)   I(min)   I(max)
-3.3V     1.756mA    1.099mA    3.431mA
-2.11V    6.905mA    2.684mA    27.15mA
-1.366V   35.93mA    12.91mA    48.11mA
-993.1mV  46.43mA    30.07mA    47.78mA
-620.7mV  36.85mA    31.24mA    38.64mA
2.162V    -132.4mA   -99.46mA   -154.8mA
3.3V      -173.4mA   -115.6mA   -219.3mA
3.921V    -175mA     -98.98mA   -239.5mA
4.293V    -163mA     -62.52mA   -235.6mA
4.914V    -103.6mA   -11.38mA   -208mA
5.907V    -13.53mA   -2.968mA   -106.5mA
6.6V      -3.952mA   -1.982mA   -43.03mA
[Ramp]
dV/dt_r   1.51721/0.266508n  1.30726/0.498444n  1.70108/0.182561n
dV/dt_f   1.43022/0.400979n  1.16928/0.822733n  1.64106/0.253483n
R_load = 50
[Falling Waveform]
R_fixture = 50
V_fixture = 0
V_fixture_min = 0
V_fixture_max = 0
| Time   V(typ)   V(min)   V(max)
0s        2.529V     2.18V      2.835V
809.1ps   2.526V     2.18V      2.793V
919.5ps   2.389V     2.178V     1.167V
1.022ns   1.068V     2.138V     280.4mV
1.088ns   611.5mV    1.937V     64.74mV
1.16ns    244.3mV    1.136V     12.69mV
1.293ns   21.83mV    459.3mV    1.126mV
1.48ns    1.462mV    63.76mV    986.7uV
1.847ns   473.6uV    826.4uV    711.7uV
333.3ns   925.6nV    1.69uV     3.322uV
[Falling Waveform]
R_fixture = 50
V_fixture = 3.3
V_fixture_min = 3
V_fixture_max = 3.6
| Time   V(typ)   V(min)   V(max)
0s        3.3V       3V         3.6V
864.9ps   3.304V     3V         3.586V
1.002ns   3.279V     3.003V     2.816V
1.153ns   2.835V     3.018V     1.667V
1.39ns    1.866V     2.824V     997.7mV
1.779ns   1.076V     2.167V     889.8mV
2.602ns   935.2mV    1.299V     868.5mV
3.721ns   919.7mV    1.09V      865.4mV
8.095ns   916.3mV    1.052V     864.9mV
333.3ns   916.3mV    1.051V     864.9mV
[Rising Waveform]
R_fixture = 50
V_fixture = 0
V_fixture_min = 0
V_fixture_max = 0
| Time   V(typ)   V(min)   V(max)
0s        925.5nV    1.69uV     3.322uV
886.4ps   -7.876mV   -540uV     59.56mV
1.051ns   79.31mV    -8.181mV   876.9mV
1.206ns   552.3mV    12.1mV     2.412V
1.299ns   996.5mV    73.02mV    2.659V
1.453ns   1.985V     292.5mV    2.744V
1.587ns   2.282V     590.6mV    2.774V
2.017ns   2.455V     1.739V     2.813V
2.704ns   2.506V     2.071V     2.83V
333.3ns   2.529V     2.179V     2.835V
[Rising Waveform]
R_fixture = 50
V_fixture = 3.3
V_fixture_min = 3
V_fixture_max = 3.6
| Time   V(typ)   V(min)   V(max)
0s        916.3mV    1.051V     864.9mV
770ps     916.3mV    1.051V     906.2mV
828.8ps   934.9mV    1.051V     1.493V
870.3ps   1.063V     1.051V     2.361V
938.4ps   2.079V     1.071V     3.381V
1.002ns   2.856V     1.282V     3.588V
1.09ns    3.248V     2.384V     3.598V
1.245ns   3.298V     2.949V     3.599V
1.721ns   3.299V     2.999V     3.599V
333.3ns   3.3V       3V         3.6V
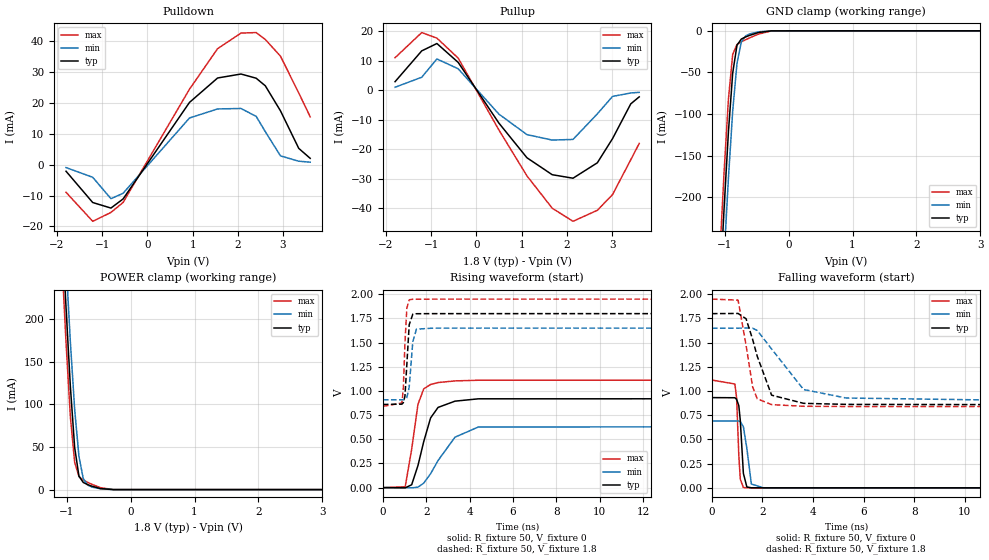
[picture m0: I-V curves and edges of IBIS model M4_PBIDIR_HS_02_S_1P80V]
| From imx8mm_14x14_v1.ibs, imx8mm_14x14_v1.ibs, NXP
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[Model] M4_PBIDIR_HS_02_S_1P80V
Model_type I/O
Vinl  =  0.54
Vinh  =  1.26
Vmeas =  0.9
| Capacitance   typ   min   max
C_comp   1.4062710684e-12   1.31845087786e-12   1.45127599534e-12
| Variables   typ   min   max
[GND Clamp Reference]   0   0   0
[POWER Clamp Reference]   1.8   1.65   1.95
[Pulldown Reference]   0   0   0
[Pullup Reference]   1.8   1.65   1.95
[Temperature Range]   25   125   -40
[Voltage Range]   1.8   1.65   1.95
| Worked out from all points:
|   slope of the pulldown table from 0 to 0.27 V, typ, clamps not added: 43.7 ohm
|   slope of the pullup table from 0 to 0.27 V, typ, clamps not added: 43.6 ohm
|   GND clamp passes 1 mA (typ) near -0.41 V on its own axis
|   POWER clamp passes 1 mA (typ) near -0.45 V on its own axis
|   falling waveform, R_fixture 50, V_fixture 0: 20-80 % time 122ps typ, 163ps min, 101ps max; typ from 0.933 V to 0 V
|   falling waveform, R_fixture 50, V_fixture 1.8: 20-80 % time 626ps typ, 1.21ns min, 395ps max; typ from 1.8 V to 0.86 V
|   rising waveform, R_fixture 50, V_fixture 0: 20-80 % time 682ps typ, 1.33ns min, 425ps max; typ from 0 V to 0.933 V
|   rising waveform, R_fixture 50, V_fixture 1.8: 20-80 % time 128ps typ, 155ps min, 113ps max; typ from 0.86 V to 1.8 V
[GND Clamp]
| Voltage   I(typ)   I(min)   I(max)
-1.8V     -1.55A     -1.599A    -1.507A
-1.076V   -314.9mA   -373.7mA   -269.5mA
-1.009V   -213.2mA   -272mA     -169.8mA
-941.4mV  -121.7mA   -177.5mA   -82.37mA
-874.1mV  -50.6mA    -96.19mA   -28.29mA
-806.9mV  -17.14mA   -38.88mA   -16.37mA
-739.7mV  -9.899mA   -13.25mA   -13.3mA
-672.4mV  -7.363mA   -6.1mA     -10.74mA
-605.2mV  -5.351mA   -3.675mA   -8.301mA
-470.7mV  -2.028mA   -1.167mA   -3.928mA
-269mV    -32.97uA   -24.73uA   -158.8uA
3.6V      0A         0A         0A
[POWER Clamp]
| Voltage   I(typ)   I(min)   I(max)
-1.8V     1.551A     1.591A     1.512A
-1.076V   314.9mA    367.7mA    272mA
-1.009V   213mA      266.5mA    172.2mA
-941.4mV  120.9mA    173.2mA    85.48mA
-874.1mV  49.37mA    93.93mA    31.94mA
-806.9mV  15.67mA    38.77mA    15.36mA
-739.7mV  8.383mA    12.98mA    11.23mA
-672.4mV  5.889mA    5.395mA    8.598mA
-605.2mV  4.004mA    3.004mA    6.202mA
-470.7mV  1.209mA    899.6uA    2.273mA
-269mV    8.867uA    21.52uA    34.39uA
3.6V      0A         0A         0A
[Pulldown]
| Voltage   I(typ)   I(min)   I(max)
-1.8V     -2.147mA   -951.2uA   -8.956mA
-1.21V    -12.26mA   -4.099mA   -18.34mA
-806.9mV  -14.06mA   -11.02mA   -15.48mA
-537.9mV  -11.11mA   -9.274mA   -12.24mA
931mV     20.14mA    15.09mA    24.42mA
1.552V    28.03mA    18.01mA    37.52mA
2.069V    29.32mA    18.17mA    42.56mA
2.405V    27.96mA    15.61mA    42.73mA
2.607V    25.51mA    10.67mA    40.5mA
2.943V    17.4mA     2.828mA    35.09mA
3.347V    5.257mA    1.104mA    23.19mA
3.6V      2.032mA    786.8uA    15.48mA
[Pullup]
| Voltage   I(typ)   I(min)   I(max)
-1.8V     2.895mA    1.013mA    11.04mA
-1.21V    13.37mA    4.412mA    19.59mA
-874.1mV  15.87mA    10.62mA    17.7mA
-403.4mV  9.449mA    7.287mA    10.9mA
496.6mV   -11.17mA   -8.121mA   -13.5mA
1.117V    -22.95mA   -15.08mA   -29.1mA
1.676V    -28.71mA   -16.94mA   -40.09mA
2.136V    -29.9mA    -16.72mA   -44.54mA
2.674V    -24.66mA   -8.033mA   -40.8mA
3.01V     -16.45mA   -2.11mA    -35.46mA
3.414V    -4.625mA   -928.3uA   -23.61mA
3.6V      -2.257mA   -731.5uA   -18.09mA
[Ramp]
dV/dt_r   0.559581/0.6818n  0.41457/1.32883n  0.668538/0.42482n
dV/dt_f   0.563767/0.625631n  0.444874/1.21182n  0.665669/0.394516n
R_load = 50
[Falling Waveform]
R_fixture = 50
V_fixture = 0
V_fixture_min = 0
V_fixture_max = 0
| Time   V(typ)   V(min)   V(max)
0s        932.6mV    691mV      1.114V
909.8ps   931.1mV    691mV      1.073V
977.1ps   915mV      690.9mV    931.9mV
1.065ns   848.8mV    690.6mV    335.7mV
1.124ns   695.8mV    683.7mV    88.67mV
1.245ns   150.1mV    632.6mV    3.743mV
1.383ns   9.309mV    407.7mV    672.3uV
1.56ns    786.8uV    39.76mV    460.8uV
2.041ns   335.9uV    514.3uV    270uV
333.3ns   124.3nV    586.1nV    100.3nV
[Falling Waveform]
R_fixture = 50
V_fixture = 1.8
V_fixture_min = 1.65
V_fixture_max = 1.95
| Time   V(typ)   V(min)   V(max)
0s        1.8V       1.65V      1.95V
1.036ns   1.802V     1.65V      1.94V
1.352ns   1.747V     1.652V     1.474V
1.609ns   1.536V     1.65V      1.045V
1.794ns   1.359V     1.626V     920mV
2.361ns   957.6mV    1.435V     859.9mV
3.624ns   873.3mV    1.016V     843mV
5.307ns   862.5mV    928.2mV    840.8mV
10.62ns   860.4mV    909.1mV    840.5mV
333.3ns   860.4mV    908.5mV    840.6mV
[Rising Waveform]
R_fixture = 50
V_fixture = 0
V_fixture_min = 0
V_fixture_max = 0
| Time   V(typ)   V(min)   V(max)
0s        91.69nV    585.2nV    87.91nV
1.031ns   -1.943mV   -598.8uV   9.459mV
1.329ns   29.69mV    -2.311mV   397.2mV
1.62ns    229.2mV    5.248mV    862.9mV
1.887ns   477.6mV    46.87mV    1.022V
2.202ns   721.2mV    144.4mV    1.067V
2.546ns   829.8mV    280.7mV    1.087V
3.328ns   894.6mV    522.2mV    1.104V
4.404ns   918.7mV    627mV      1.111V
333.3ns   932.6mV    691mV      1.114V
[Rising Waveform]
R_fixture = 50
V_fixture = 1.8
V_fixture_min = 1.65
V_fixture_max = 1.95
| Time   V(typ)   V(min)   V(max)
0s        860.4mV    908.5mV    840.6mV
878.8ps   863.5mV    908.5mV    876.2mV
943.3ps   878.6mV    908.4mV    1.019V
1.019ns   946.1mV    911.6mV    1.494V
1.106ns   1.271V     930.9mV    1.856V
1.215ns   1.685V     1.04V      1.943V
1.381ns   1.794V     1.508V     1.949V
1.548ns   1.799V     1.639V     1.949V
2.31ns    1.8V       1.65V      1.95V
333.3ns   1.8V       1.65V      1.95V
[Add Submodel]
| Submodel Name Mode
M4_PBIDIR_HS_02_S_1P80V_T All
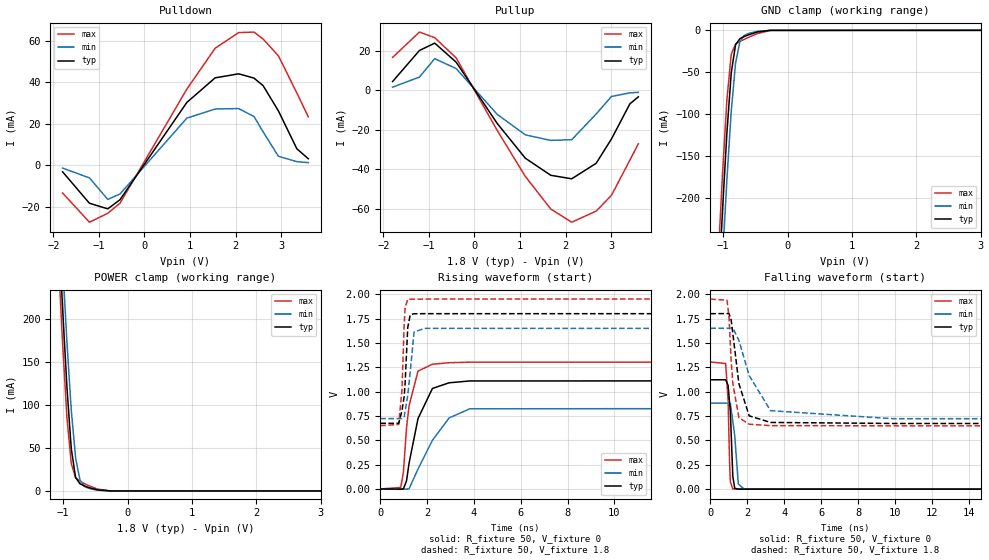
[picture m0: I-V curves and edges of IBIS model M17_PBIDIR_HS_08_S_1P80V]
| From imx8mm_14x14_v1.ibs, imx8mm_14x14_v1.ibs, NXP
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[Model] M17_PBIDIR_HS_08_S_1P80V
Model_type I/O
Vinl  =  0.54
Vinh  =  1.26
Vmeas =  0.9
| Capacitance   typ   min   max
C_comp   1.4062710684e-12   1.31845087786e-12   1.45127599534e-12
| Variables   typ   min   max
[GND Clamp Reference]   0   0   0
[POWER Clamp Reference]   1.8   1.65   1.95
[Pulldown Reference]   0   0   0
[Pullup Reference]   1.8   1.65   1.95
[Temperature Range]   25   125   -40
[Voltage Range]   1.8   1.65   1.95
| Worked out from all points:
|   slope of the pulldown table from 0 to 0.27 V, typ, clamps not added: 29.1 ohm
|   slope of the pullup table from 0 to 0.27 V, typ, clamps not added: 29.1 ohm
|   GND clamp passes 1 mA (typ) near -0.41 V on its own axis
|   POWER clamp passes 1 mA (typ) near -0.45 V on its own axis
|   falling waveform, R_fixture 50, V_fixture 0: 20-80 % time 159ps typ, 238ps min, 121ps max; typ from 1.12 V to 0 V
|   falling waveform, R_fixture 50, V_fixture 1.8: 20-80 % time 552ps typ, 1.15ns min, 305ps max; typ from 1.8 V to 0.674 V
|   rising waveform, R_fixture 50, V_fixture 0: 20-80 % time 648ps typ, 1.27ns min, 359ps max; typ from 0 V to 1.12 V
|   rising waveform, R_fixture 50, V_fixture 1.8: 20-80 % time 159ps typ, 232ps min, 129ps max; typ from 0.674 V to 1.8 V
[GND Clamp]
| Voltage   I(typ)   I(min)   I(max)
-1.8V     -1.55A     -1.599A    -1.507A
-1.076V   -314.9mA   -373.7mA   -269.5mA
-1.009V   -213.2mA   -272mA     -169.8mA
-941.4mV  -121.7mA   -177.5mA   -82.37mA
-874.1mV  -50.6mA    -96.19mA   -28.29mA
-806.9mV  -17.14mA   -38.88mA   -16.37mA
-739.7mV  -9.899mA   -13.25mA   -13.3mA
-672.4mV  -7.363mA   -6.1mA     -10.74mA
-605.2mV  -5.351mA   -3.675mA   -8.301mA
-470.7mV  -2.028mA   -1.167mA   -3.928mA
-269mV    -32.97uA   -24.73uA   -158.8uA
3.6V      0A         0A         0A
[POWER Clamp]
| Voltage   I(typ)   I(min)   I(max)
-1.8V     1.551A     1.591A     1.512A
-1.076V   314.9mA    367.7mA    272mA
-1.009V   213mA      266.5mA    172.2mA
-941.4mV  120.9mA    173.2mA    85.48mA
-874.1mV  49.37mA    93.93mA    31.94mA
-806.9mV  15.67mA    38.77mA    15.36mA
-739.7mV  8.383mA    12.98mA    11.23mA
-672.4mV  5.889mA    5.395mA    8.598mA
-605.2mV  4.004mA    3.004mA    6.202mA
-470.7mV  1.209mA    899.6uA    2.273mA
-269mV    8.867uA    21.52uA    34.39uA
3.6V      0A         0A         0A
[Pulldown]
| Voltage   I(typ)   I(min)   I(max)
-1.8V     -3.22mA    -1.427mA   -13.43mA
-1.21V    -18.38mA   -6.148mA   -27.51mA
-806.9mV  -21.08mA   -16.53mA   -23.22mA
-537.9mV  -16.67mA   -13.91mA   -18.36mA
931mV     30.21mA    22.63mA    36.63mA
1.552V    42.04mA    27.02mA    56.28mA
2.069V    43.98mA    27.25mA    63.85mA
2.405V    41.93mA    23.42mA    64.09mA
2.607V    38.26mA    16mA       60.74mA
2.943V    26.09mA    4.241mA    52.63mA
3.347V    7.885mA    1.656mA    34.78mA
3.6V      3.049mA    1.18mA     23.22mA
[Pullup]
| Voltage   I(typ)   I(min)   I(max)
-1.8V     4.342mA    1.519mA    16.56mA
-1.21V    20.06mA    6.617mA    29.38mA
-874.1mV  23.8mA     15.93mA    26.55mA
-403.4mV  14.17mA    10.93mA    16.34mA
496.6mV   -16.76mA   -12.18mA   -20.25mA
1.117V    -34.43mA   -22.62mA   -43.65mA
1.676V    -43.07mA   -25.42mA   -60.13mA
2.136V    -44.85mA   -25.08mA   -66.8mA
2.674V    -36.99mA   -12.05mA   -61.19mA
3.01V     -24.67mA   -3.165mA   -53.19mA
3.414V    -6.938mA   -1.392mA   -35.41mA
3.6V      -3.385mA   -1.097mA   -27.13mA
[Ramp]
dV/dt_r   0.673175/0.64786n  0.529603/1.26966n  0.783062/0.359022n
dV/dt_f   0.675721/0.551645n  0.556635/1.15338n  0.780259/0.304903n
R_load = 50
[Falling Waveform]
R_fixture = 50
V_fixture = 0
V_fixture_min = 0
V_fixture_max = 0
| Time   V(typ)   V(min)   V(max)
0s        1.122V     882.7mV    1.305V
830ps     1.122V     882.7mV    1.289V
961.8ps   1.065V     882.7mV    915.7mV
1.046ns   879.7mV    883mV      252.9mV
1.083ns   800.8mV    879.2mV    78.18mV
1.217ns   134.3mV    697.7mV    1.798mV
1.321ns   8.908mV    549.6mV    715.9uV
1.515ns   790.2uV    52.98mV    426.4uV
1.826ns   381.2uV    819.8uV    269.7uV
333.3ns   86.17nV    436.9nV    65.34nV
[Falling Waveform]
R_fixture = 50
V_fixture = 1.8
V_fixture_min = 1.65
V_fixture_max = 1.95
| Time   V(typ)   V(min)   V(max)
0s        1.8V       1.65V      1.95V
902.7ps   1.801V     1.65V      1.938V
1.01ns    1.802V     1.65V      1.773V
1.13ns    1.734V     1.653V     1.312V
1.222ns   1.591V     1.653V     1.08V
1.547ns   1.082V     1.526V     733.1mV
2.103ns   751.8mV    1.165V     666.3mV
3.26ns    684.5mV    804.8mV    651.8mV
9.889ns   673.8mV    722.8mV    649.6mV
333.3ns   673.8mV    722.3mV    649.6mV
[Rising Waveform]
R_fixture = 50
V_fixture = 0
V_fixture_min = 0
V_fixture_max = 0
| Time   V(typ)   V(min)   V(max)
0s        63.59nV    436.2nV    57.29nV
871.9ps   -2.475mV   -17.19uV   14.53mV
987.4ps   -325.2uV   -1.072mV   171.9mV
1.123ns   84.83mV    -2.078mV   631.6mV
1.229ns   263.9mV    1.627mV    853.1mV
1.611ns   722.6mV    204.4mV    1.21V
2.228ns   1.032V     499.3mV    1.281V
2.938ns   1.09V      728.5mV    1.296V
3.821ns   1.109V     822.9mV    1.302V
333.3ns   1.122V     882.7mV    1.305V
[Rising Waveform]
R_fixture = 50
V_fixture = 1.8
V_fixture_min = 1.65
V_fixture_max = 1.95
| Time   V(typ)   V(min)   V(max)
0s        673.8mV    722.3mV    649.6mV
784.3ps   673.7mV    722.2mV    662.4mV
924.6ps   800mV      722mV      1.011V
1.019ns   945.8mV    735.1mV    1.675V
1.061ns   1.087V     799.5mV    1.862V
1.173ns   1.659V     960.7mV    1.947V
1.279ns   1.788V     1.203V     1.949V
1.443ns   1.799V     1.612V     1.949V
1.894ns   1.8V       1.649V     1.95V
333.3ns   1.8V       1.65V      1.95V
[Add Submodel]
| Submodel Name Mode
M17_PBIDIR_HS_08_S_1P80V_T All
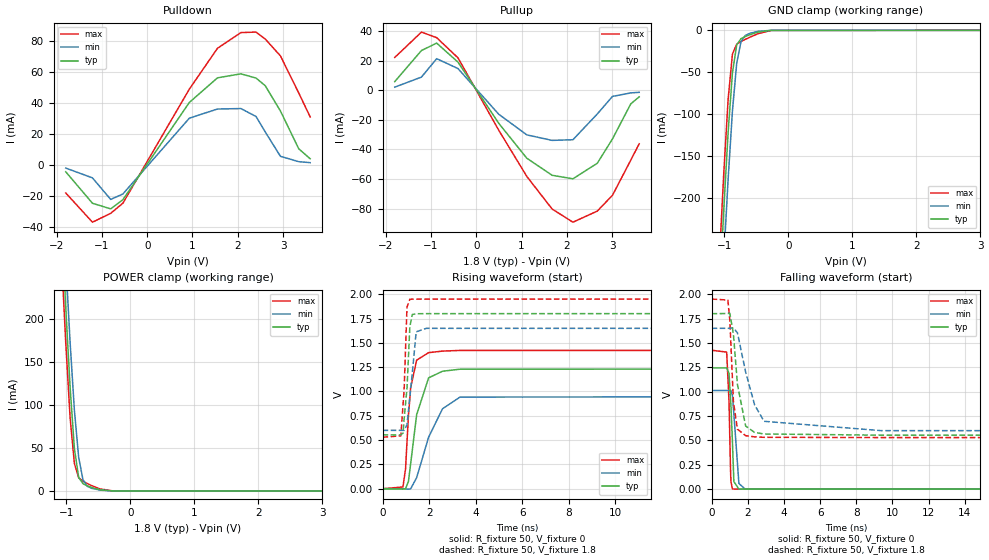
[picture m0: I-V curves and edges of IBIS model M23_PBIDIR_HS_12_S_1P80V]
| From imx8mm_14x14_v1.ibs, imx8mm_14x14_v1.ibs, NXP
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[Model] M23_PBIDIR_HS_12_S_1P80V
Model_type I/O
Vinl  =  0.54
Vinh  =  1.26
Vmeas =  0.9
| Capacitance   typ   min   max
C_comp   1.4062710684e-12   1.31845087786e-12   1.45127599534e-12
| Variables   typ   min   max
[GND Clamp Reference]   0   0   0
[POWER Clamp Reference]   1.8   1.65   1.95
[Pulldown Reference]   0   0   0
[Pullup Reference]   1.8   1.65   1.95
[Temperature Range]   25   125   -40
[Voltage Range]   1.8   1.65   1.95
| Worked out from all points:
|   slope of the pulldown table from 0 to 0.27 V, typ, clamps not added: 21.8 ohm
|   slope of the pullup table from 0 to 0.27 V, typ, clamps not added: 21.8 ohm
|   GND clamp passes 1 mA (typ) near -0.41 V on its own axis
|   POWER clamp passes 1 mA (typ) near -0.45 V on its own axis
|   falling waveform, R_fixture 50, V_fixture 0: 20-80 % time 165ps typ, 225ps min, 129ps max; typ from 1.24 V to 0 V
|   falling waveform, R_fixture 50, V_fixture 1.8: 20-80 % time 409ps typ, 876ps min, 221ps max; typ from 1.8 V to 0.554 V
|   rising waveform, R_fixture 50, V_fixture 0: 20-80 % time 473ps typ, 965ps min, 252ps max; typ from 0 V to 1.24 V
|   rising waveform, R_fixture 50, V_fixture 1.8: 20-80 % time 195ps typ, 250ps min, 153ps max; typ from 0.554 V to 1.8 V
[GND Clamp]
| Voltage   I(typ)   I(min)   I(max)
-1.8V     -1.55A     -1.599A    -1.507A
-1.076V   -314.9mA   -373.7mA   -269.5mA
-1.009V   -213.2mA   -272mA     -169.8mA
-941.4mV  -121.7mA   -177.5mA   -82.37mA
-874.1mV  -50.6mA    -96.19mA   -28.29mA
-806.9mV  -17.14mA   -38.88mA   -16.37mA
-739.7mV  -9.899mA   -13.25mA   -13.3mA
-672.4mV  -7.363mA   -6.1mA     -10.74mA
-605.2mV  -5.351mA   -3.675mA   -8.301mA
-470.7mV  -2.028mA   -1.167mA   -3.928mA
-269mV    -32.97uA   -24.73uA   -158.8uA
3.6V      0A         0A         0A
[POWER Clamp]
| Voltage   I(typ)   I(min)   I(max)
-1.8V     1.551A     1.591A     1.512A
-1.076V   314.9mA    367.7mA    272mA
-1.009V   213mA      266.5mA    172.2mA
-941.4mV  120.9mA    173.2mA    85.48mA
-874.1mV  49.37mA    93.93mA    31.94mA
-806.9mV  15.67mA    38.77mA    15.36mA
-739.7mV  8.383mA    12.98mA    11.23mA
-672.4mV  5.889mA    5.395mA    8.598mA
-605.2mV  4.004mA    3.004mA    6.202mA
-470.7mV  1.209mA    899.6uA    2.273mA
-269mV    8.867uA    21.52uA    34.39uA
3.6V      0A         0A         0A
[Pulldown]
| Voltage   I(typ)   I(min)   I(max)
-1.8V     -4.293mA   -1.902mA   -17.91mA
-1.21V    -24.51mA   -8.198mA   -36.67mA
-806.9mV  -28.11mA   -22.04mA   -30.96mA
-537.9mV  -22.23mA   -18.55mA   -24.48mA
931mV     40.28mA    30.17mA    48.84mA
1.552V    56.06mA    36.03mA    75.04mA
2.069V    58.65mA    36.34mA    85.13mA
2.405V    55.91mA    31.22mA    85.46mA
2.607V    51.01mA    21.34mA    80.99mA
2.943V    34.78mA    5.655mA    70.17mA
3.347V    10.51mA    2.209mA    46.37mA
3.6V      4.065mA    1.574mA    30.97mA
[Pullup]
| Voltage   I(typ)   I(min)   I(max)
-1.8V     5.79mA     2.026mA    22.08mA
-1.21V    26.74mA    8.823mA    39.17mA
-874.1mV  31.74mA    21.24mA    35.4mA
-403.4mV  18.9mA     14.57mA    21.79mA
496.6mV   -22.34mA   -16.24mA   -27mA
1.117V    -45.91mA   -30.16mA   -58.19mA
1.676V    -57.42mA   -33.89mA   -80.17mA
2.136V    -59.8mA    -33.44mA   -89.07mA
2.674V    -49.31mA   -16.07mA   -81.59mA
3.01V     -32.89mA   -4.22mA    -70.92mA
3.414V    -9.251mA   -1.856mA   -47.21mA
3.6V      -4.513mA   -1.463mA   -36.18mA
[Ramp]
dV/dt_r   0.746291/0.473099n  0.607209/0.965146n  0.855095/0.252101n
dV/dt_f   0.747754/0.408803n  0.630014/0.875584n  0.852436/0.220915n
R_load = 50
[Falling Waveform]
R_fixture = 50
V_fixture = 0
V_fixture_min = 0
V_fixture_max = 0
| Time   V(typ)   V(min)   V(max)
0s        1.244V     1.012V     1.425V
835.3ps   1.244V     1.012V     1.406V
964.3ps   1.189V     1.012V     904.3mV
1.044ns   932.6mV    1.012V     223.6mV
1.069ns   861.8mV    1.011V     82.11mV
1.15ns    501.7mV    965.7mV    4.193mV
1.233ns   77.19mV    770.5mV    1.14mV
1.511ns   850.4uV    58.53mV    527.7uV
1.858ns   424.3uV    811uV      249.8uV
333.3ns   61.32nV    336.1nV    43.33nV
[Falling Waveform]
R_fixture = 50
V_fixture = 1.8
V_fixture_min = 1.65
V_fixture_max = 1.95
| Time   V(typ)   V(min)   V(max)
0s        1.8V       1.65V      1.95V
900.9ps   1.802V     1.65V      1.94V
1.009ns   1.804V     1.65V      1.734V
1.208ns   1.591V     1.655V     898.8mV
1.43ns    1.075V     1.604V     615.2mV
1.883ns   648.1mV    1.202V     548.7mV
2.38ns    582mV      864.3mV    536.2mV
2.902ns   566.1mV    696.1mV    532mV
9.377ns   553.8mV    600.4mV    529.3mV
333.3ns   553.7mV    600mV      529.3mV
[Rising Waveform]
R_fixture = 50
V_fixture = 0
V_fixture_min = 0
V_fixture_max = 0
| Time   V(typ)   V(min)   V(max)
0s        45.31nV    335.6nV    37.87nV
876.6ps   -3.787mV   -8.308uV   17.89mV
986.8ps   -971.7uV   -1.5mV     202.6mV
1.112ns   75.84mV    -4.604mV   754mV
1.208ns   259.7mV    -708.3uV   1.04V
1.464ns   760.8mV    113.7mV    1.322V
1.978ns   1.14V      530.1mV    1.399V
2.575ns   1.208V     822.2mV    1.415V
3.326ns   1.229V     942.2mV    1.422V
333.3ns   1.244V     1.012V     1.425V
[Rising Waveform]
R_fixture = 50
V_fixture = 1.8
V_fixture_min = 1.65
V_fixture_max = 1.95
| Time   V(typ)   V(min)   V(max)
0s        553.7mV    600mV      529.3mV
785.8ps   553.6mV    600mV      543.8mV
880.3ps   571.9mV    600mV      866.8mV
926.5ps   718.9mV    599.7mV    1.016V
1.05ns    1.033V     657.1mV    1.868V
1.172ns   1.665V     944.8mV    1.948V
1.276ns   1.791V     1.184V     1.949V
1.443ns   1.799V     1.613V     1.949V
1.877ns   1.8V       1.649V     1.95V
333.3ns   1.8V       1.65V      1.95V
[Add Submodel]
| Submodel Name Mode
M23_PBIDIR_HS_12_S_1P80V_T All
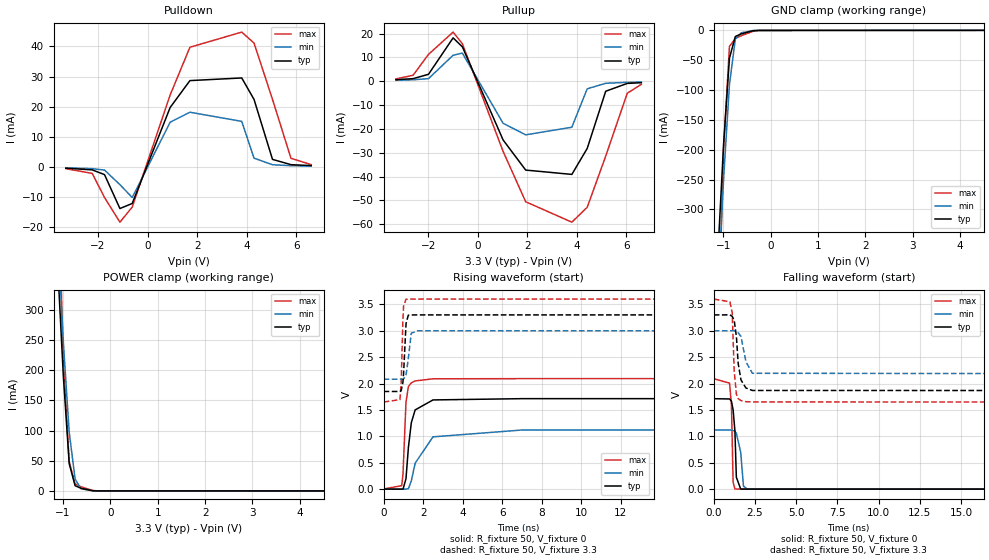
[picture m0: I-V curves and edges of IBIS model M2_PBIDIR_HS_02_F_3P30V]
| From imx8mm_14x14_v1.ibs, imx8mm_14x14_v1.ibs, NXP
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[Model] M2_PBIDIR_HS_02_F_3P30V
Model_type I/O
Vinl  =  0.99
Vinh  =  2.31
Vmeas =  1.65
| Capacitance   typ   min   max
C_comp   1.08818991111e-12   1.03117834871e-12   1.10439570077e-12
| Variables   typ   min   max
[GND Clamp Reference]   0   0   0
[POWER Clamp Reference]   3.3   3   3.6
[Pulldown Reference]   0   0   0
[Pullup Reference]   3.3   3   3.6
[Temperature Range]   25   125   -40
[Voltage Range]   3.3   3   3.6
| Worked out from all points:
|   slope of the pulldown table from 0 to 0.495 V, typ, clamps not added: 44.3 ohm
|   slope of the pullup table from 0 to 0.495 V, typ, clamps not added: 39.7 ohm
|   GND clamp passes 1 mA (typ) near -0.39 V on its own axis
|   POWER clamp passes 1 mA (typ) near -0.44 V on its own axis
|   falling waveform, R_fixture 50, V_fixture 0: 20-80 % time 134ps typ, 227ps min, 80.6ps max; typ from 1.71 V to 0.002 V
|   falling waveform, R_fixture 50, V_fixture 3.3: 20-80 % time 239ps typ, 418ps min, 141ps max; typ from 3.3 V to 1.85 V
|   rising waveform, R_fixture 50, V_fixture 0: 20-80 % time 306ps typ, 705ps min, 140ps max; typ from 0.002 V to 1.71 V
|   rising waveform, R_fixture 50, V_fixture 3.3: 20-80 % time 112ps typ, 148ps min, 85.5ps max; typ from 1.85 V to 3.3 V
[GND Clamp]
| Voltage   I(typ)   I(min)   I(max)
-3.3V     -7.236A    -6.565A    -8.004A
-1.117V   -380.4mA   -438.7mA   -546.7mA
-993.1mV  -191mA     -249.4mA   -198.9mA
-869mV    -46.61mA   -90.79mA   -26.93mA
-744.8mV  -10.31mA   -14.37mA   -13.71mA
-620.7mV  -5.945mA   -4.193mA   -9.059mA
-372.4mV  -659.7uA   -360.2uA   -1.673mA
-248.3mV  -143.8uA   -94.2uA    -265.5uA
6.6V      0A         0A         0A
[POWER Clamp]
| Voltage   I(typ)   I(min)   I(max)
-3.3V     7.237A     6.564A     8.009A
-1.117V   380.7mA    433.6mA    553.5mA
-993.1mV  190.7mA    247mA      219.9mA
-869mV    45.33mA    97.36mA    48.38mA
-744.8mV  8.677mA    19.82mA    11.82mA
-620.7mV  4.425mA    3.499mA    6.828mA
-372.4mV  215.5uA    293.3uA    764.6uA
-248.3mV  4.273uA    22.4uA     51.08uA
6.6V      0A         0A         0A
[Pulldown]
| Voltage   I(typ)   I(min)   I(max)
-3.3V     -420.3uA   -290.8uA   -582.9uA
-2.234V   -980.9uA   -580.5uA   -2.153mA
-1.738V   -2.557mA   -1.042mA   -10.15mA
-1.117V   -13.82mA   -5.885mA   -18.35mA
-620.7mV  -12.13mA   -10.16mA   -13.33mA
910.3mV   19.75mA    14.85mA    23.92mA
1.707V    28.66mA    18.16mA    39.73mA
3.797V    29.54mA    15.13mA    44.77mA
4.293V    22.41mA    2.904mA    41.11mA
5.038V    2.501mA    726.2uA    22.43mA
5.783V    752.4uA    404.4uA    2.861mA
6.6V      427uA      270.6uA    764uA
[Pullup]
| Voltage   I(typ)   I(min)   I(max)
-3.3V     646uA      406.2uA    983.2uA
-2.607V   1.091mA    612.5uA    2.506mA
-1.986V   2.921mA    1.098mA    11.28mA
-993.1mV  18.2mA     10.91mA    20.63mA
-620.7mV  14.46mA    11.81mA    15.75mA
1.024V    -24.64mA   -17.64mA   -29.45mA
1.934V    -37.27mA   -22.49mA   -50.56mA
3.797V    -39.09mA   -19.29mA   -59.14mA
4.417V    -28.17mA   -3.165mA   -52.88mA
5.162V    -4.195mA   -851.2uA   -31.42mA
6.031V    -907.4uA   -453.2uA   -5.047mA
6.6V      -609.8uA   -346.2uA   -1.277mA
[Ramp]
dV/dt_r   1.02723/0.305937n  0.671425/0.705146n  1.25378/0.140057n
dV/dt_f   0.870139/0.239068n  0.55069/0.417647n  1.16985/0.140926n
R_load = 50
[Falling Waveform]
R_fixture = 50
V_fixture = 0
V_fixture_min = 0
V_fixture_max = 0
| Time   V(typ)   V(min)   V(max)
0s        1.714V     1.121V     2.093V
958ps     1.709V     1.121V     2.008V
1.072ns   1.668V     1.12V      1.592V
1.173ns   1.501V     1.112V     129.1mV
1.283ns   1.102V     1.098V     6.463mV
1.369ns   226.8mV    1.058V     3.959mV
1.634ns   2.938mV    699.2mV    3.539mV
1.801ns   2.675mV    57.54mV    3.416mV
2.047ns   2.598mV    2.073mV    3.338mV
333.3ns   2.315mV    1.543mV    3.247mV
[Falling Waveform]
R_fixture = 50
V_fixture = 3.3
V_fixture_min = 3
V_fixture_max = 3.6
| Time   V(typ)   V(min)   V(max)
0s        3.3V       3V         3.6V
977.6ps   3.301V     3V         3.549V
1.119ns   3.272V     3V         3.341V
1.239ns   3.197V     3.001V     2.236V
1.374ns   2.886V     2.99V      1.795V
1.479ns   2.386V     2.962V     1.716V
1.649ns   2.07V      2.892V     1.678V
1.951ns   1.916V     2.414V     1.658V
2.339ns   1.87V      2.195V     1.652V
333.3ns   1.85V      2.082V     1.65V
[Rising Waveform]
R_fixture = 50
V_fixture = 0
V_fixture_min = 0
V_fixture_max = 0
| Time   V(typ)   V(min)   V(max)
0s        2.315mV    1.543mV    3.247mV
914.3ps   1.296mV    1.567mV    67.35mV
980.5ps   727.4uV    1.199mV    296.8mV
1.13ns    198.6mV    400.1uV    1.647V
1.254ns   795.6mV    11.98mV    1.946V
1.401ns   1.26V      156.8mV    2.013V
1.594ns   1.501V     492.1mV    2.05V
2.497ns   1.69V      990.9mV    2.09V
6.985ns   1.714V     1.12V      2.093V
333.3ns   1.714V     1.121V     2.093V
[Rising Waveform]
R_fixture = 50
V_fixture = 3.3
V_fixture_min = 3
V_fixture_max = 3.6
| Time   V(typ)   V(min)   V(max)
0s        1.85V      2.082V     1.65V
823.9ps   1.85V      2.082V     1.696V
885.7ps   1.867V     2.082V     2.004V
973.2ps   2.017V     2.083V     3.19V
1.008ns   2.187V     2.087V     3.469V
1.133ns   3.135V     2.163V     3.597V
1.247ns   3.294V     2.47V      3.599V
1.396ns   3.299V     2.952V     3.599V
1.708ns   3.3V       2.999V     3.6V
333.3ns   3.3V       3V         3.6V
[Add Submodel]
| Submodel Name Mode
M2_PBIDIR_HS_02_F_3P30V_T All
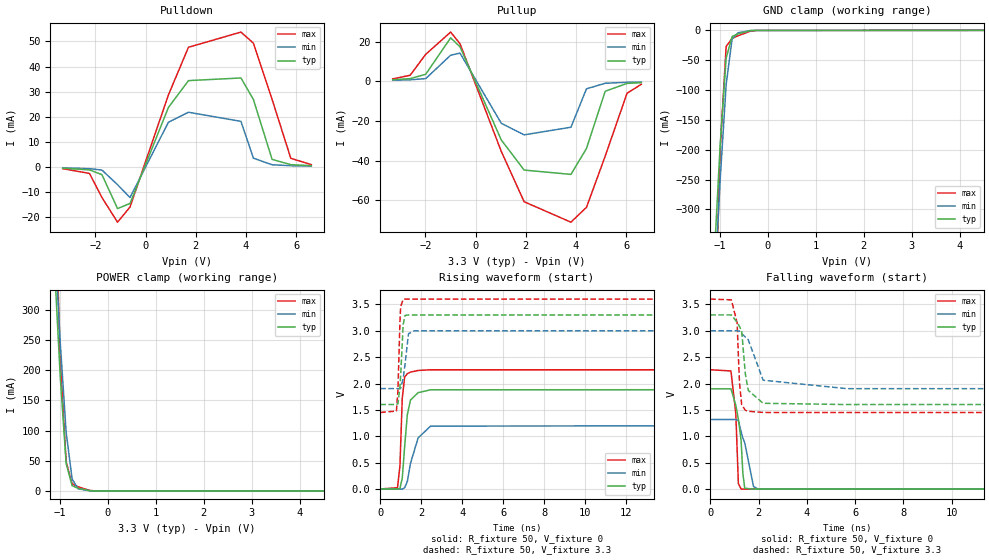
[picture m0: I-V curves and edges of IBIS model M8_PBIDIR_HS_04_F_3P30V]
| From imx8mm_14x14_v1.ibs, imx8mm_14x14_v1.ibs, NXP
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[Model] M8_PBIDIR_HS_04_F_3P30V
Model_type I/O
Vinl  =  0.99
Vinh  =  2.31
Vmeas =  1.65
| Capacitance   typ   min   max
C_comp   1.08818991111e-12   1.03117834871e-12   1.10439570077e-12
| Variables   typ   min   max
[GND Clamp Reference]   0   0   0
[POWER Clamp Reference]   3.3   3   3.6
[Pulldown Reference]   0   0   0
[Pullup Reference]   3.3   3   3.6
[Temperature Range]   25   125   -40
[Voltage Range]   3.3   3   3.6
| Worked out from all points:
|   slope of the pulldown table from 0 to 0.495 V, typ, clamps not added: 36.9 ohm
|   slope of the pullup table from 0 to 0.495 V, typ, clamps not added: 33.1 ohm
|   GND clamp passes 1 mA (typ) near -0.39 V on its own axis
|   POWER clamp passes 1 mA (typ) near -0.44 V on its own axis
|   falling waveform, R_fixture 50, V_fixture 0: 20-80 % time 258ps typ, 434ps min, 165ps max; typ from 1.9 V to 0.002 V
|   falling waveform, R_fixture 50, V_fixture 3.3: 20-80 % time 216ps typ, 419ps min, 120ps max; typ from 3.3 V to 1.6 V
|   rising waveform, R_fixture 50, V_fixture 0: 20-80 % time 239ps typ, 614ps min, 123ps max; typ from 0.002 V to 1.9 V
|   rising waveform, R_fixture 50, V_fixture 3.3: 20-80 % time 132ps typ, 181ps min, 97ps max; typ from 1.6 V to 3.3 V
[GND Clamp]
| Voltage   I(typ)   I(min)   I(max)
-3.3V     -7.236A    -6.565A    -8.004A
-1.117V   -380.4mA   -438.7mA   -546.7mA
-993.1mV  -191mA     -249.4mA   -198.9mA
-869mV    -46.61mA   -90.79mA   -26.93mA
-744.8mV  -10.31mA   -14.37mA   -13.71mA
-620.7mV  -5.945mA   -4.193mA   -9.059mA
-372.4mV  -659.7uA   -360.2uA   -1.673mA
-248.3mV  -143.8uA   -94.2uA    -265.5uA
6.6V      0A         0A         0A
[POWER Clamp]
| Voltage   I(typ)   I(min)   I(max)
-3.3V     7.237A     6.564A     8.009A
-1.117V   380.7mA    433.6mA    553.5mA
-993.1mV  190.7mA    247mA      219.9mA
-869mV    45.33mA    97.36mA    48.38mA
-744.8mV  8.677mA    19.82mA    11.82mA
-620.7mV  4.425mA    3.499mA    6.828mA
-372.4mV  215.5uA    293.3uA    764.6uA
-248.3mV  4.273uA    22.4uA     51.08uA
6.6V      0A         0A         0A
[Pulldown]
| Voltage   I(typ)   I(min)   I(max)
-3.3V     -504.5uA   -348.9uA   -699.6uA
-2.234V   -1.177mA   -696.7uA   -2.583mA
-1.738V   -3.068mA   -1.25mA    -12.18mA
-1.117V   -16.59mA   -7.062mA   -22.02mA
-620.7mV  -14.56mA   -12.2mA    -15.99mA
910.3mV   23.7mA     17.82mA    28.7mA
1.707V    34.39mA    21.79mA    47.68mA
3.797V    35.45mA    18.16mA    53.73mA
4.293V    26.89mA    3.485mA    49.33mA
5.038V    3.002mA    871.4uA    26.92mA
5.783V    903.1uA    485.4uA    3.433mA
6.6V      512.6uA    324.7uA    916.9uA
[Pullup]
| Voltage   I(typ)   I(min)   I(max)
-3.3V     775.3uA    487.4uA    1.181mA
-2.607V   1.309mA    735uA      3.011mA
-1.986V   3.506mA    1.318mA    13.54mA
-993.1mV  21.85mA    13.1mA     24.75mA
-620.7mV  17.35mA    14.17mA    18.9mA
1.024V    -29.57mA   -21.17mA   -35.34mA
1.934V    -44.73mA   -26.99mA   -60.67mA
3.797V    -46.9mA    -23.15mA   -70.97mA
4.417V    -33.81mA   -3.799mA   -63.46mA
5.162V    -5.034mA   -1.021mA   -37.7mA
6.031V    -1.089mA   -543.8uA   -6.056mA
6.6V      -731.8uA   -415.3uA   -1.532mA
[Ramp]
dV/dt_r   1.13914/0.239221n  0.791175/0.614129n  1.35569/0.122717n
dV/dt_f   1.01801/0.21596n  0.657879/0.419368n  1.28879/0.120301n
R_load = 50
[Falling Waveform]
R_fixture = 50
V_fixture = 0
V_fixture_min = 0
V_fixture_max = 0
| Time   V(typ)   V(min)   V(max)
0s        1.901V     1.32V      2.262V
856.7ps   1.901V     1.32V      2.239V
1.058ns   1.591V     1.32V      1.434V
1.165ns   1.326V     1.302V     108.4mV
1.276ns   932.5mV    1.093V     4.98mV
1.35ns    304.1mV    969.1mV    3.548mV
1.428ns   19.54mV    879mV      3.414mV
1.794ns   2.433mV    49.39mV    3.129mV
1.993ns   2.306mV    2.004mV    3.129mV
333.3ns   2.091mV    1.408mV    2.913mV
[Falling Waveform]
R_fixture = 50
V_fixture = 3.3
V_fixture_min = 3
V_fixture_max = 3.6
| Time   V(typ)   V(min)   V(max)
0s        3.3V       3V         3.6V
873.8ps   3.3V       3V         3.585V
1.112ns   3.16V      3.001V     3.151V
1.21ns    3.083V     2.991V     2.016V
1.302ns   2.991V     2.945V     1.601V
1.454ns   2.181V     2.88V      1.495V
1.575ns   1.871V     2.829V     1.475V
2.191ns   1.627V     2.064V     1.454V
5.667ns   1.603V     1.904V     1.452V
333.3ns   1.603V     1.904V     1.452V
[Rising Waveform]
R_fixture = 50
V_fixture = 0
V_fixture_min = 0
V_fixture_max = 0
| Time   V(typ)   V(min)   V(max)
0s        2.091mV    1.408mV    2.913mV
840.3ps   1.503mV    1.381mV    27.38mV
959.2ps   14.63mV    1.171mV    444.9mV
1.072ns   205.4mV    -458.2uV   1.716V
1.189ns   809.9mV    27.35mV    2.124V
1.319ns   1.411V     144.8mV    2.187V
1.475ns   1.688V     492mV      2.217V
1.845ns   1.827V     970.5mV    2.248V
2.453ns   1.882V     1.194V     2.26V
333.3ns   1.901V     1.32V      2.262V
[Rising Waveform]
R_fixture = 50
V_fixture = 3.3
V_fixture_min = 3
V_fixture_max = 3.6
| Time   V(typ)   V(min)   V(max)
0s        1.603V     1.904V     1.452V
787.5ps   1.603V     1.904V     1.479V
860.2ps   1.616V     1.904V     1.86V
959.5ps   1.936V     1.904V     3.173V
992.8ps   2.14V      1.909V     3.455V
1.116ns   3.116V     2.094V     3.597V
1.208ns   3.289V     2.365V     3.599V
1.376ns   3.299V     2.944V     3.599V
1.667ns   3.299V     2.999V     3.599V
333.3ns   3.3V       3V         3.6V
[Add Submodel]
| Submodel Name Mode
M8_PBIDIR_HS_04_F_3P30V_T All
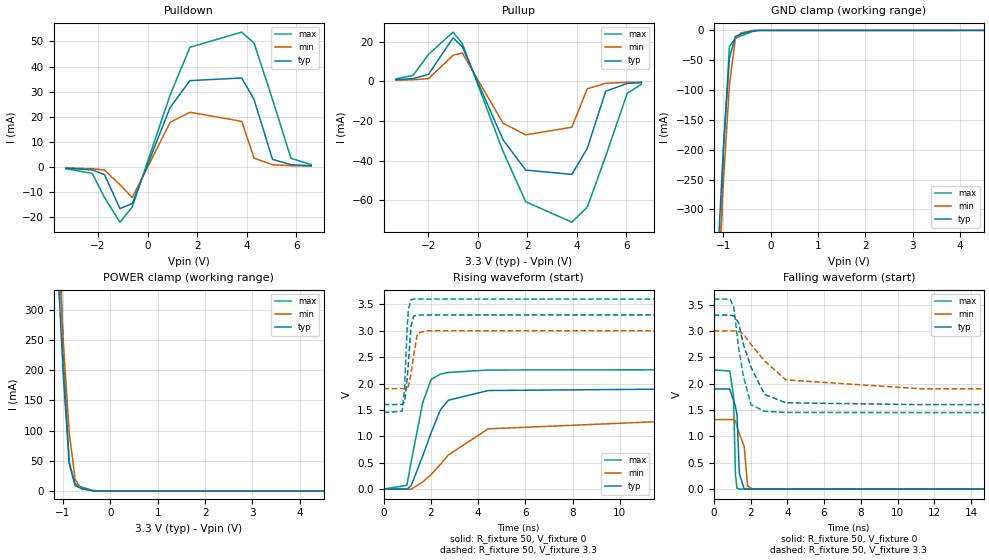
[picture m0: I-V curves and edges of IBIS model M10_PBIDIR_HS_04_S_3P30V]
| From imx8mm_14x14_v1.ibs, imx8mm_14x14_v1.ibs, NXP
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[Model] M10_PBIDIR_HS_04_S_3P30V
Model_type I/O
Vinl  =  0.99
Vinh  =  2.31
Vmeas =  1.65
| Capacitance   typ   min   max
C_comp   1.08818991111e-12   1.03117834871e-12   1.10439570077e-12
| Variables   typ   min   max
[GND Clamp Reference]   0   0   0
[POWER Clamp Reference]   3.3   3   3.6
[Pulldown Reference]   0   0   0
[Pullup Reference]   3.3   3   3.6
[Temperature Range]   25   125   -40
[Voltage Range]   3.3   3   3.6
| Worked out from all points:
|   slope of the pulldown table from 0 to 0.495 V, typ, clamps not added: 36.9 ohm
|   slope of the pullup table from 0 to 0.495 V, typ, clamps not added: 33.1 ohm
|   GND clamp passes 1 mA (typ) near -0.39 V on its own axis
|   POWER clamp passes 1 mA (typ) near -0.44 V on its own axis
|   falling waveform, R_fixture 50, V_fixture 0: 20-80 % time 167ps typ, 384ps min, 96.8ps max; typ from 1.9 V to 0.002 V
|   falling waveform, R_fixture 50, V_fixture 3.3: 20-80 % time 1.02ns typ, 1.74ns min, 576ps max; typ from 3.3 V to 1.6 V
|   rising waveform, R_fixture 50, V_fixture 0: 20-80 % time 981ps typ, 1.9ns min, 608ps max; typ from 0.002 V to 1.9 V
|   rising waveform, R_fixture 50, V_fixture 3.3: 20-80 % time 166ps typ, 211ps min, 128ps max; typ from 1.6 V to 3.3 V
[GND Clamp]
| Voltage   I(typ)   I(min)   I(max)
-3.3V     -7.236A    -6.565A    -8.004A
-1.117V   -380.4mA   -438.7mA   -546.7mA
-993.1mV  -191mA     -249.4mA   -198.9mA
-869mV    -46.61mA   -90.79mA   -26.93mA
-744.8mV  -10.31mA   -14.37mA   -13.71mA
-620.7mV  -5.945mA   -4.193mA   -9.059mA
-372.4mV  -659.7uA   -360.2uA   -1.673mA
-248.3mV  -143.8uA   -94.2uA    -265.5uA
6.6V      0A         0A         0A
[POWER Clamp]
| Voltage   I(typ)   I(min)   I(max)
-3.3V     7.237A     6.564A     8.009A
-1.117V   380.7mA    433.6mA    553.5mA
-993.1mV  190.7mA    247mA      219.9mA
-869mV    45.33mA    97.36mA    48.38mA
-744.8mV  8.677mA    19.82mA    11.82mA
-620.7mV  4.425mA    3.499mA    6.828mA
-372.4mV  215.5uA    293.3uA    764.6uA
-248.3mV  4.273uA    22.4uA     51.08uA
6.6V      0A         0A         0A
[Pulldown]
| Voltage   I(typ)   I(min)   I(max)
-3.3V     -504.5uA   -348.9uA   -699.6uA
-2.234V   -1.177mA   -696.7uA   -2.583mA
-1.738V   -3.068mA   -1.25mA    -12.18mA
-1.117V   -16.59mA   -7.062mA   -22.02mA
-620.7mV  -14.56mA   -12.2mA    -15.99mA
910.3mV   23.7mA     17.82mA    28.7mA
1.707V    34.39mA    21.79mA    47.68mA
3.797V    35.45mA    18.16mA    53.73mA
4.293V    26.89mA    3.485mA    49.33mA
5.038V    3.002mA    871.4uA    26.92mA
5.783V    903.1uA    485.4uA    3.433mA
6.6V      512.6uA    324.7uA    916.9uA
[Pullup]
| Voltage   I(typ)   I(min)   I(max)
-3.3V     774.6uA    487.4uA    1.177mA
-2.607V   1.308mA    735uA      2.992mA
-1.986V   3.502mA    1.318mA    13.51mA
-993.1mV  21.84mA    13.1mA     24.75mA
-620.7mV  17.35mA    14.17mA    18.89mA
1.024V    -29.57mA   -21.17mA   -35.34mA
1.934V    -44.73mA   -26.99mA   -60.67mA
3.797V    -46.9mA    -23.15mA   -70.97mA
4.417V    -33.81mA   -3.799mA   -63.46mA
5.162V    -5.033mA   -1.021mA   -37.7mA
6.031V    -1.089mA   -543.8uA   -6.054mA
6.6V      -731.8uA   -415.3uA   -1.532mA
[Ramp]
dV/dt_r   1.13914/0.980693n  0.791174/1.90271n  1.35567/0.607608n
dV/dt_f   1.01801/1.01965n  0.657879/1.73869n  1.28879/0.575754n
R_load = 50
[Falling Waveform]
R_fixture = 50
V_fixture = 0
V_fixture_min = 0
V_fixture_max = 0
| Time   V(typ)   V(min)   V(max)
0s        1.901V     1.32V      2.262V
865.5ps   1.901V     1.32V      2.239V
1.073ns   1.685V     1.319V     1.781V
1.18ns    1.568V     1.299V     270.5mV
1.268ns   1.401V     1.176V     15.69mV
1.391ns   294.8mV    1.054V     4.053mV
1.656ns   3.211mV    805.9mV    3.515mV
1.836ns   2.871mV    65.3mV     3.461mV
2.099ns   2.586mV    2.37mV     3.381mV
333.3ns   2.091mV    1.408mV    2.913mV
[Falling Waveform]
R_fixture = 50
V_fixture = 3.3
V_fixture_min = 3
V_fixture_max = 3.6
| Time   V(typ)   V(min)   V(max)
0s        3.3V       3V         3.6V
881.9ps   3.3V       3V         3.603V
1.088ns   3.281V     3.001V     3.454V
1.344ns   3.161V     2.991V     2.698V
1.606ns   2.754V     2.945V     2.146V
2.025ns   2.313V     2.743V     1.601V
2.768ns   1.794V     2.429V     1.477V
3.926ns   1.638V     2.072V     1.456V
11.21ns   1.603V     1.904V     1.452V
333.3ns   1.603V     1.904V     1.452V
[Rising Waveform]
R_fixture = 50
V_fixture = 0
V_fixture_min = 0
V_fixture_max = 0
| Time   V(typ)   V(min)   V(max)
0s        2.091mV    1.408mV    2.913mV
982.9ps   510.9uV    910.2uV    72.95mV
1.162ns   64.69mV    101.9uV    510.5mV
1.654ns   628.5mV    134.6mV    1.638V
2.014ns   1.072V     279.8mV    2.081V
2.4ns     1.501V     467.9mV    2.177V
2.737ns   1.684V     646.6mV    2.21V
4.427ns   1.868V     1.142V     2.256V
13.72ns   1.901V     1.319V     2.262V
333.3ns   1.901V     1.32V      2.262V
[Rising Waveform]
R_fixture = 50
V_fixture = 3.3
V_fixture_min = 3
V_fixture_max = 3.6
| Time   V(typ)   V(min)   V(max)
0s        1.603V     1.904V     1.452V
784.1ps   1.603V     1.903V     1.476V
884.6ps   1.652V     1.903V     1.903V
1.001ns   2.114V     1.912V     3.095V
1.047ns   2.378V     1.952V     3.4V
1.157ns   3.085V     2.18V      3.588V
1.275ns   3.278V     2.55V      3.599V
1.429ns   3.298V     2.948V     3.599V
1.766ns   3.299V     2.999V     3.6V
333.3ns   3.3V       3V         3.6V
[Add Submodel]
| Submodel Name Mode
M10_PBIDIR_HS_04_S_3P30V_T All
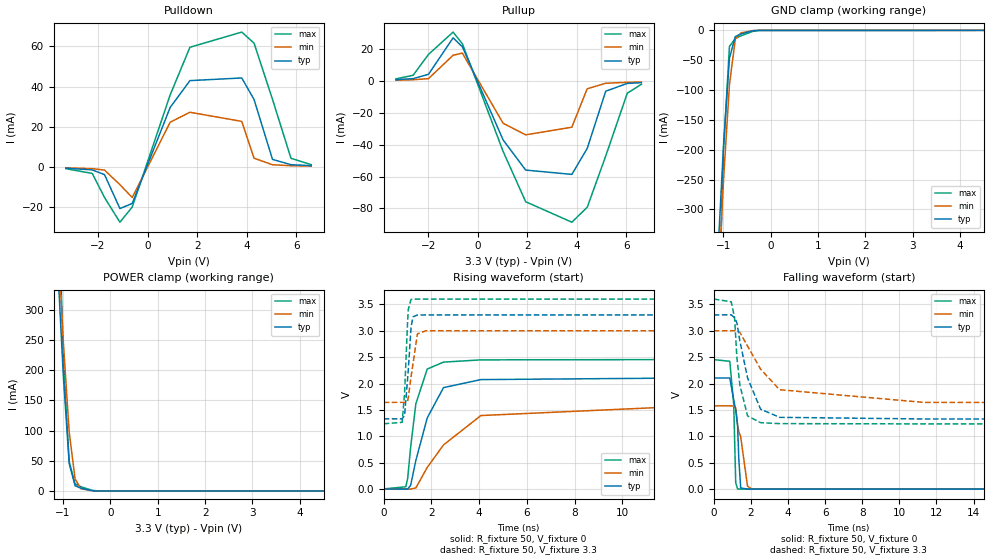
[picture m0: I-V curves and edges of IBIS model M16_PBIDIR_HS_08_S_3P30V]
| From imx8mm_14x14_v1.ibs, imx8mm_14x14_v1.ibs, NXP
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[Model] M16_PBIDIR_HS_08_S_3P30V
Model_type I/O
Vinl  =  0.99
Vinh  =  2.31
Vmeas =  1.65
| Capacitance   typ   min   max
C_comp   1.08818991111e-12   1.03117834871e-12   1.10439570077e-12
| Variables   typ   min   max
[GND Clamp Reference]   0   0   0
[POWER Clamp Reference]   3.3   3   3.6
[Pulldown Reference]   0   0   0
[Pullup Reference]   3.3   3   3.6
[Temperature Range]   25   125   -40
[Voltage Range]   3.3   3   3.6
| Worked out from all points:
|   slope of the pulldown table from 0 to 0.495 V, typ, clamps not added: 29.5 ohm
|   slope of the pullup table from 0 to 0.495 V, typ, clamps not added: 26.5 ohm
|   GND clamp passes 1 mA (typ) near -0.39 V on its own axis
|   POWER clamp passes 1 mA (typ) near -0.44 V on its own axis
|   falling waveform, R_fixture 50, V_fixture 0: 20-80 % time 285ps typ, 476ps min, 176ps max; typ from 2.11 V to 0.002 V
|   falling waveform, R_fixture 50, V_fixture 3.3: 20-80 % time 817ps typ, 1.63ns min, 393ps max; typ from 3.3 V to 1.33 V
|   rising waveform, R_fixture 50, V_fixture 0: 20-80 % time 824ps typ, 1.72ns min, 469ps max; typ from 0.002 V to 2.11 V
|   rising waveform, R_fixture 50, V_fixture 3.3: 20-80 % time 194ps typ, 249ps min, 140ps max; typ from 1.33 V to 3.3 V
[GND Clamp]
| Voltage   I(typ)   I(min)   I(max)
-3.3V     -7.236A    -6.565A    -8.004A
-1.117V   -380.4mA   -438.7mA   -546.7mA
-993.1mV  -191mA     -249.4mA   -198.9mA
-869mV    -46.61mA   -90.79mA   -26.93mA
-744.8mV  -10.31mA   -14.37mA   -13.71mA
-620.7mV  -5.945mA   -4.193mA   -9.059mA
-372.4mV  -659.7uA   -360.2uA   -1.673mA
-248.3mV  -143.8uA   -94.2uA    -265.5uA
6.6V      0A         0A         0A
[POWER Clamp]
| Voltage   I(typ)   I(min)   I(max)
-3.3V     7.237A     6.564A     8.009A
-1.117V   380.7mA    433.6mA    553.5mA
-993.1mV  190.7mA    247mA      219.9mA
-869mV    45.33mA    97.36mA    48.38mA
-744.8mV  8.677mA    19.82mA    11.82mA
-620.7mV  4.425mA    3.499mA    6.828mA
-372.4mV  215.5uA    293.3uA    764.6uA
-248.3mV  4.273uA    22.4uA     51.08uA
6.6V      0A         0A         0A
[Pulldown]
| Voltage   I(typ)   I(min)   I(max)
-3.3V     -630.6uA   -436.3uA   -874.4uA
-2.234V   -1.472mA   -870.7uA   -3.23mA
-1.738V   -3.836mA   -1.563mA   -15.22mA
-1.117V   -20.73mA   -8.828mA   -27.52mA
-620.7mV  -18.2mA    -15.24mA   -19.99mA
910.3mV   29.63mA    22.28mA    35.87mA
1.707V    42.99mA    27.23mA    59.6mA
3.797V    44.31mA    22.69mA    67.16mA
4.293V    33.61mA    4.356mA    61.66mA
5.038V    3.752mA    1.089mA    33.65mA
5.783V    1.129mA    606.5uA    4.292mA
6.6V      640.6uA    405.9uA    1.146mA
[Pullup]
| Voltage   I(typ)   I(min)   I(max)
-3.3V     968.4uA    609.2uA    1.472mA
-2.607V   1.636mA    918.8uA    3.746mA
-1.986V   4.378mA    1.647mA    16.9mA
-993.1mV  27.31mA    16.37mA    30.93mA
-620.7mV  21.69mA    17.71mA    23.62mA
1.024V    -36.96mA   -26.46mA   -44.17mA
1.934V    -55.91mA   -33.74mA   -75.84mA
3.797V    -58.63mA   -28.93mA   -88.71mA
4.417V    -42.26mA   -4.748mA   -79.32mA
5.162V    -6.292mA   -1.277mA   -47.12mA
6.031V    -1.361mA   -679.7uA   -7.568mA
6.6V      -914.7uA   -518.8uA   -1.915mA
[Ramp]
dV/dt_r   1.26224/0.823885n  0.945763/1.72345n  1.47108/0.468799n
dV/dt_f   1.18172/0.816793n  0.814588/1.63145n  1.41756/0.39282n
R_load = 50
[Falling Waveform]
R_fixture = 50
V_fixture = 0
V_fixture_min = 0
V_fixture_max = 0
| Time   V(typ)   V(min)   V(max)
0s        2.106V     1.578V     2.454V
863.7ps   2.105V     1.578V     2.422V
1.075ns   1.693V     1.576V     1.608V
1.183ns   1.498V     1.542V     120.3mV
1.284ns   1.197V     1.217V     5.75mV
1.351ns   557.6mV    1.091V     3.693mV
1.451ns   25.46mV    990.4mV    3.472mV
1.819ns   2.497mV    56.6mV     2.916mV
2.072ns   2.283mV    2.18mV     2.836mV
333.3ns   1.826mV    1.245mV    2.522mV
[Falling Waveform]
R_fixture = 50
V_fixture = 3.3
V_fixture_min = 3
V_fixture_max = 3.6
| Time   V(typ)   V(min)   V(max)
0s        3.3V       3V         3.6V
941ps     3.302V     3V         3.549V
1.122ns   3.246V     3.001V     3.243V
1.247ns   3.147V     3.005V     2.486V
1.408ns   2.803V     2.969V     1.971V
1.82ns    2.109V     2.71V      1.389V
2.521ns   1.516V     2.275V     1.26V
3.546ns   1.361V     1.884V     1.242V
11.35ns   1.33V      1.643V     1.237V
333.3ns   1.33V      1.642V     1.237V
[Rising Waveform]
R_fixture = 50
V_fixture = 0
V_fixture_min = 0
V_fixture_max = 0
| Time   V(typ)   V(min)   V(max)
0s        1.826mV    1.245mV    2.522mV
925.6ps   -1.961mV   1.188mV    43.21mV
1.006ns   582.3uV    -279uV     201.9mV
1.13ns    71.21mV    -355.7uV   793.8mV
1.348ns   542.4mV    21mV       1.616V
1.825ns   1.349V     410.1mV    2.275V
2.507ns   1.922V     836.8mV    2.405V
4.071ns   2.074V     1.393V     2.448V
13.07ns   2.106V     1.577V     2.454V
333.3ns   2.106V     1.578V     2.454V
[Rising Waveform]
R_fixture = 50
V_fixture = 3.3
V_fixture_min = 3
V_fixture_max = 3.6
| Time   V(typ)   V(min)   V(max)
0s        1.33V      1.642V     1.237V
775.1ps   1.33V      1.642V     1.264V
875.4ps   1.392V     1.642V     1.811V
998.9ps   2.069V     1.662V     3.141V
1.033ns   2.272V     1.733V     3.406V
1.146ns   3.058V     2.126V     3.593V
1.228ns   3.263V     2.373V     3.598V
1.413ns   3.298V     2.94V      3.599V
1.764ns   3.299V     2.999V     3.599V
333.3ns   3.3V       3V         3.6V
[Add Submodel]
| Submodel Name Mode
M16_PBIDIR_HS_08_S_3P30V_T All
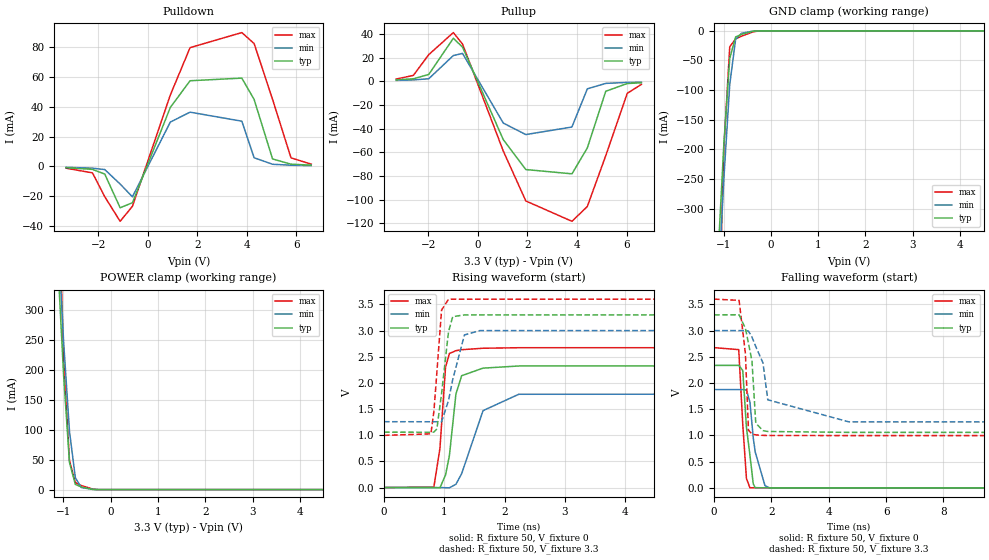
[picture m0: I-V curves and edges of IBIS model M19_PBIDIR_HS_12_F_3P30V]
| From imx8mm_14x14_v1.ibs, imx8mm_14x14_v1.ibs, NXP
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[Model] M19_PBIDIR_HS_12_F_3P30V
Model_type I/O
Vinl  =  0.99
Vinh  =  2.31
Vmeas =  1.65
| Capacitance   typ   min   max
C_comp   1.08818991111e-12   1.03117834871e-12   1.10439570077e-12
| Variables   typ   min   max
[GND Clamp Reference]   0   0   0
[POWER Clamp Reference]   3.3   3   3.6
[Pulldown Reference]   0   0   0
[Pullup Reference]   3.3   3   3.6
[Temperature Range]   25   125   -40
[Voltage Range]   3.3   3   3.6
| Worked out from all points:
|   slope of the pulldown table from 0 to 0.495 V, typ, clamps not added: 22.1 ohm
|   slope of the pullup table from 0 to 0.495 V, typ, clamps not added: 19.9 ohm
|   GND clamp passes 1 mA (typ) near -0.39 V on its own axis
|   POWER clamp passes 1 mA (typ) near -0.44 V on its own axis
|   falling waveform, R_fixture 50, V_fixture 0: 20-80 % time 238ps typ, 359ps min, 173ps max; typ from 2.34 V to 0.002 V
|   falling waveform, R_fixture 50, V_fixture 3.3: 20-80 % time 244ps typ, 419ps min, 179ps max; typ from 3.3 V to 1.06 V
|   rising waveform, R_fixture 50, V_fixture 0: 20-80 % time 141ps typ, 341ps min, 100ps max; typ from 0.002 V to 2.34 V
|   rising waveform, R_fixture 50, V_fixture 3.3: 20-80 % time 133ps typ, 195ps min, 94ps max; typ from 1.06 V to 3.3 V
[GND Clamp]
| Voltage   I(typ)   I(min)   I(max)
-3.3V     -7.236A    -6.565A    -8.004A
-1.117V   -380.4mA   -438.7mA   -546.7mA
-993.1mV  -191mA     -249.4mA   -198.9mA
-869mV    -46.61mA   -90.79mA   -26.93mA
-744.8mV  -10.31mA   -14.37mA   -13.71mA
-620.7mV  -5.945mA   -4.193mA   -9.059mA
-372.4mV  -659.7uA   -360.2uA   -1.673mA
-248.3mV  -143.8uA   -94.2uA    -265.5uA
6.6V      0A         0A         0A
[POWER Clamp]
| Voltage   I(typ)   I(min)   I(max)
-3.3V     7.237A     6.564A     8.009A
-1.117V   380.7mA    433.6mA    553.5mA
-993.1mV  190.7mA    247mA      219.9mA
-869mV    45.33mA    97.36mA    48.38mA
-744.8mV  8.677mA    19.82mA    11.82mA
-620.7mV  4.425mA    3.499mA    6.828mA
-372.4mV  215.5uA    293.3uA    764.6uA
-248.3mV  4.273uA    22.4uA     51.08uA
6.6V      0A         0A         0A
[Pulldown]
| Voltage   I(typ)   I(min)   I(max)
-3.3V     -840.9uA   -581.7uA   -1.166mA
-2.234V   -1.962mA   -1.161mA   -4.306mA
-1.738V   -5.114mA   -2.084mA   -20.29mA
-1.117V   -27.64mA   -11.77mA   -36.7mA
-620.7mV  -24.27mA   -20.33mA   -26.65mA
910.3mV   39.51mA    29.7mA     47.83mA
1.707V    57.32mA    36.31mA    79.47mA
3.797V    59.08mA    30.26mA    89.55mA
4.293V    44.81mA    5.808mA    82.22mA
5.038V    5.003mA    1.452mA    44.86mA
5.783V    1.505mA    808.7uA    5.722mA
6.6V      854.3uA    541.3uA    1.528mA
[Pullup]
| Voltage   I(typ)   I(min)   I(max)
-3.3V     1.292mA    812.3uA    1.969mA
-2.607V   2.182mA    1.225mA    5.027mA
-1.986V   5.844mA    2.197mA    22.58mA
-993.1mV  36.41mA    21.83mA    41.25mA
-620.7mV  28.92mA    23.62mA    31.49mA
1.024V    -49.28mA   -35.28mA   -58.9mA
1.934V    -74.55mA   -44.98mA   -101.1mA
3.797V    -78.17mA   -38.58mA   -118.3mA
4.417V    -56.34mA   -6.331mA   -105.8mA
5.162V    -8.389mA   -1.702mA   -62.83mA
6.031V    -1.815mA   -906.2uA   -10.09mA
6.6V      -1.22mA    -691.9uA   -2.554mA
[Ramp]
dV/dt_r   1.4006/0.141063n  1.1252/0.340599n  1.60348/0.100285n
dV/dt_f   1.34487/0.244231n  1.04489/0.418706n  1.56141/0.179352n
R_load = 50
[Falling Waveform]
R_fixture = 50
V_fixture = 0
V_fixture_min = 0
V_fixture_max = 0
| Time   V(typ)   V(min)   V(max)
0s        2.336V     1.876V     2.675V
859.9ps   2.336V     1.876V     2.637V
1.001ns   2.239V     1.876V     1.208V
1.129ns   1.151V     1.866V     177.8mV
1.251ns   620.9mV    1.634V     3.174mV
1.367ns   76.15mV    952.3mV    2.529mV
1.435ns   4.912mV    685.7mV    2.529mV
1.775ns   1.798mV    43.02mV    2.529mV
1.935ns   1.746mV    1.728mV    2.528mV
333.3ns   1.508mV    1.043mV    2.062mV
[Falling Waveform]
R_fixture = 50
V_fixture = 3.3
V_fixture_min = 3
V_fixture_max = 3.6
| Time   V(typ)   V(min)   V(max)
0s        3.3V       3V         3.6V
872.1ps   3.301V     3V         3.577V
1.093ns   3.042V     3.001V     2.562V
1.199ns   2.757V     2.99V      1.102V
1.322ns   2.418V     2.876V     1.026V
1.454ns   1.235V     2.696V     1.011V
1.705ns   1.092V     2.384V     1.002V
1.873ns   1.076V     1.68V      999.8mV
4.702ns   1.059V     1.259V     997.7mV
333.3ns   1.059V     1.259V     997.7mV
[Rising Waveform]
R_fixture = 50
V_fixture = 0
V_fixture_min = 0
V_fixture_max = 0
| Time   V(typ)   V(min)   V(max)
0s        1.508mV    1.043mV    2.062mV
828.1ps   152.1uV    1.042mV    10.26mV
928.5ps   -4.649mV   862.5uV    746.1mV
1.022ns   240.9mV    -1.752mV   2.303V
1.086ns   613mV      -3.744mV   2.561V
1.194ns   1.787V     63.67mV    2.615V
1.289ns   2.137V     266mV      2.634V
1.644ns   2.282V     1.47V      2.662V
2.237ns   2.323V     1.783V     2.672V
333.3ns   2.336V     1.876V     2.675V
[Rising Waveform]
R_fixture = 50
V_fixture = 3.3
V_fixture_min = 3
V_fixture_max = 3.6
| Time   V(typ)   V(min)   V(max)
0s        1.059V     1.259V     997.7mV
778.8ps   1.058V     1.258V     1.027V
829.1ps   1.061V     1.258V     1.461V
877.8ps   1.12V      1.258V     2.198V
955.9ps   1.797V     1.26V      3.391V
1.071ns   2.974V     1.661V     3.597V
1.141ns   3.265V     2.064V     3.599V
1.335ns   3.299V     2.916V     3.599V
1.591ns   3.299V     2.999V     3.599V
333.3ns   3.3V       3V         3.6V
[Add Submodel]
| Submodel Name Mode
M19_PBIDIR_HS_12_F_3P30V_T All
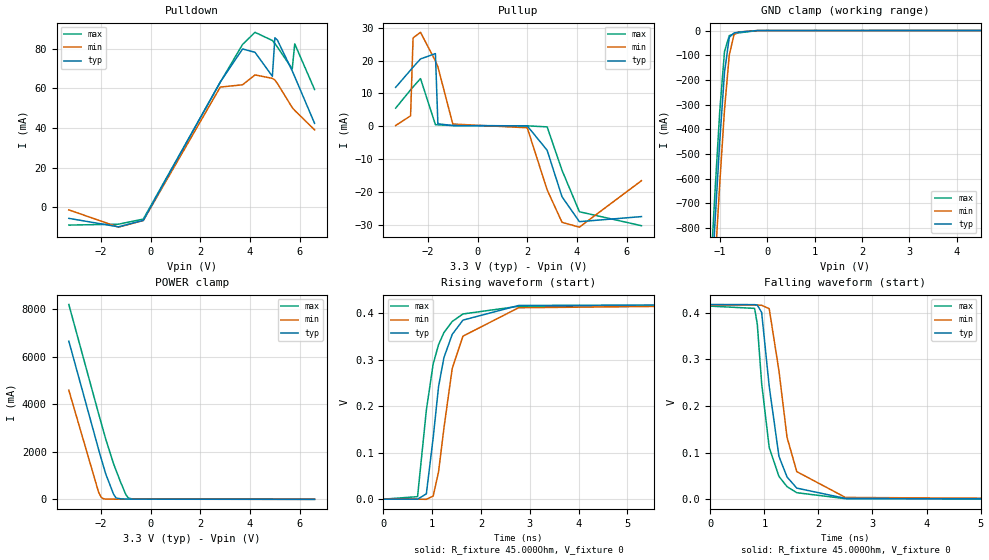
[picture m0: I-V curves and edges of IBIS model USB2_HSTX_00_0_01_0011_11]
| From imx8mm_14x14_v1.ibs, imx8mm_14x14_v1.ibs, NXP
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[Model] USB2_HSTX_00_0_01_0011_11
Model_type   Output
Polarity   Non-Inverting
Enable   Active-High
C_comp   8.031pF   7.549pF   8.682pF
Vmeas = 200.000mV
Vref = 200.000mV
Rref = 45Ohms
Cref = 0pF
[Model Spec]
Vmeas   200.000mV   200.000mV   200.000mV
Vref   200.000mV   200.000mV   200.000mV
[Temperature Range]   25.000   125.000   -40.000
[Voltage Range]   3.300V   2.790V   3.630V
[GND Clamp Reference]   0.00V   0.00V   0.00V
[Pulldown Reference]   0.00V   0.00V   0.00V
[POWER Clamp Reference]   3.300V   2.790V   3.630V
[Pullup Reference]   3.300V   2.790V   3.630V
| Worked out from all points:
|   slope of the pulldown table from 0 to 0.495 V, typ, clamps not added: 43.3 ohm
|   GND clamp passes 1 mA (typ) near -0.34 V on its own axis
|   POWER clamp passes 1 mA (typ) near -0.41 V on its own axis
|   rising waveform, R_fixture 45.000Ohm, V_fixture 0: 20-80 % time 351ps typ, 392ps min, 338ps max; typ from 0 V to 0.419 V
|   falling waveform, R_fixture 45.000Ohm, V_fixture 0: 20-80 % time 271ps typ, 311ps min, 249ps max; typ from 0.418 V to 0 V
[GND Clamp]
-3.3V     -9.113A    -9.232A    -9.03A
-1.2V     -1.128A    -1.297A    -1.005A
-1.1V     -777.4mA   -949.7mA   -651.7mA
-1V       -447.5mA   -618.9mA   -326.1mA
-900mV    -169.6mA   -321mA     -84.95mA
-800mV    -27.68mA   -100.1mA   -20.94mA
-700mV    -9.82mA    -16.96mA   -13.78mA
-600mV    -6.587mA   -5.686mA   -9.454mA
-200mV    -24.15uA   -26.49uA   -94.76uA
6.6V      5.895uA    6.005uA    6.483uA
[Power Clamp]
-3.3V     6.664A     4.598A     8.209A
-2.1V     2.101A     298.1mA    3.607A
-2V       1.735A     92.62mA    3.235A
-1.9V     1.376A     18.36mA    2.861A
-1.8V     1.031A     9.661mA    2.494A
-1.5V     224.5mA    6.985mA    1.507A
-1.4V     60.59mA    6.316mA    1.227A
-1.2V     18.43mA    5.899mA    687.8mA
-1V       13.32mA    6.636mA    196.6mA
-900mV    10.87mA    6.807mA    51.5mA
-700mV    6.234mA    4.9mA      8.311mA
6.6V      -3.575uA   -6.438uA   -3.452uA
[Pulldown]
-3.3V     -5.577mA   -1.305mA   -8.977mA
-1.3V     -9.861mA   -10.02mA   -8.524mA
-300mV    -6.591mA   -6.677mA   -5.956mA
2.8V      63.22mA    60.66mA    63.06mA
3.7V      79.89mA    61.81mA    82.19mA
4.2V      78.19mA    66.79mA    88.28mA
4.9V      66.09mA    65.04mA    84.15mA
5V        85.5mA     64.22mA    82.61mA
5.1V      84.42mA    62.51mA    80.89mA
5.7V      68.79mA    50.3mA     69.8mA
5.8V      65.9mA     48.88mA    82.46mA
6.6V      42.35mA    39.06mA    59.41mA
[Pullup]
-3.3V     11.85mA    208.2uA    5.518mA
-2.7V     17.12mA    3.159mA    11.08mA
-2.6V     18.01mA    26.92mA    11.96mA
-2.3V     20.51mA    28.63mA    14.52mA
-1.7V     22.14mA    19.88mA    456.7uA
-1.6V     709uA      18.1mA     404uA
-1V       199.4uA    652.2uA    180.8uA
2V        75.08uA    -492.9uA   100.5uA
2.8V      -7.344mA   -19.42mA   -215.9uA
3.4V      -21.54mA   -29.34mA   -13.46mA
4.1V      -29.13mA   -30.81mA   -26.11mA
6.6V      -27.59mA   -16.63mA   -30.37mA
[Ramp]
R_load=45.000Ohm
dV/dt_r   251mV/350.000ps  251mV/390.000ps  249mV/340.000ps
dV/dt_f   250mV/270.000ps  250mV/310.000ps  248mV/250.000ps
[Rising waveform]
R_fixture=45.000Ohm
V_fixture=0
0s        288nV      1.309uV    364.3nV
700ps     -50.56uV   -12.35uV   5.354mV
880ps     11.38mV    -387.9uV   191.3mV
1.02ns    132mV      6.603mV    290.9mV
1.13ns    241.8mV    58.64mV    332.2mV
1.24ns    304.4mV    152.5mV    358.2mV
1.41ns    354.4mV    281mV      382.2mV
1.63ns    385.1mV    350.6mV    398.3mV
2.77ns    416.6mV    411.7mV    414.8mV
8.33ns    418.7mV    417.3mV    415.2mV
[Falling waveform]
R_fixture=45.000Ohm
V_fixture=0
0s        417.6mV    416.2mV    414.1mV
820ps     417.3mV    416.2mV    409.3mV
870ps     416.3mV    416.2mV    375mV
950ps     400.6mV    415.9mV    248.8mV
1.09ns    242.1mV    408.6mV    111.1mV
1.27ns    92.26mV    275.6mV    49.18mV
1.42ns    47.78mV    132.7mV    27.2mV
1.6ns     24.05mV    59.38mV    14.18mV
2.5ns     2.008mV    4.064mV    1.432mV
8.33ns    21.47uV    102.8uV    16.56uV
